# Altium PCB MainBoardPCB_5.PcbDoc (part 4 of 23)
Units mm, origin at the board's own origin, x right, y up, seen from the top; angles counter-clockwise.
Board outline 258.95 x 308.86 mm, 16 copper layers (L1, L2 (GND), L3 (Sign), L4 (GND), L5 (Sign), L6 (PWR/GND), L7(PWR/GND), L8 (Plane_GND), L9 (PWR/GND), L10 (PWR/GND), L11 (PWR/GND), L12 (Sign), L13 (GND), L14 (Sign), L15 (GND), L16), stack 2.502 mm thick; 2361 components, 1769 nets, 8410 pads, 3285 vias.
Unrouted connection lines stored in the file: 4635.

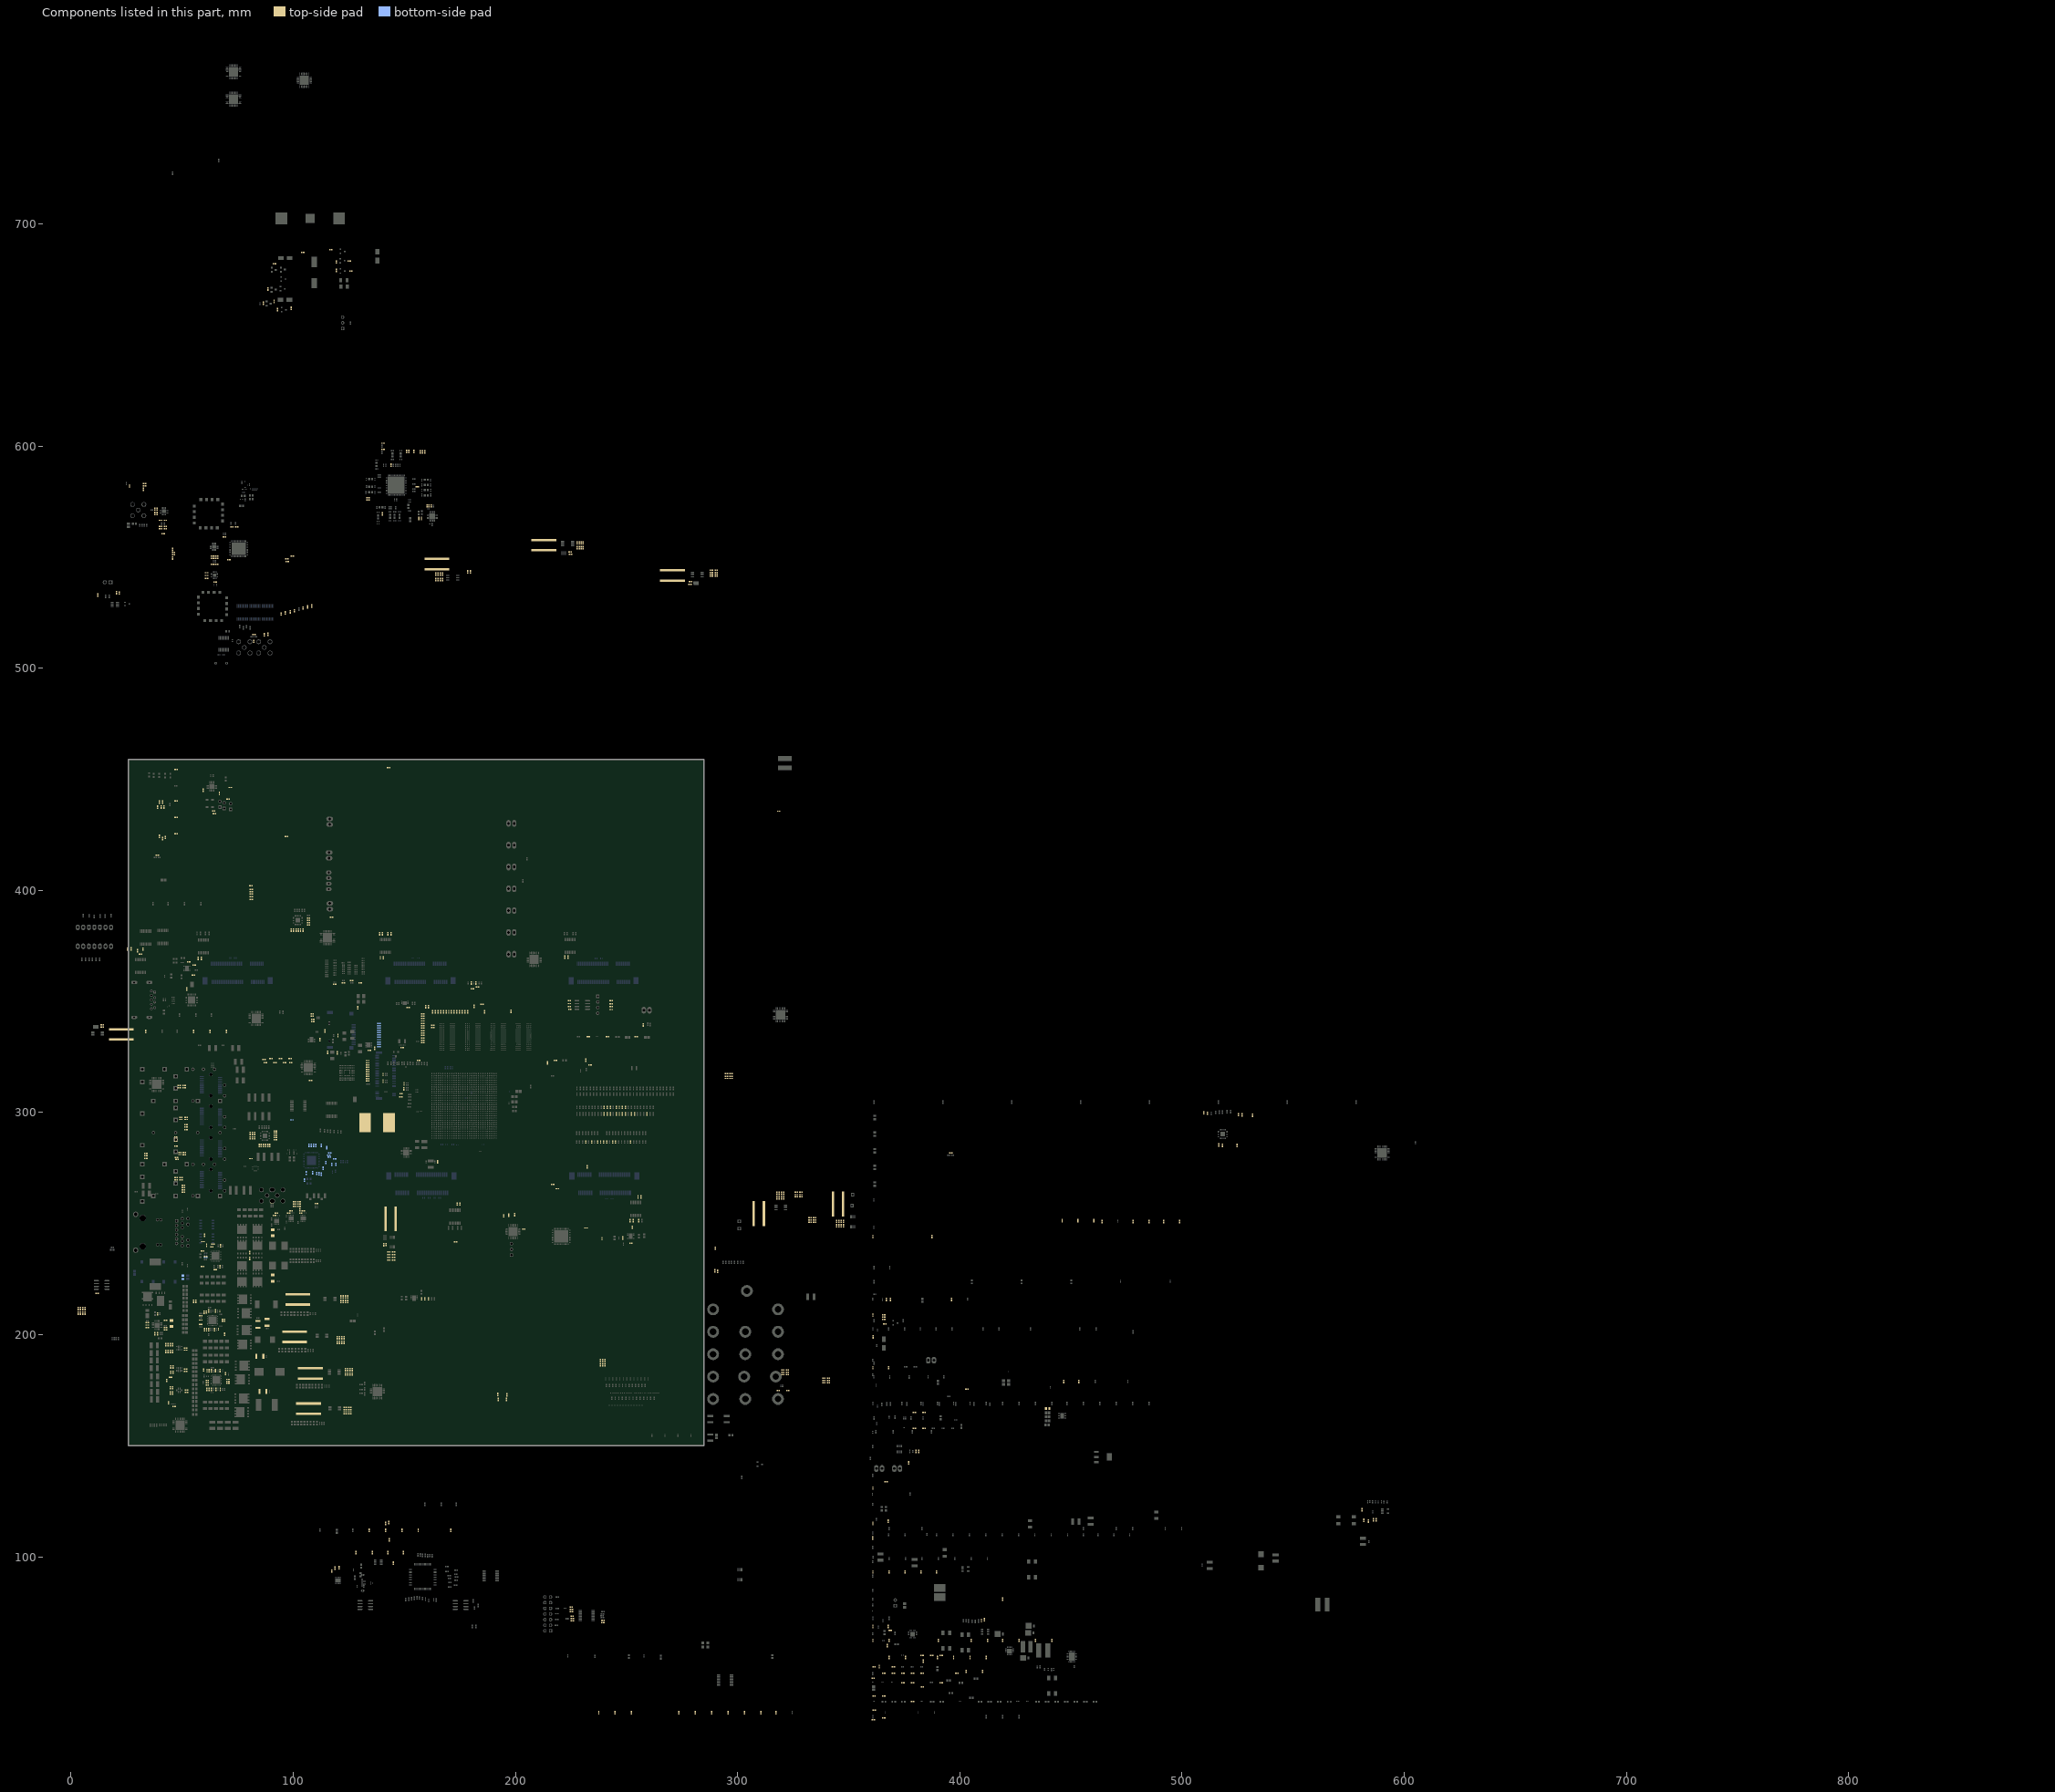
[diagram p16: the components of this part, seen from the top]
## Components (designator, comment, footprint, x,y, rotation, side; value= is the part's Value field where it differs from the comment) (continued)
R8_I2C_Bridge_SFP "1kR" "RES 0402/1005 RF" 92.004,291.728 r0 top (schematic designator R8)
R9_I2C_Bridge_GPIO "1kR" "RES 0402/1005 RF" 531.816,298.788 r90 top (schematic designator R9)
R9_I2C_Bridge_PCIE "1kR" "RES 0402/1005 RF" 106.896,387.59 r0 top (schematic designator R9)
R9_I2C_Bridge_SFP "1kR" "RES 0402/1005 RF" 92.004,290.754 r0 top (schematic designator R9)
R10_I2C_Bridge_GPIO "1kR" "RES 0402/1005 RF" 524.764,285.123 r90 top (schematic designator R10)
R10_I2C_Bridge_PCIE "1kR" "RES 0402/1005 RF" 106.896,386.535 r0 top (schematic designator R10)
R10_I2C_Bridge_SFP "1kR" "RES 0402/1005 RF" 92.004,289.78 r0 top (schematic designator R10)
R11 "10kR" "RES 0402/1005 RF" 51.56,183.563 r0 top
R12 "95.3kR" "RES 0402/1005 RF" 45.844,173.839 r270 top
R13 "10kR" "RES 0402/1005 RF" 51.568,193.051 r180 top
R14 "0mR" "RES 0402/1005 RF" 192.113,173.126 r90 top
R15 "95.3kR" "RES 0402/1005 RF" 45.94,183.113 r270 top
R16 "0mR" "RES 0402/1005 RF" 196.177,172.872 r90 top
R17 "95.3kR" "RES 0402/1005 RF" 45.94,185.524 r90 top
R18 "24.9kR" "RES 0402/1005 RF" 51.56,184.471 r180 top
R19 "4.87kR" "RES 0402/1005 RF" 44.801,173.839 r90 top
R20 "95.3kR" "RES 0402/1005 RF" 45.822,176.136 r90 top
R21 "24.9kR" "RES 0402/1005 RF" 52.05,175.125 r180 top
R22 "0mR" "RES 0402/1005 RF" 192.367,170.84 r90 top
R23 "4.87kR" "RES 0402/1005 RF" 44.92,183.113 r90 top
R24 "0mR" "RES 0402/1005 RF" 196.05,170.84 r90 top
R25 "4.87kR" "RES 0402/1005 RF" 44.92,185.524 r270 top
R26 "4.87kR" "RES 0402/1005 RF" 44.801,176.136 r270 top
R27 "1.02kR" "RES 0402/1005 RF" 46.46,167.684 r0 top
R28 "1.02kR" "RES 0402/1005 RF" 43.129,179.425 r270 top
R29 "10kR" "RES 0402/1005 RF" 43.904,169.348 r90 top
R30 "10kR" "RES 0402/1005 RF" 44.831,180.9 r180 top
R31 "39.2R" "RES 0402/1005 RF" 174.855,345.25 r90 top
R32 "39.2R" "RES 0402/1005 RF" 170.02,345.25 r90 top
R33 "39.2R" "RES 0402/1005 RF" 158.287,340.144 r180 top
R34 "39.2R" "RES 0402/1005 RF" 158.287,339.055 r180 top
R35 "39.2R" "RES 0402/1005 RF" 173.646,345.25 r90 top
R36 "39.2R" "RES 0402/1005 RF" 167.603,345.25 r90 top
R37 "39.2R" "RES 0402/1005 RF" 158.287,337.967 r180 top
R38 "39.2R" "RES 0402/1005 RF" 162.769,345.25 r90 top
R39 "39.2R" "RES 0402/1005 RF" 171.229,345.25 r90 top
R40 "39.2R" "RES 0402/1005 RF" 166.395,345.25 r90 top
R41 "39.2R" "RES 0402/1005 RF" 158.287,341.233 r180 top
R42 "39.2R" "RES 0402/1005 RF" 172.438,345.25 r90 top
R43 "39.2R" "RES 0402/1005 RF" 178.481,345.25 r90 top
R44 "39.2R" "RES 0402/1005 RF" 163.977,345.25 r90 top
R45 "39.2R" "RES 0402/1005 RF" 158.287,343.411 r180 top
R46 "39.2R" "RES 0402/1005 RF" 158.287,333.611 r180 top
R47 "39.2R" "RES 0402/1005 RF" 177.272,345.25 r90 top
R48 "39.2R" "RES 0402/1005 RF" 158.287,342.322 r180 top
R49 "39.2R" "RES 0402/1005 RF" 168.812,345.25 r90 top
R50 "39.2R" "RES 0402/1005 RF" 176.063,345.25 r90 top
R51 "39.2R" "RES 0402/1005 RF" 158.287,335.789 r180 top
R52 "36R" "RES 0402/1005 RF" 158.287,331.433 r180 top
R53 "39.2R" "RES 0402/1005 RF" 158.287,344.5 r180 top
R54 "36R" "RES 0402/1005 RF" 158.287,332.522 r180 top
R55 "39.2R" "RES 0402/1005 RF" 165.186,345.25 r90 top
R56 "499R" "RES 0402/1005 RF" 162.91,338.184 r180 top
R57 "39.2R" "RES 0402/1005 RF" 158.287,336.878 r180 top
R58 "4.7kR" "RES 0402/1005 RF" 162.91,339.242 r180 top
R59 "39.2R" "RES 0402/1005 RF" 158.287,334.7 r180 top
R60 "1kR" "RES 0402/1005 RF" 184.994,348.704 r180 top
R61 "240R" "RES 0402/1005 RF" 198.031,345.611 r90 top
R62 "240R" "RES 0402/1005 RF" 186.195,345.262 r90 top
R63 "240R" "RES 0402/1005 RF" 156.464,323.541 r180 top
R64 "240R" "RES 0402/1005 RF" 181.458,347.789 r90 top
R65 "4.7kR" "RES 0402/1005 RF" 50.624,266.152 r180 top
R66 "4.7kR" "RES 0402/1005 RF" 50.624,267.233 r180 top
R67 "4.7kR" "RES 0402/1005 RF" 50.624,264.12 r180 top
R68 "4.7kR" "RES 0402/1005 RF" 50.624,265.136 r180 top
R69 "100R" "RES 0402/1005 RF" 149.898,312.903 r270 top
R70 "100R" "RES 0402/1005 RF" 149.885,310.7 r90 top
R71 "0R" "RES 0402/1005 RF" 47.333,270.662 r180 top
R72 "0R" "RES 0402/1005 RF" 47.333,269.646 r180 top
R73 "0R" "RES 0402/1005 RF" 49.495,270.662 r180 top
R74 "0R" "RES 0402/1005 RF" 49.495,269.646 r180 top
R75 "0mR" "RES 0402/1005 RF" 90.504,259.536 r180 top
R76 "150R" "RES 0402/1005 RF" 110.431,258.992 r0 top
R77 "7.5kR" "RES 0402/1005 RF" 69.059,558.99 r180 top
R78 "100R" "RES 0402/1005 RF" 82.334,515.138 r0 top
R79 "150R" "RES 0402/1005 RF" 38.837,415.773 r0 top
R80 "160R" "RES 0402/1005 RF" 395.915,281.813 r0 top
R81 "100R" "RES 0402/1005 RF" 218.91,265.7 r180 top
R82 "100R" "RES 0402/1005 RF" 82.347,512.059 r90 top
R83 "4.7kR" "RES 0402/1005 RF" 108.547,344.313 r0 top
R84 "4.7kR" "RES 0402/1005 RF" 108.801,340.893 r0 top
R85 "4.7kR" "RES 0402/1005 RF" 108.547,343.433 r0 top
R86 "4.7kR" "RES 0402/1005 RF" 108.801,342.036 r0 top
R87 "30R" "RES 0402/1005 RF" 138.537,332.814 r180 bottom
R88 "30R" "RES 0402/1005 RF" 138.537,330.731 r180 bottom
R89 "30R" "RES 0402/1005 RF" 138.537,338.021 r180 bottom
R90 "30R" "RES 0402/1005 RF" 138.537,335.938 r180 bottom
R91 "0R" "RES 0402/1005 RF" 138.537,336.979 r180 bottom
R92 "0R" "RES 0402/1005 RF" 138.537,339.062 r180 bottom
R93 "0R" "RES 0402/1005 RF" 138.537,340.103 r180 bottom
R94 "0R" "RES 0402/1005 RF" 138.537,329.689 r180 bottom
R95 "30R" "RES 0402/1005 RF" 138.537,331.772 r180 bottom
R96 "30R" "RES 0402/1005 RF" 138.537,334.896 r180 bottom
R97 "4.7kR" "RES 0402/1005 RF" 138.537,333.855 r180 bottom
R98 "4.7kR" "RES 0402/1005 RF" 99.424,296.697 r180 bottom
R99 "4.7kR" "RES 0402/1005 RF" 367.411,60.089 r90 top
R100 "Resistance" "RES 0402/1005 RF" 318.491,435.623 r0 top
R101 "30R" "RES 0402/1005 RF" 133.566,322.351 r180 top
R102 "30R" "RES 0402/1005 RF" 133.566,320.319 r180 top
R103 "30R" "RES 0402/1005 RF" 133.566,318.287 r180 top
R104 "30R" "RES 0402/1005 RF" 133.566,316.255 r180 top
R105 "30R" "RES 0402/1005 RF" 133.566,321.335 r180 top
R106 "1kR" "RES 0402/1005 RF" 96.99,424.332 r180 top
R107 "30R" "RES 0402/1005 RF" 133.566,319.303 r180 top
R108 "30R" "RES 0402/1005 RF" 133.566,317.271 r180 top
R109 "1kR" "RES 0402/1005 RF" 142.964,455.193 r0 top
R110 "30R" "RES 0402/1005 RF" 133.566,323.367 r180 top
R111 "30R" "RES 0402/1005 RF" 133.566,315.214 r180 top
R112 "30R" "RES 0402/1005 RF" 133.566,314.223 r180 top
R113 "34.8kR" "RES 0402/1005 RF" 367.741,68.682 r90 top
R114 "10kR" "RES 0402/1005 RF" 360.883,68.682 r90 top
R115 "30R" "RES 0402/1005 RF" 98.895,322.478 r0 top
R116 "30R" "RES 0402/1005 RF" 96.101,322.478 r0 top
R117 "30R" "RES 0402/1005 RF" 91.783,322.478 r0 top
R118 "30R" "RES 0402/1005 RF" 87.465,322.478 r0 top
R119 "30R" "RES 0402/1005 RF" 98.641,324.256 r0 top
R120 "30R" "RES 0402/1005 RF" 94.323,324.256 r0 top
R121 "30R" "RES 0402/1005 RF" 90.005,324.256 r0 top
R122 "30R" "RES 0402/1005 RF" 86.83,323.875 r0 top
R123 "4.7kR" "RES 0402/1005 RF" 107.912,314.35 r0 top
R124 "1kR" "RES 0402/1005 RF" 173.063,241.833 r180 top
R125 "10kR" "RES 0402/1005 RF" 155.858,581.652 r180 top
R126 "100R" "RES 0402/1005 RF" 152.029,597.498 r270 top
R127 "0R" "RES 0402/1005 RF" 367.995,185.141 r90 top
R128 "10kR" "RES 0402/1005 RF" 133.738,575.768 r180 top
R129 "10kR" "RES 0402/1005 RF" 133.738,576.707 r180 top
R130 "0R" "RES 0402/1005 RF" 151.032,597.485 r270 top
R131 "0R" "RES 0402/1005 RF" 154.274,597.485 r270 top
R132 "0R" "RES 0402/1005 RF" 158.135,597.371 r90 top
R133 "0R" "RES 0402/1005 RF" 159.151,597.371 r90 top
R134 "0R" "RES 0402/1005 RF" 157.128,597.416 r90 top
R135 "4.7kR" "RES 0402/1005 RF" 47.725,278.917 r0 top
R136 "4.7kR" "RES 0402/1005 RF" 47.46,279.679 r0 top
R137 "4.7kR" "RES 0402/1005 RF" 47.275,284.886 r0 top
R138 "4.7kR" "RES 0402/1005 RF" 33.686,279.307 r0 top
R139 "0R" "RES 0402/1005 RF" 360.883,185.141 r90 top
R140 "2.2R" "RES 0402/1005 RF" 34.297,205.384 r180 top
R141 "0R" "RES 0402/1005 RF" 51.019,281.072 r0 top
R142 "0R" "RES 0402/1005 RF" 51.019,282.106 r0 top
R143 "0R" "RES 0402/1005 RF" 49.045,281.09 r0 top
R144 "0R" "RES 0402/1005 RF" 49.045,282.106 r0 top
R145 "4.7kR" "RES 0402/1005 RF" 47.206,289.077 r0 top
R146 "4.7kR" "RES 0402/1005 RF" 47.206,287.172 r0 top
R147 "4.7kR" "RES 0402/1005 RF" 47.206,288.061 r0 top
R148 "4.7kR" "RES 0402/1005 RF" 33.686,281.593 r0 top
R149 "196kR" "RES 0402/1005 RF" 34.323,204.343 r0 top
R150 "22k" "RES 0402/1005 RF" 42.652,206.468 r0 top
R151 "0R" "RES 0402/1005 RF" 51.863,297.915 r0 top
R152 "0R" "RES 0402/1005 RF" 51.816,296.899 r0 top
R153 "0R" "RES 0402/1005 RF" 49.45,297.915 r0 top
R154 "0R" "RES 0402/1005 RF" 49.45,296.899 r0 top
R155 "4.7kR" "RES 0402/1005 RF" 51.75,294.51 r0 top
R156 "4.7kR" "RES 0402/1005 RF" 51.75,293.494 r0 top
R157 "4.7kR" "RES 0402/1005 RF" 51.741,292.224 r0 top
R158 "4.7kR" "RES 0402/1005 RF" 33.686,280.568 r0 top
R159 "10kR" "RES 0402/1005 RF" 34.323,203.149 r0 top
R160 "910R" "RES 0402/1005 RF" 42.528,203.203 r180 top
R161 "0R" "RES 0402/1005 RF" 50.943,312.266 r0 top
R162 "0R" "RES 0402/1005 RF" 50.943,311.25 r0 top
R163 "0R" "RES 0402/1005 RF" 48.704,312.266 r0 top
R164 "0R" "RES 0402/1005 RF" 48.704,311.25 r0 top
R165 "100R" "RES 0402/1005 RF" 182.99,356.502 r0 top
R166 "100R" "RES 0402/1005 RF" 180.646,355.74 r0 top
R167 "100R" "RES 0402/1005 RF" 182.281,358.296 r90 top
R168 "100R" "RES 0402/1005 RF" 180.122,358.296 r90 top
R169 "100R" "RES 0402/1005 RF" 126.378,359.418 r0 top
R170 "100R" "RES 0402/1005 RF" 122.568,358.402 r0 top
R171 "100R" "RES 0402/1005 RF" 130.174,358.402 r0 top
R172 "100R" "RES 0402/1005 RF" 118.631,357.767 r0 top
R173 "500R" "RES 0402/1005 RF" 360.883,208.826 r90 top
R174 "0mR" "RES 0402/1005 RF" 167.244,539.921 r270 top
R175 "0mR" "RES 0402/1005 RF" 166.228,539.921 r270 top
R176 "0mR" "RES 0402/1005 RF" 165.212,539.921 r270 top
R177 "0mR" "RES 0402/1005 RF" 164.196,539.921 r270 top
R178 "0mR" "RES 0402/1005 RF" 167.244,542.334 r90 top
R179 "0mR" "RES 0402/1005 RF" 166.228,542.334 r90 top
R180 "0mR" "RES 0402/1005 RF" 165.212,542.334 r90 top
R181 "0mR" "RES 0402/1005 RF" 164.196,542.334 r90 top
R182 "1.02kR" "RES 0402/1005 RF" 178.585,543.303 r90 top
R183 "0mR" "RES 0402/1005 RF" 227.844,556.412 r90 top
R184 "0mR" "RES 0402/1005 RF" 228.733,556.412 r90 top
R185 "0mR" "RES 0402/1005 RF" 229.622,556.412 r90 top
R186 "0mR" "RES 0402/1005 RF" 230.511,556.412 r90 top
R187 "0mR" "RES 0402/1005 RF" 227.844,554.253 r270 top
R188 "0mR" "RES 0402/1005 RF" 228.733,554.253 r270 top
R189 "0mR" "RES 0402/1005 RF" 229.622,554.253 r270 top
R190 "0mR" "RES 0402/1005 RF" 230.511,554.253 r270 top
R191 "1.02kR" "RES 0402/1005 RF" 224.687,552.243 r0 top
R192 "0mR" "RES 0402/1005 RF" 6.377,209.702 r270 top
R193 "0mR" "RES 0402/1005 RF" 5.318,209.702 r270 top
R194 "0mR" "RES 0402/1005 RF" 4.26,209.702 r270 top
R195 "0mR" "RES 0402/1005 RF" 3.202,209.702 r270 top
R196 "0mR" "RES 0402/1005 RF" 6.377,211.734 r90 top
R197 "0mR" "RES 0402/1005 RF" 5.318,211.734 r90 top
R198 "0mR" "RES 0402/1005 RF" 4.26,211.734 r90 top
R199 "0mR" "RES 0402/1005 RF" 3.202,211.734 r90 top
R200 "1.02kR" "RES 0402/1005 RF" 14.092,339.522 r0 top
R201 "0mR" "RES 0402/1005 RF" 288.214,541.35 r180 top
R202 "0mR" "RES 0402/1005 RF" 288.214,542.239 r180 top
R203 "0mR" "RES 0402/1005 RF" 288.214,543.128 r180 top
R204 "0mR" "RES 0402/1005 RF" 288.214,544.017 r180 top
R205 "0mR" "RES 0402/1005 RF" 290.373,541.35 r0 top
R206 "0mR" "RES 0402/1005 RF" 290.373,542.239 r0 top
R207 "0mR" "RES 0402/1005 RF" 290.373,543.128 r0 top
R208 "0mR" "RES 0402/1005 RF" 290.373,544.017 r0 top
R209 "1.02kR" "RES 0402/1005 RF" 278.586,537.724 r180 top
R210 "0mR" "RES 0402/1005 RF" 145.265,233.515 r0 top
R211 "0mR" "RES 0402/1005 RF" 145.265,234.785 r0 top
R212 "12.5k" "RES 0402/1005 RF" 179.728,543.303 r90 top
R213 "0mR" "RES 0402/1005 RF" 145.265,236.055 r0 top
R214 "10kR" "RES 0402/1005 RF" 224.745,551.227 r0 top
R215 "0mR" "RES 0402/1005 RF" 145.265,237.325 r0 top
R216 "31.2kR" "RES 0402/1005 RF" 14.092,338.379 r0 top
R217 "0mR" "RES 0402/1005 RF" 143.048,233.515 r180 top
R218 "10kR" "RES 0402/1005 RF" 278.793,538.867 r180 top
R219 "0mR" "RES 0402/1005 RF" 143.048,234.785 r180 top
R220 "4.99kR" "RES 0402/1005 RF" 140.792,240.494 r270 top
R221 "0mR" "RES 0402/1005 RF" 143.048,236.055 r180 top
R222 "0mR" "RES 0402/1005 RF" 143.048,237.325 r180 top
R223_I2C_Bridge_GPIO "1kR" "RES 0402/1005 RF" 509.782,299.86 r90 top (schematic designator R223)
R223_I2C_Bridge_PCIE "1kR" "RES 0402/1005 RF" 106.896,385.48 r0 top (schematic designator R223)
R223_I2C_Bridge_SFP "1kR" "RES 0402/1005 RF" 92.004,288.807 r0 top (schematic designator R223)
R224_I2C_Bridge_GPIO "1kR" "RES 0402/1005 RF" 525.403,299.047 r90 top (schematic designator R224)
R224_I2C_Bridge_PCIE "1kR" "RES 0402/1005 RF" 106.896,384.424 r0 top (schematic designator R224)
R224_I2C_Bridge_SFP "1kR" "RES 0402/1005 RF" 92.004,287.833 r0 top (schematic designator R224)
R225_I2C_Bridge_GPIO "1kR" "RES 0402/1005 RF" 516.572,285.382 r90 top (schematic designator R225)
R225_I2C_Bridge_PCIE "1kR" "RES 0402/1005 RF" 104.356,382.099 r270 top (schematic designator R225)
R225_I2C_Bridge_SFP "1kR" "RES 0402/1005 RF" 89.523,285.166 r270 top (schematic designator R225)
R226_I2C_Bridge_GPIO "1kR" "RES 0402/1005 RF" 511.382,299.682 r90 top (schematic designator R226)
R226_I2C_Bridge_PCIE "1kR" "RES 0402/1005 RF" 103.32,382.099 r270 top (schematic designator R226)
R226_I2C_Bridge_SFP "1kR" "RES 0402/1005 RF" 88.558,285.166 r270 top (schematic designator R226)
R227_I2C_Bridge_GPIO "1kR" "RES 0402/1005 RF" 527.003,298.869 r90 top (schematic designator R227)
R227_I2C_Bridge_PCIE "1kR" "RES 0402/1005 RF" 102.32,382.099 r270 top (schematic designator R227)
R227_I2C_Bridge_SFP "1kR" "RES 0402/1005 RF" 87.592,285.166 r270 top (schematic designator R227)
R228 "1.02kR" "RES 0402/1005 RF" 141.808,240.552 r270 top
R229 "0mR" "RES 0402/1005 RF" 318.681,261.676 r270 top
R230 "0mR" "RES 0402/1005 RF" 317.665,261.676 r270 top
R231_SPI_bridge_Main "1kR" "RES 0402/1005 RF" 88.583,515.314 r90 top (schematic designator R231)
R231_SPI_bridge_PCIe "1kR" "RES 0402/1005 RF" 140.532,369.66 r270 top (schematic designator R231)
R232_SPI_bridge_Main "1kR" "RES 0402/1005 RF" 86.932,514.991 r90 top (schematic designator R232)
R232_SPI_bridge_PCIe "1kR" "RES 0402/1005 RF" 139.232,369.66 r90 top (schematic designator R232)
R233_SPI_bridge_Main "1kR" "RES 0402/1005 RF" 199.632,254.055 r90 top (schematic designator R233)
R233_SPI_bridge_PCIe "1kR" "RES 0402/1005 RF" 255.191,262.064 r90 top (schematic designator R233)
R234_SPI_bridge_Main "1kR" "RES 0402/1005 RF" 194.75,253.478 r90 top (schematic designator R234)
R234_SPI_bridge_PCIe "1kR" "RES 0402/1005 RF" 256.491,262.014 r270 top (schematic designator R234)
R235_SPI_bridge_Main "1kR" "RES 0402/1005 RF" 197.036,253.801 r90 top (schematic designator R235)
R235_SPI_bridge_PCIe "1kR" "RES 0402/1005 RF" 222.34,369.89 r270 top (schematic designator R235)
R236_SPI_bridge_Main "1kR" "RES 0402/1005 RF" 71.031,548.831 r180 top (schematic designator R236)
R236_SPI_bridge_PCIe "1kR" "RES 0402/1005 RF" 223.64,369.89 r270 top (schematic designator R236)
R237_SPI_bridge_Main "1kR" "RES 0402/1005 RF" 32.474,373.532 r90 top (schematic designator R237)
R237_SPI_bridge_PCIe "1kR" "RES 0402/1005 RF" 57.313,369.413 r270 top (schematic designator R237)
R238_SPI_bridge_Main "1kR" "RES 0402/1005 RF" 29.934,372.897 r90 top (schematic designator R238)
R238_SPI_bridge_PCIe "1kR" "RES 0402/1005 RF" 58.613,369.413 r270 top (schematic designator R238)
R239_SPI_bridge_Main "1kR" "RES 0402/1005 RF" 27.013,373.659 r90 top (schematic designator R239)
R239_SPI_bridge_PCIe "1kR" "RES 0402/1005 RF" 175.098,258.849 r270 top (schematic designator R239)
R240_SPI_bridge_Main "1kR" "RES 0402/1005 RF" 25.489,373.532 r90 top (schematic designator R240)
R240_SPI_bridge_PCIe "1kR" "RES 0402/1005 RF" 173.746,258.849 r90 top (schematic designator R240)
R241 "0mR" "RES 0402/1005 RF" 411.95,54.712 r90 top
R242 "0mR" "RES 0402/1005 RF" 404.584,54.712 r90 top
R243 "0mR" "RES 0402/1005 RF" 397.205,54.712 r90 top
R244 "0mR" "RES 0402/1005 RF" 389.839,54.712 r90 top
R245 "100R" "RES 0402/1005 RF" 41.478,560.591 r180 top
R246 "120R" "RES 0402/1005 RF" 42.463,566.56 r180 top
R247 "127R" "RES 0402/1005 RF" 42.463,562.75 r180 top
R248 "127R" "RES 0402/1005 RF" 40.362,562.75 r0 top
R249 "120R" "RES 0402/1005 RF" 40.362,566.56 r180 top
R250 "82.5R" "RES 0402/1005 RF" 42.463,563.766 r180 top
R251 "82.5R" "RES 0402/1005 RF" 40.362,563.766 r0 top
R252 "1kR" "RES 0402/1005 RF" 37.795,571.582 r90 top
R253 "1kR" "RES 0402/1005 RF" 37.795,569.578 r270 top
R254 "1kR" "RES 0402/1005 RF" 38.811,571.582 r270 top
R255 "1kR" "RES 0402/1005 RF" 38.811,569.578 r90 top
R256 "120R" "RES 0402/1005 RF" 65.57,546.671 r180 top
R257 "49.9R" "RES 0402/1005 RF" 64.877,538.798 r180 top
R258 "120R" "RES 0402/1005 RF" 63.633,546.671 r180 top
R259 "82.5R" "RES 0402/1005 RF" 63.633,550.481 r0 top
R260 "82.5R" "RES 0402/1005 RF" 65.57,550.481 r180 top
R261 "127R" "RES 0402/1005 RF" 63.633,549.466 r0 top
R262 "127R" "RES 0402/1005 RF" 65.57,549.466 r180 top
R263 "60.4kR" "RES 0402/1005 RF" 61.056,540.448 r0 top
R264 "0mR" "RES 0402/1005 RF" 61.056,542.959 r0 top
R265 "0mR" "RES 0402/1005 RF" 61.056,541.734 r0 top
R266 "84.5kR" "RES 0402/1005 RF" 60.181,244.78 r90 top
R267 "4.7kR" "RES 0402/1005 RF" 11.786,218.63 r0 top
R268 "2R" "RES 0402/1005 RF" 59.242,237.714 r0 top
R269 "1.02kR" "RES 0402/1005 RF" 361.511,31.064 r0 top
R270 "100R" "RES 0402/1005 RF" 238.976,243.23 r270 top
R271 "5kR" "RES 0402/1005 RF" 61.041,240.32 r90 top
R272 "2R" "RES 0402/1005 RF" 60.606,235.139 r180 top
R273 "12kR" "RES 0402/1005 RF" 63.389,239.52 r180 top
R274 "10kR" "RES 0402/1005 RF" 398.704,47.739 r0 top
R275 "47kR" "RES 0402/1005 RF" 80.488,236.914 r90 top
R276 "4.7kR" "RES 0402/1005 RF" 214.452,322.344 r270 top
R277 "12kR" "RES 0402/1005 RF" 64.94,229.317 r0 top
R278 "12kR" "RES 0402/1005 RF" 63.889,240.855 r0 top
R279 "0mR" "RES 0402/1005 RF" 383.045,47.739 r0 top
R280 "47kR" "RES 0402/1005 RF" 80.488,234.339 r270 top
R281 "0mR" "RES 0402/1005 RF" 383.481,53.104 r90 top
R282 "0mR" "RES 0402/1005 RF" 378.714,47.739 r0 top
R283 "0mR" "RES 0402/1005 RF" 374.383,47.739 r0 top
R284 "18.2k (1MHz)" "RES 0402/1005 RF" 378.663,34.963 r0 top
R285 "2R" "RES 0402/1005 RF" 59.753,184.12 r270 top
R286 "0mR" "RES 0402/1005 RF" 370.053,47.739 r0 top
R287 "49.9kR" "RES 0402/1005 RF" 61.241,183.809 r90 top
R288 "Resistor_1210" RES_1210 85.014,190.309 r180 top value=3.6R
R289 "2R" "RES 0402/1005 RF" 61.331,179.317 r180 top
R290 "10kR" "RES 0402/1005 RF" 62.191,183.809 r270 top
R291 "150R" "RES 0402/1005 RF" 365.722,47.739 r0 top
R292 "Resistance" "RES 0402/1005 RF" 70.661,179.917 r180 top
R293 "0mR" "RES 0402/1005 RF" 61.331,178.317 r0 top
R294 "0mR" "RES 0402/1005 RF" 61.331,177.317 r0 top
R295 "12kR" "RES 0402/1005 RF" 67.169,183.85 r270 top
R296 "12kR" "RES 0402/1005 RF" 67.204,175.367 r90 top
R297 "10kR" "RES 0402/1005 RF" 62.14,175.401 r270 top
R298 "Resistor_1210" RES_1210 86.39,174.414 r180 top value=3.6R
R299 "47kR" "RES 0402/1005 RF" 70.661,179.067 r180 top
R300 "10kR" "RES 0402/1005 RF" 61.068,175.401 r90 top
R301 "150R" "RES 0402/1005 RF" 391.655,43.434 r0 top
R302 "1.4kR" "RES 0201/0603" 66.453,202.488 r90 top
R303 "2R" "RES 0402/1005 RF" 55.203,215.087 r270 top
R304 "0mR" "RES 0402/1005 RF" 117.292,387.972 r0 top
R305 "100R" "RES 0402/1005 RF" 383.154,41.402 r0 top
R306 "Resistor_1210" RES_1210 88.316,205.562 r90 top value=3.6R
R307 "2R" "RES 0402/1005 RF" 58.395,206.596 r0 top
R308 "100R" "RES 0402/1005 RF" 378.689,43.434 r0 top
R309 "100R" "RES 0402/1005 RF" 374.358,43.434 r0 top
R310 "0mR" "RES 0402/1005 RF" 58.395,208.526 r180 top
R311 "100R" "RES 0402/1005 RF" 368.676,67.005 r0 top
R312 "0mR" "RES 0402/1005 RF" 58.376,204.716 r0 top
R313 "12kR" "RES 0402/1005 RF" 64.953,210.754 r270 top
R314 "12kR" "RES 0402/1005 RF" 64.623,202.273 r90 top
R315 "196kR" "RES 0402/1005 RF" 61.041,202.273 r270 top
R316 "Resistor_1210" RES_1210 84.163,204.643 r270 top value=3.6R
R317 "47kR" "RES 0402/1005 RF" 68.656,206.039 r180 top
R318 "27kR" "RES 0402/1005 RF" 60.114,202.273 r90 top
R319 "10kR" "RES 0402/1005 RF" 117.299,276.692 r90 bottom
R320 "10kR" "RES 0402/1005 RF" 115.069,284.177 r90 bottom
R321 "100R" "RES 0402/1005 RF" 119.191,276.704 r90 bottom
R322 "5.76kR" "RES 0402/1005 RF" 113.468,274.906 r90 bottom
R323 "5.76kR" "RES 0402/1005 RF" 114.688,277.499 r90 bottom
R324 "100kR" "RES 0805/2012 RF" 50.292,225.882 r90 bottom
R325 "2.49kR" "RES 0402/1005 RF" 118.694,279.122 r0 bottom
R326 "2.49kR" "RES 0402/1005 RF" 116.313,279.884 r0 bottom
R327 "2.49kR" "RES 0402/1005 RF" 116.072,280.722 r0 bottom
R328 "2.49kR" "RES 0402/1005 RF" 116.402,281.809 r0 bottom
R329 "100R" "RES 0402/1005 RF" 107.08,285.243 r90 bottom
R330 "100R" "RES 0402/1005 RF" 108.16,285.205 r90 bottom
R331 "100R" "RES 0402/1005 RF" 109.176,285.251 r90 bottom
R332 "100R" "RES 0402/1005 RF" 112.694,285.243 r270 bottom
R333 "2.2kR" "RES 0402/1005 RF" 108.79,272.944 r90 bottom
R334 "11kR" "RES 0402/1005" 105.81,272.708 r270 bottom
R335 "1MR" "RES 0402/1005 RF" 105.112,269.597 r90 bottom
R336 "2.2kR" "RES 0402/1005 RF" 112.702,272.331 r90 bottom
R337 "2.2kR" "RES 0402/1005 RF" 110.649,272.581 r90 bottom
R338 "2.2kR" "RES 0402/1005 RF" 111.614,272.449 r90 bottom
R339 "105kR" "RES 0402/1005 RF" 120.155,334.607 r90 top
R340 "10kR" "RES 0402/1005 RF" 112.037,332.737 r90 top
R341 "15kR" "RES 0402/1005 RF" 114.38,336.692 r90 top
R342 "105kR" "RES 0402/1005 RF" 115.595,327.144 r90 top
R343 "10kR" "RES 0402/1005 RF" 134.277,328.019 r180 top
R344 "15kR" "RES 0402/1005 RF" 119.837,326.801 r90 top
R345 "0R" "RES 0402/1005 RF" 136.729,328.835 r90 top
R346 "4.7kR" "RES 0402/1005 RF" 70.724,441.147 r0 top
R347 "4.7kR" "RES 0402/1005 RF" 148.521,307.124 r0 top
R348 "4.7kR" "RES 0402/1005 RF" 148.559,308.47 r0 top
R349 "4.7kR" "RES 0402/1005 RF" 243.109,346.354 r0 top
R350 "4.7kR" "RES 0402/1005 RF" 243.109,347.667 r0 top
R351 "4.7kR" "RES 0402/1005 RF" 243.109,348.979 r0 top
R352 "4.7kR" "RES 0402/1005 RF" 243.109,350.291 r0 top
R353 "4.7kR" "RES 0402/1005 RF" 39.771,424.265 r90 top
R354 "4.7kR" "RES 0402/1005 RF" 64.224,435.813 r0 top
R355 "4.7kR" "RES 0402/1005 RF" 64.605,434.543 r0 top
R356 "4.7kR" "RES 0402/1005 RF" 42.498,423.815 r270 top
R357 "4.7kR" "RES 0402/1005 RF" 41.198,423.365 r90 top
R358 "499R" "RES 0402/1005 RF" 224.515,346.472 r180 top
R359 "499R" "RES 0402/1005 RF" 224.315,347.751 r180 top
R360 "499R" "RES 0402/1005 RF" 224.315,349.021 r180 top
R361 "499R" "RES 0402/1005 RF" 224.315,350.291 r180 top
R362 "30R" "RES 0402/1005 RF" 39.009,437.413 r90 top
R363 "4.7kR" "RES 0402/1005 RF" 39.771,439.768 r90 top
R364 "4.7kR" "RES 0402/1005 RF" 40.548,437.482 r90 top
R365 "4.7kR" "RES 0402/1005 RF" 41.93,437.54 r90 top
R366 "10kR" "RES 0402/1005 RF" 41.295,439.699 r90 top
R367 "4.7kR" "RES 0402/1005 RF" 71.74,446.303 r0 top
R368 "261R" "RES 0402/1005 RF" 47.333,454.431 r180 top
R369 "10kR" "RES 0402/1005 RF" 66.787,443.56 r90 top
R370 "10kR" "RES 0402/1005 RF" 47.333,425.475 r180 top
R371 "10kR" "RES 0402/1005 RF" 47.333,432.841 r180 top
R372 "8.06kR" "RES 0402/1005 RF" 47.333,440.207 r180 top
R373 "10kR" "RES 0402/1005 RF" 59.548,445.084 r90 top
R374 "4.7MR" "RES 0402/1005 RF" 149.073,329.222 r0 top
R375 "40.2R" "RES 0402/1005 RF" 129.107,347.154 r270 top
R376 "0R" "RES 0402/1005 RF" 69.977,336.448 r90 top
R377 "0R" "RES 0402/1005 RF" 62.611,336.448 r90 top
R378 "0R" "RES 0402/1005 RF" 55.245,336.448 r90 top
R379 "8.06kR" "RES 0402/1005 RF" 33.655,336.448 r90 top
R380 "4.22kR" "RES 0402/1005 RF" 453.555,178.905 r90 top
R381 "4.7kR" "RES 0402/1005 RF" 381.571,147.474 r90 top
R382 "4.7kR" "RES 0402/1005 RF" 380.289,147.48 r90 top
R383 "10kR" "RES 0402/1005 RF" 396.189,215.862 r90 top
R384 "71.5R" "RES 0402/1005 RF" 365.76,208.915 r0 top
R385 "71.5R" "RES 0402/1005 RF" 365.76,207.899 r0 top
R386 "8.87kR" "RES 0402/1005 RF" 365.76,206.883 r0 top
R387 "5.1kR" "RES 0402/1005 RF" 366.23,204.826 r0 top
R388 "0mR" "RES 0402/1005 RF" 289.784,228.694 r90 top
R389 "0mR" "RES 0402/1005 RF" 291.054,228.509 r90 top
R390 "0mR" "RES 0402/1005 RF" 289.911,238.904 r90 top
R391 "75kR" "RES 0402/1005 RF" 103.42,254.796 r180 top
R392 "100kR" "RES 0402/1005 RF" 102.991,256.279 r270 top
R393 "15kR" "RES 0402/1005 RF" 104.62,255.77 r180 top
R394 "51.1kR" "RES 0402/1005 RF" 98.051,254.796 r180 top
R395 "0mR" "RES 0402/1005 RF" 97.16,549.161 r0 top
R396 "15kR" "RES 0402/1005 RF" 99.012,255.77 r180 top
R397 "21.5kR" "RES 0402/1005 RF" 91.606,253.618 r180 top
R398 "0mR" "RES 0402/1005 RF" 97.356,547.954 r0 top
R399 "15kR" "RES 0402/1005 RF" 92.461,254.68 r180 top
R400 "0mR" "RES 0402/1005 RF" 375.615,54.712 r90 top
R401 "10k" "RES 0402/1005 RF" 239.331,70.383 r0 top
R402 "0R" "RES 0402/1005 RF" 225.184,76.378 r0 top
R403 "0R" "RES 0402/1005 RF" 225.127,77.318 r0 top
R404 "0R" "RES 0402/1005 RF" 225.285,75.438 r0 top
R405 "0R" "RES 0402/1005 RF" 239.395,71.552 r0 top
R406 "0R" "RES 0402/1005 RF" 225.577,72.212 r0 top
R407 "0R" "RES 0402/1005 RF" 225.532,73.279 r0 top
R408 "0R" "RES 0402/1005 RF" 225.608,71.234 r0 top
R409 "0R" "RES 0402/1005 RF" 498.805,250.965 r90 top
R410 "10k" "RES 0402/1005 RF" 491.693,250.965 r90 top
R411 "0R" "RES 0402/1005 RF" 485.089,250.965 r90 top
R412 "0R" "RES 0402/1005 RF" 477.977,250.965 r90 top
R413 "0R" "RES 0402/1005 RF" 464.007,250.965 r90 top
R414 "0R" "RES 0402/1005 RF" 460.273,251.338 r90 top
R415 "0R" "RES 0402/1005 RF" 453.161,251.338 r90 top
R416 "0R" "RES 0402/1005 RF" 446.037,251.338 r90 top
R417 "10k" "RES 0402/1005 RF" 149.639,101.956 r90 top
R418 "0R" "RES 0402/1005 RF" 145.11,97.168 r90 top
R419 "2kR" "RES 0402/1005 RF" 142.527,101.956 r90 top
R420 "10k" "RES 0402/1005 RF" 128.291,101.956 r90 top
R421 "0R" "RES 0402/1005 RF" 135.657,101.956 r90 top
R422 "10k" "RES 0402/1005 RF" 303.035,29.858 r90 top
R423 "12kR" "RES 0402/1005 RF" 410.159,48.476 r90 top
R424 "1kR" "RES 0402/1005 RF" 402.793,48.476 r90 top
R425_SPI_bridge_Main "0mR" "RES 0402/1005 RF" 100.465,525.843 r90 top (schematic designator R425)
R425_SPI_bridge_PCIe "0mR" "RES 0402/1005 RF" 144.057,380.477 r90 top (schematic designator R425)
R426_SPI_bridge_Main "0mR" "RES 0402/1005 RF" 108.364,528.041 r90 top (schematic designator R426)
R426_SPI_bridge_PCIe "0mR" "RES 0402/1005 RF" 140.183,380.427 r270 top (schematic designator R426)
R427 "1kR" "RES 0402/1005 RF" 365.722,37.401 r0 top
R428 "1kR" "RES 0402/1005 RF" 368.249,54.712 r90 top
R429 "0mR" "RES 0402/1005 RF" 80.988,279.244 r0 top
R430_5V_to_3V3_for_FTDI "105kR" "RES 0402/1005 RF" 117.373,93.624 r90 top (schematic designator R430)
R430_U_5V_to_3V31 "105kR" "RES 0402/1005 RF" 160.801,216.124 r270 top (schematic designator R430)
R430_U_5V_to_3V32 "105kR" "RES 0402/1005 RF" 248.361,243.489 r270 top (schematic designator R430)
R430_U_5V_to_3V33 "105kR" "RES 0402/1005 RF" 55.435,366.446 r0 top (schematic designator R430)
R431_5V_to_3V3_for_FTDI "100kR" "RES 0402/1005 RF" 120.625,95.096 r90 top (schematic designator R431)
R431_U_5V_to_3V31 "100kR" "RES 0402/1005 RF" 157.728,216.123 r90 top (schematic designator R431)
R431_U_5V_to_3V32 "100kR" "RES 0402/1005 RF" 252.578,248.374 r90 top (schematic designator R431)
R431_U_5V_to_3V33 "100kR" "RES 0402/1005 RF" 52.959,367.754 r0 top (schematic designator R431)
R432_5V_to_3V3_for_FTDI "15kR" "RES 0402/1005 RF" 118.859,94.943 r90 top (schematic designator R432)
R432_U_5V_to_3V31 "15kR" "RES 0402/1005 RF" 159.201,216.148 r90 top (schematic designator R432)
R432_U_5V_to_3V32 "15kR" "RES 0402/1005 RF" 252.019,241.198 r180 top (schematic designator R432)
R432_U_5V_to_3V33 "15kR" "RES 0402/1005 RF" 55.135,361.888 r0 top (schematic designator R432)
R433 "56kR" "RES 0402/1005 RF" 383.921,157.861 r0 top
R434 "10kR" "RES 0402/1005 RF" 379.603,157.861 r0 top
R435 "10kR" "RES 0402/1005 RF" 368.719,215.913 r90 top
R436 "3.57kR" "RES 0402/1005 RF" 156.62,567.382 r90 top
R437 "1.15kR" "RES 0402/1005 RF" 403.213,175.514 r0 top
R438 "3.57kR" "RES 0402/1005 RF" 161.142,573.034 r90 top
R439 "1.15kR" "RES 0402/1005 RF" 160.176,573.034 r270 top
R440 "20kR" "RES 0402/1005 RF" 157.697,567.382 r90 top
R441 "20kR" "RES 0402/1005 RF" 162.089,573.034 r90 top
R442 "100kR" "RES 0402/1005 RF" 360.934,199.009 r90 top
R443 "698kR" "RES 0805/2012 RF" 439.547,166.751 r0 top
R444 "49.9kR" "RES 0402/1005 RF" 383.921,164.973 r0 top
R445 "49.9kR" "RES 0402/1005 RF" 379.603,164.973 r0 top
R446 "120R" "RES 0402/1005 RF" 20.436,533.946 r90 top
R447 "120R" "RES 0402/1005 RF" 21.667,533.844 r90 top
R448_U_Pomiar_pradu_napiecia_1 "FCSL110R005FER" FCSL110R005FERCT-ND 309.537,254.495 r0 top (schematic designator R448)
R448_U_Pomiar_pradu_napiecia_2 "FCSL110R005FER" FCSL110R005FERCT-ND 345.148,258.851 r180 top (schematic designator R448)
R448_U_Pomiar_pradu_napiecia_3 "FCSL110R005FER" FCSL110R005FERCT-ND 107.759,182.601 r90 top (schematic designator R448)
R448_U_Pomiar_pradu_napiecia_4 "FCSL110R005FER" FCSL110R005FERCT-ND 106.904,166.738 r90 top (schematic designator R448)
R448_U_Pomiar_pradu_napiecia_5 "FCSL110R005FER" FCSL110R005FERCT-ND 102.092,215.887 r90 top (schematic designator R448)
R448_U_Pomiar_pradu_napiecia_6 "FCSL110R005FER" FCSL110R005FERCT-ND 100.635,199.06 r90 top (schematic designator R448)
R448_U_Pomiar_pradu_napiecia_7 "FCSL110R005FER" FCSL110R005FERCT-ND 164.668,546.875 r90 top (schematic designator R448)
R448_U_Pomiar_pradu_napiecia_8 "FCSL110R005FER" FCSL110R005FERCT-ND 212.776,555.38 r90 top (schematic designator R448)
R448_U_Pomiar_pradu_napiecia_9 "FCSL110R005FER" FCSL110R005FERCT-ND 22.669,335.204 r270 top (schematic designator R448)
R448_U_Pomiar_pradu_napiecia_10 "FCSL110R005FER" FCSL110R005FERCT-ND 270.688,541.731 r270 top (schematic designator R448)
R448_U_Pomiar_pradu_napiecia_11 "FCSL110R005FER" FCSL110R005FERCT-ND 143.891,252.125 r0 top (schematic designator R448)
R449 "0mR" "RES 0402/1005 RF" 81.09,400.473 r0 top
R450 "0mR" "RES 0402/1005 RF" 81.09,399.457 r0 top
R451 "0mR" "RES 0402/1005 RF" 81.09,395.901 r0 top
R452 "0mR" "RES 0402/1005 RF" 80.963,401.997 r0 top
R453 "0mR" "RES 0402/1005 RF" 81.09,397.229 r0 top
R454 "0mR" "RES 0402/1005 RF" 81.09,398.314 r0 top
R455 "0mR" "RES 0402/1005 RF" 240.373,186.426 r270 top
R456 "0mR" "RES 0402/1005 RF" 240.373,188.458 r90 top
R457 "0mR" "RES 0402/1005 RF" 319.697,261.676 r270 top
R458 "0mR" "RES 0402/1005 RF" 239.357,186.426 r270 top
R459 "0mR" "RES 0402/1005 RF" 320.713,261.676 r270 top
R460 "0mR" "RES 0402/1005 RF" 239.357,188.458 r90 top
R461 "0mR" "RES 0402/1005 RF" 318.681,263.708 r90 top
R462 "0mR" "RES 0402/1005 RF" 238.214,186.426 r270 top
R463 "0mR" "RES 0402/1005 RF" 317.665,263.708 r90 top
R464 "0mR" "RES 0402/1005 RF" 238.214,188.458 r90 top
R465 "0mR" "RES 0402/1005 RF" 319.697,263.708 r90 top
R466 "0mR" "RES 0402/1005 RF" 320.713,263.708 r90 top
R467 "0mR" "RES 0402/1005 RF" 345.529,249.003 r270 top
R468 "0mR" "RES 0402/1005 RF" 344.513,249.003 r270 top
R469 "0mR" "RES 0402/1005 RF" 80.623,290.569 r90 top
R470 "0mR" "RES 0402/1005 RF" 80.623,288.595 r270 top
R471 "0mR" "RES 0402/1005 RF" 81.639,290.569 r90 top
R472 "0mR" "RES 0402/1005 RF" 81.639,288.595 r270 top
R473 "0mR" "RES 0402/1005 RF" 82.655,290.569 r90 top
R474 "0mR" "RES 0402/1005 RF" 82.655,288.595 r270 top
R475 "0mR" "RES 0402/1005 RF" 102.629,259.923 r0 top
R476 "0mR" "RES 0402/1005 RF" 100.655,259.923 r180 top
R477 "0mR" "RES 0402/1005 RF" 102.629,258.907 r0 top
R478 "0mR" "RES 0402/1005 RF" 100.655,258.907 r180 top
R479 "0mR" "RES 0402/1005 RF" 102.629,257.845 r0 top
R480 "0mR" "RES 0402/1005 RF" 100.655,257.845 r180 top
R481 "0R" "RES 0402/1005 RF" 31.318,371.361 r0 top
R482 "150R" "RES 0402/1005 RF" 46.165,552.036 r180 top
R483 "150R" "RES 0402/1005 RF" 46.165,551.036 r180 top
R484 "71.5R" "RES 0402/1005 RF" 45.715,553.486 r270 top
R485 "71.5R" "RES 0402/1005 RF" 45.715,549.586 r90 top
R486 "8.87kR" "RES 0402/1005 RF" 26.365,581.955 r90 top
R487 "5.1kR" "RES 0402/1005 RF" 33.123,582.03 r180 top
R488 "1kR" "RES 0402/1005 RF" 33.123,583.046 r180 top
R489 "100R" "RES 0402/1005 RF" 32.673,580.558 r90 top
R490 "10kR" "RES 0402/1005 RF" 52.083,355.6 r90 top
R491 "1MR" "RES 0402/1005 RF" 446.697,178.905 r90 top
R492 "0mR" "RES 0402/1005 RF" 320.345,184.208 r180 top
R493 "0mR" "RES 0402/1005 RF" 322.377,184.208 r0 top
R494 "0mR" "RES 0402/1005 RF" 320.345,183.134 r180 top
R495 "0mR" "RES 0402/1005 RF" 322.377,183.134 r0 top
R496 "0mR" "RES 0402/1005 RF" 320.345,182.118 r180 top
R497 "0mR" "RES 0402/1005 RF" 322.377,182.118 r0 top
R498 "0R" "RES 0402/1005 RF" 322.589,174.921 r0 top
R499 "1kR" "RES 0402/1005 RF" 318.271,174.921 r0 top
R500 "0mR" "RES 0402/1005 RF" 338.829,180.398 r180 top
R501 "0mR" "RES 0402/1005 RF" 340.861,180.398 r0 top
R502 "0mR" "RES 0402/1005 RF" 338.829,178.308 r180 top
R503 "0mR" "RES 0402/1005 RF" 340.861,178.308 r0 top
R504 "0mR" "RES 0402/1005 RF" 338.829,179.324 r180 top
R505 "0mR" "RES 0402/1005 RF" 340.861,179.324 r0 top
R506 "0mR" "RES 0402/1005 RF" 99.645,550.388 r180 top
R507 "0mR" "RES 0402/1005 RF" 257.585,339.404 r90 top
R508 "0mR" "RES 0402/1005 RF" 295.013,317.456 r180 top
R509 "0mR" "RES 0402/1005 RF" 297.045,317.456 r0 top
R510 "0mR" "RES 0402/1005 RF" 295.013,316.382 r180 top
R511 "0mR" "RES 0402/1005 RF" 297.045,316.382 r0 top
R512 "0mR" "RES 0402/1005 RF" 295.013,315.366 r180 top
R513 "0mR" "RES 0402/1005 RF" 297.045,315.366 r0 top
R514 "0mR" "RES 0402/1005 RF" 232.321,275.596 r270 top
R515 "10kR" "RES 0402/1005 RF" 242.686,299.297 r90 top
R516 "0mR" "RES 0402/1005 RF" 332.633,252.686 r180 top
R517 "0mR" "RES 0402/1005 RF" 334.665,252.686 r0 top
R518 "0mR" "RES 0402/1005 RF" 332.633,251.612 r180 top
R519 "0mR" "RES 0402/1005 RF" 334.665,251.612 r0 top
R520 "0mR" "RES 0402/1005 RF" 332.633,250.596 r180 top
R521 "0mR" "RES 0402/1005 RF" 334.665,250.596 r0 top
R522 "10kR" "RES 0402/1005 RF" 245.413,299.297 r90 top
R523 "10kR" "RES 0402/1005 RF" 231.607,286.757 r270 top
R524 "0mR" "RES 0402/1005 RF" 326.436,264.116 r180 top
R525 "0mR" "RES 0402/1005 RF" 328.468,264.116 r0 top
R526 "0mR" "RES 0402/1005 RF" 326.436,263.042 r180 top
R527 "0mR" "RES 0402/1005 RF" 328.468,263.042 r0 top
R528 "0mR" "RES 0402/1005 RF" 326.436,262.026 r180 top
R529 "0mR" "RES 0402/1005 RF" 328.468,262.026 r0 top
R530 "0mR" "RES 0402/1005 RF" 242.686,302.335 r90 top
R531 "10kR" "RES 0402/1005 RF" 239.96,299.297 r90 top
R532 "75R" "RES 0402/1005 RF" 72.416,563.562 r180 top
R533 "30R" "RES 0402/1005 RF" 74.506,563.562 r180 top
R534 "160R" "RES 0402/1005 RF" 231.864,248.056 r0 top
R535 "100R" "RES 0402/1005 RF" 203.797,247.548 r0 top
R536 "100R" "RES 0402/1005 RF" 216.76,267.632 r180 top
R538 "1kR" "RES 0402/1005 RF" 361.391,37.401 r0 top
R540 "0R" "RES 0402/1005 RF" 143.973,591.371 r270 top
R541 "100R" "RES 0402/1005 RF" 140.462,314.124 r90 top
R542 "100R" "RES 0402/1005 RF" 140.462,317.125 r90 top
R543 "100R" "RES 0402/1005 RF" 140.433,601.251 r180 top
R544 "1kR" "RES 0402/1005 RF" 140.11,569.418 r90 top
R545 "49.9R" "RES 0402/1005 RF" 140.433,598.457 r180 top
R546 "10kR" "RES 0402/1005 RF" 237.005,286.757 r270 top
R547 "0mR" "RES 0402/1005 RF" 245.413,302.335 r90 top
R548 "10kR" "RES 0402/1005 RF" 241.323,299.297 r90 top
R549 "10kR" "RES 0402/1005 RF" 234.306,286.757 r270 top
R550 "0mR" "RES 0402/1005 RF" 239.96,302.335 r90 top
R551 "10kR" "RES 0402/1005 RF" 246.776,299.297 r90 top
R552 "10kR" "RES 0402/1005 RF" 251.85,286.757 r270 top
R553 "0mR" "RES 0402/1005 RF" 241.323,302.335 r90 top
R554 "10kR" "RES 0402/1005 RF" 248.14,299.297 r90 top
R555 "10kR" "RES 0402/1005 RF" 243.753,286.757 r270 top
R556 "0mR" "RES 0402/1005 RF" 246.776,302.335 r90 top
R557 "10kR" "RES 0402/1005 RF" 249.503,299.297 r90 top
R558_I2C_Bridge_GPIO "1kR" "RES 0402/1005 RF" 518.173,285.204 r90 top (schematic designator R558)
R558_I2C_Bridge_PCIE "1kR" "RES 0402/1005 RF" 101.32,382.099 r270 top (schematic designator R558)
R558_I2C_Bridge_SFP "1kR" "RES 0402/1005 RF" 86.627,285.166 r270 top (schematic designator R558)
R559_I2C_Bridge_GPIO "1kR" "RES 0402/1005 RF" 387.541,244.17 r90 top (schematic designator R559)
R559_I2C_Bridge_PCIE "1kR" "RES 0402/1005 RF" 100.135,382.099 r270 top (schematic designator R559)
R559_I2C_Bridge_SFP "1kR" "RES 0402/1005 RF" 85.662,285.166 r270 top (schematic designator R559)
R560_I2C_Bridge_GPIO "1kR" "RES 0402/1005 RF" 360.883,244.17 r90 top (schematic designator R560)
R560_I2C_Bridge_PCIE "1kR" "RES 0402/1005 RF" 99.022,382.099 r270 top (schematic designator R560)
R560_I2C_Bridge_SFP "1kR" "RES 0402/1005 RF" 84.696,285.166 r270 top (schematic designator R560)
R561 "0mR" "RES 0402/1005 RF" 124.498,184.31 r90 top
R562 "0mR" "RES 0402/1005 RF" 123.482,184.31 r90 top
R563 "0mR" "RES 0402/1005 RF" 125.514,184.31 r90 top
R564 "0mR" "RES 0402/1005 RF" 126.53,184.31 r90 top
R565 "0mR" "RES 0402/1005 RF" 124.498,182.278 r270 top
R566 "0mR" "RES 0402/1005 RF" 123.482,182.278 r270 top
R567 "0mR" "RES 0402/1005 RF" 125.514,182.278 r270 top
R568 "0mR" "RES 0402/1005 RF" 126.53,182.278 r270 top
R569 "0mR" "RES 0402/1005 RF" 125.539,165.349 r0 top
R570 "0mR" "RES 0402/1005 RF" 125.539,164.333 r0 top
R571 "0mR" "RES 0402/1005 RF" 125.539,166.365 r0 top
R572 "0mR" "RES 0402/1005 RF" 125.54,167.381 r0 top
R573 "0mR" "RES 0402/1005 RF" 123.507,165.349 r180 top
R574 "0mR" "RES 0402/1005 RF" 123.508,164.333 r180 top
R575 "0mR" "RES 0402/1005 RF" 123.508,166.365 r180 top
R576 "0mR" "RES 0402/1005 RF" 123.508,167.381 r180 top
R577 "0mR" "RES 0402/1005 RF" 122.504,216.987 r90 top
R578 "0mR" "RES 0402/1005 RF" 121.488,216.987 r90 top
R579 "0mR" "RES 0402/1005 RF" 123.52,216.987 r90 top
R580 "0mR" "RES 0402/1005 RF" 124.536,216.987 r90 top
R581 "0mR" "RES 0402/1005 RF" 122.504,214.955 r270 top
R582 "0mR" "RES 0402/1005 RF" 121.488,214.955 r270 top
R583 "0mR" "RES 0402/1005 RF" 123.52,214.955 r270 top
R584 "0mR" "RES 0402/1005 RF" 124.536,214.955 r270 top
R585 "0mR" "RES 0402/1005 RF" 120.872,196.601 r270 top
R586 "0mR" "RES 0402/1005 RF" 119.856,196.601 r270 top
R587 "0mR" "RES 0402/1005 RF" 121.888,196.601 r270 top
R588 "0mR" "RES 0402/1005 RF" 122.904,196.601 r270 top
R589 "0mR" "RES 0402/1005 RF" 120.872,198.633 r90 top
R590 "0mR" "RES 0402/1005 RF" 119.856,198.633 r90 top
R591 "0mR" "RES 0402/1005 RF" 121.888,198.633 r90 top
R592 "0mR" "RES 0402/1005 RF" 122.904,198.633 r90 top
R593 "0mR" "RES 0402/1005 RF" 346.545,249.003 r270 top
R594 "0mR" "RES 0402/1005 RF" 347.561,249.003 r270 top
R595 "0mR" "RES 0402/1005 RF" 345.529,251.035 r90 top
R596 "0mR" "RES 0402/1005 RF" 344.513,251.035 r90 top
R597 "0mR" "RES 0402/1005 RF" 346.545,251.035 r90 top
R598 "0mR" "RES 0402/1005 RF" 347.561,251.035 r90 top
R599 "1kR" "RES 0402/1005 RF" 363.753,50.691 r90 top
R600 "0mR" "RES 0402/1005 RF" 367.741,116.091 r90 top
R601 "0mR" "RES 0402/1005 RF" 360.87,115.067 r90 top
R602_SPI_bridge_Main "0mR" "RES 0402/1005 RF" 96.464,524.866 r90 top (schematic designator R602)
R602_SPI_bridge_PCIe "0mR" "RES 0402/1005 RF" 142.687,380.477 r90 top (schematic designator R602)
R603_SPI_bridge_Main "0mR" "RES 0402/1005 RF" 104.364,527.063 r90 top (schematic designator R603)
R603_SPI_bridge_PCIe "0mR" "RES 0402/1005 RF" 138.857,380.427 r270 top (schematic designator R603)
R604_SPI_bridge_Main "0mR" "RES 0402/1005 RF" 98.611,525.374 r90 top (schematic designator R604)
R604_SPI_bridge_PCIe "0mR" "RES 0402/1005 RF" 251.666,251.289 r270 top (schematic designator R604)
R605_SPI_bridge_Main "0mR" "RES 0402/1005 RF" 106.51,527.571 r90 top (schematic designator R605)
R605_SPI_bridge_PCIe "0mR" "RES 0402/1005 RF" 255.537,251.289 r90 top (schematic designator R605)
R606_SPI_bridge_Main "0mR" "RES 0402/1005 RF" 94.61,524.396 r90 top (schematic designator R606)
R606_SPI_bridge_PCIe "0mR" "RES 0402/1005 RF" 252.94,251.289 r270 top (schematic designator R606)
R607 "10kR" "RES 0402/1005 RF" 238.355,286.758 r270 top
R608 "10kR" "RES 0402/1005 RF" 365.722,27.521 r0 top
R609 "10kR" "RES 0402/1005 RF" 361.074,26.67 r0 top
R610 "1.33kR" "RES 0402/1005 RF" 67.378,240.02 r90 top
R611 "1.33kR" "RES 0402/1005 RF" 67.113,230.597 r270 top
R612 "270R" "RES 0402/1005 RF" 59.342,241.891 r180 top
R613 "2.4R" "RES 1206/3216" 90.765,245.884 r270 top
R614 "270R" "RES 0402/1005 RF" 59.242,230.712 r180 top
R615 "10kR" "RES 0402/1005 RF" 60.606,234.739 r0 bottom
R616 "2.4R" "RES 1206/3216" 90.717,225.431 r90 top
R617 "PU5931FKMP70R004L" PU5931 137.735,295.465 r0 top
R618 "0mR" "RES 0402/1005 RF" 248.14,302.335 r90 top
R619 "1.91kR" "RES 0402/1005 RF" 69.532,182.474 r90 top
R620 "2kR" "RES 0402/1005 RF" 70.68,178.1 r180 top
R621 "147kR" "RES 0402/1005 RF" 65.137,183.819 r90 top
R622 "340kR" "RES 0402/1005 RF" 65.175,175.443 r270 top
R623 "1.43kR" "RES 0402/1005 RF" 63.12,175.457 r90 top
R624 "15kR" "RES 0402/1005 RF" 63.175,183.76 r270 top
R625 "1.4kR" "RES 0201/0603" 67.001,210.554 r270 top
R626 "200kR" "RES 0402/1005 RF" 59.997,210.161 r90 top
R627 "10.5kR" "RES 0402/1005 RF" 60.944,210.183 r270 top
R628 "750kR" "RES 0402/1005 RF" 69.132,200.233 r270 top
R629 "Resistance" "RES 0402/1005 RF" 68.656,206.964 r180 top
R630 "10kR" "RES 0402/1005 RF" 52.05,174.091 r180 top
R631 "5.9kR" "RES 0402/1005 RF" 61.938,202.273 r90 top
R632 "100kR" "RES 0402/1005 RF" 382.981,55.689 r0 top
R633 "100kR" "RES 0402/1005 RF" 387.312,55.689 r0 top
R634 "100kR" "RES 0402/1005 RF" 391.643,55.689 r0 top
R635 "10k" "RES 0402/1005 RF" 317.259,29.858 r90 top
R636 "0R" "RES 0402/1005 RF" 295.669,29.858 r90 top
R637 "0R" "RES 0402/1005 RF" 288.29,29.858 r90 top
R638 "0R" "RES 0402/1005 RF" 273.558,29.858 r90 top
R639 "0R" "RES 0402/1005 RF" 244.894,29.858 r90 top
R640 "0R" "RES 0402/1005 RF" 141.626,115.06 r90 top
R641 "0R" "RES 0402/1005 RF" 171.013,111.956 r90 top
R642 "0R" "RES 0402/1005 RF" 156.269,111.956 r90 top
R643 "0R" "RES 0402/1005 RF" 141.537,111.956 r90 top
R644 "9.1kR" "RES 0402/1005 RF" 370.04,50.47 r0 top
R645 "13kR" "RES 0402/1005 RF" 360.973,45.402 r0 top
R646 "100kR" "RES 0402/1005 RF" 361.391,50.47 r0 top
R647 "100kR" "RES 0402/1005 RF" 104.318,687.146 r0 top
R648 "2R" "RES 0402/1005 RF" 116.954,688.353 r0 top
R649 "10kR" "RES 0402/1005 RF" 125.209,683.146 r180 top
R650 "100MR" "RES 0402/1005 RF" 91.542,681.965 r0 top
R651 "10kR" "RES 0402/1005 RF" 88.655,670.623 r270 top
R652 "1MR" "RES 0402/1005 RF" 119.494,682.803 r90 top
R653 "20R" "RES 0402/1005 RF" 91.415,664.99 r270 top
R654 "100R" "RES 0402/1005 RF" 125.984,678.777 r180 top
R655 "10kR" "RES 0402/1005 RF" 119.418,678.967 r270 top
R656 "10kR" "RES 0402/1005 RF" 86.538,664.172 r270 top
R657 "100R" "RES 0402/1005 RF" 99.098,661.975 r270 top
R658 "10kR" "RES 0402/1005 RF" 92.9,661.314 r270 top
R659 "10kR" "RES 0402/1005 RF" 253.593,299.297 r90 top
R660 "10kR" "RES 0402/1005 RF" 239.704,286.758 r270 top
R661 "10kR" "RES 0402/1005 RF" 252.23,299.297 r90 top
R662 "10kR" "RES 0402/1005 RF" 245.102,286.758 r270 top
R663 "10kR" "RES 0402/1005 RF" 259.161,299.297 r90 top
R664 "10kR" "RES 0402/1005 RF" 241.054,286.758 r270 top
R665 "0mR" "RES 0402/1005 RF" 39.014,209.378 r270 top
R666 "12mR" "RES 1206/3216" 45.266,205.057 r90 top
R667 "24.9kR" "RES 0402/1005 RF" 42.528,202.265 r180 top
R668 "20kR" "RES 0402/1005 RF" 366.928,215.862 r90 top
R669 "0mR" "RES 0402/1005 RF" 38.887,200.381 r270 top
R670 "0mR" "RES 0402/1005 RF" 37.668,200.388 r270 top
R671 "1.87kR" "RES 0402/1005 RF" 218.007,323.545 r0 top
R672 "1.5kR" "RES 0402/1005 RF" 254.433,334.124 r0 top
R673 "1.87kR" "RES 0402/1005 RF" 241.467,334.124 r0 top
R674 "15kR" "RES 0402/1005 RF" 232.818,334.124 r0 top
R675 "0mR" "RES 0402/1005 RF" 366.883,133.883 r0 top
R676 "20kR" "RES 0402/1005 RF" 233.582,321.424 r0 top
R677 "95.3kR" "RES 0402/1005 RF" 44.716,192.483 r270 top
R678 "95.3kR" "RES 0402/1005 RF" 43.658,192.483 r270 top
R679 "95.3kR" "RES 0402/1005 RF" 45.775,195.483 r90 top
R680 "95.3kR" "RES 0402/1005 RF" 43.658,195.483 r90 top
R681 "24.9kR" "RES 0402/1005 RF" 51.568,194.019 r180 top
R682 "7.5kR" "RES 0402/1005 RF" 45.775,192.483 r90 top
R683 "4.87kR" "RES 0402/1005 RF" 42.6,192.483 r90 top
R684 "7.15kR" "RES 0402/1005 RF" 44.716,195.483 r270 top
R685 "5.9kR" "RES 0402/1005 RF" 42.6,195.483 r270 top
R686 "412kR" "RES 0402/1005 RF" 56.27,215.062 r90 top
R687 "57.6kR" "RES 0402/1005 RF" 61.953,210.719 r270 top
R688 "0mR" "RES 0402/1005 RF" 249.503,302.335 r90 top
R689 "20kR" "RES 0402/1005 RF" 160.795,347.612 r90 top
R690 "100kR" "RES 0402/1005 RF" 159.652,347.612 r90 top
R691 "20kR" "RES 0402/1005 RF" 151.692,347.358 r0 top
R692 "0R" "RES 0402/1005 RF" 360.883,130.988 r90 top
R693 "0mR" "RES 0402/1005 RF" 12.006,532.943 r90 top
R694 "1kR" "RES 0402/1005 RF" 231.723,323.635 r90 top
R695 "100R" "RES 0402/1005 RF" 165.024,277.812 r90 top
R696 "0mR" "RES 0402/1005 RF" 377.025,142.354 r90 top
R697 "0mR" "RES 0402/1005 RF" 441.414,62.446 r90 top
R698 "0mR" "RES 0402/1005 RF" 434.048,62.446 r90 top
R699 "0mR" "RES 0402/1005 RF" 426.682,62.446 r90 top
R700 "0mR" "RES 0402/1005 RF" 419.316,62.446 r90 top
R701 "0mR" "RES 0402/1005 RF" 412.458,62.446 r90 top
R702 "0mR" "RES 0402/1005 RF" 405.092,62.446 r90 top
R703 "0mR" "RES 0402/1005 RF" 419.329,81.082 r90 top
R704 "0mR" "RES 0402/1005 RF" 390.347,62.446 r90 top
R705 "0mR" "RES 0402/1005 RF" 409.715,71.298 r90 top
R706 "0mR" "RES 0402/1005 RF" 411.112,71.698 r90 top
R707 "0mR" "RES 0402/1005 RF" 368.249,62.446 r90 top
R708 "0mR" "RES 0402/1005 RF" 360.883,62.446 r90 top
R709 "2.2kR" "RES 0402/1005 RF" 110.217,285.162 r270 bottom
R710 "10kR" "RES 0402/1005 RF" 586.168,116.672 r90 top
R711 "0mR" "RES 0402/1005 RF" 587.4,116.634 r90 top
R712 "0mR" "RES 0402/1005 RF" 583.946,116.154 r90 top
R713 "0mR" "RES 0402/1005 RF" 581.851,116.484 r90 top
R714 "2.2kR" "RES 0402/1005 RF" 581.063,121.219 r90 top
R715 "10kR" "RES 0402/1005 RF" 360.807,108.489 r90 top
R716 "261R" "RES 0402/1005 RF" 389.585,93.218 r90 top
R717 "261R" "RES 0402/1005 RF" 382.473,93.218 r90 top
R718 "261R" "RES 0402/1005 RF" 375.361,93.218 r90 top
R719 "261R" "RES 0402/1005 RF" 368.249,93.218 r90 top
R720 "261R" "RES 0402/1005 RF" 360.883,93.218 r90 top
R721 "10k" "RES 0402/1005 RF" 310.401,29.858 r90 top
R722 "0R" "RES 0402/1005 RF" 280.924,29.858 r90 top
R723 "0R" "RES 0402/1005 RF" 252.26,29.858 r90 top
R724 "0R" "RES 0402/1005 RF" 237.528,29.858 r90 top
R725 "0R" "RES 0402/1005 RF" 143.251,107.759 r90 top
R726 "0R" "RES 0402/1005 RF" 143.124,115.525 r90 top
R727 "0R" "RES 0402/1005 RF" 148.903,111.956 r90 top
R728 "0R" "RES 0402/1005 RF" 134.171,111.956 r90 top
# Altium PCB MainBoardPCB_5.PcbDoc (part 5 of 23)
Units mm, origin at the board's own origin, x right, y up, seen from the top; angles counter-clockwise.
Board outline 258.95 x 308.86 mm, 16 copper layers (L1, L2 (GND), L3 (Sign), L4 (GND), L5 (Sign), L6 (PWR/GND), L7(PWR/GND), L8 (Plane_GND), L9 (PWR/GND), L10 (PWR/GND), L11 (PWR/GND), L12 (Sign), L13 (GND), L14 (Sign), L15 (GND), L16), stack 2.502 mm thick; 2361 components, 1769 nets, 8410 pads, 3285 vias.
Unrouted connection lines stored in the file: 4635.

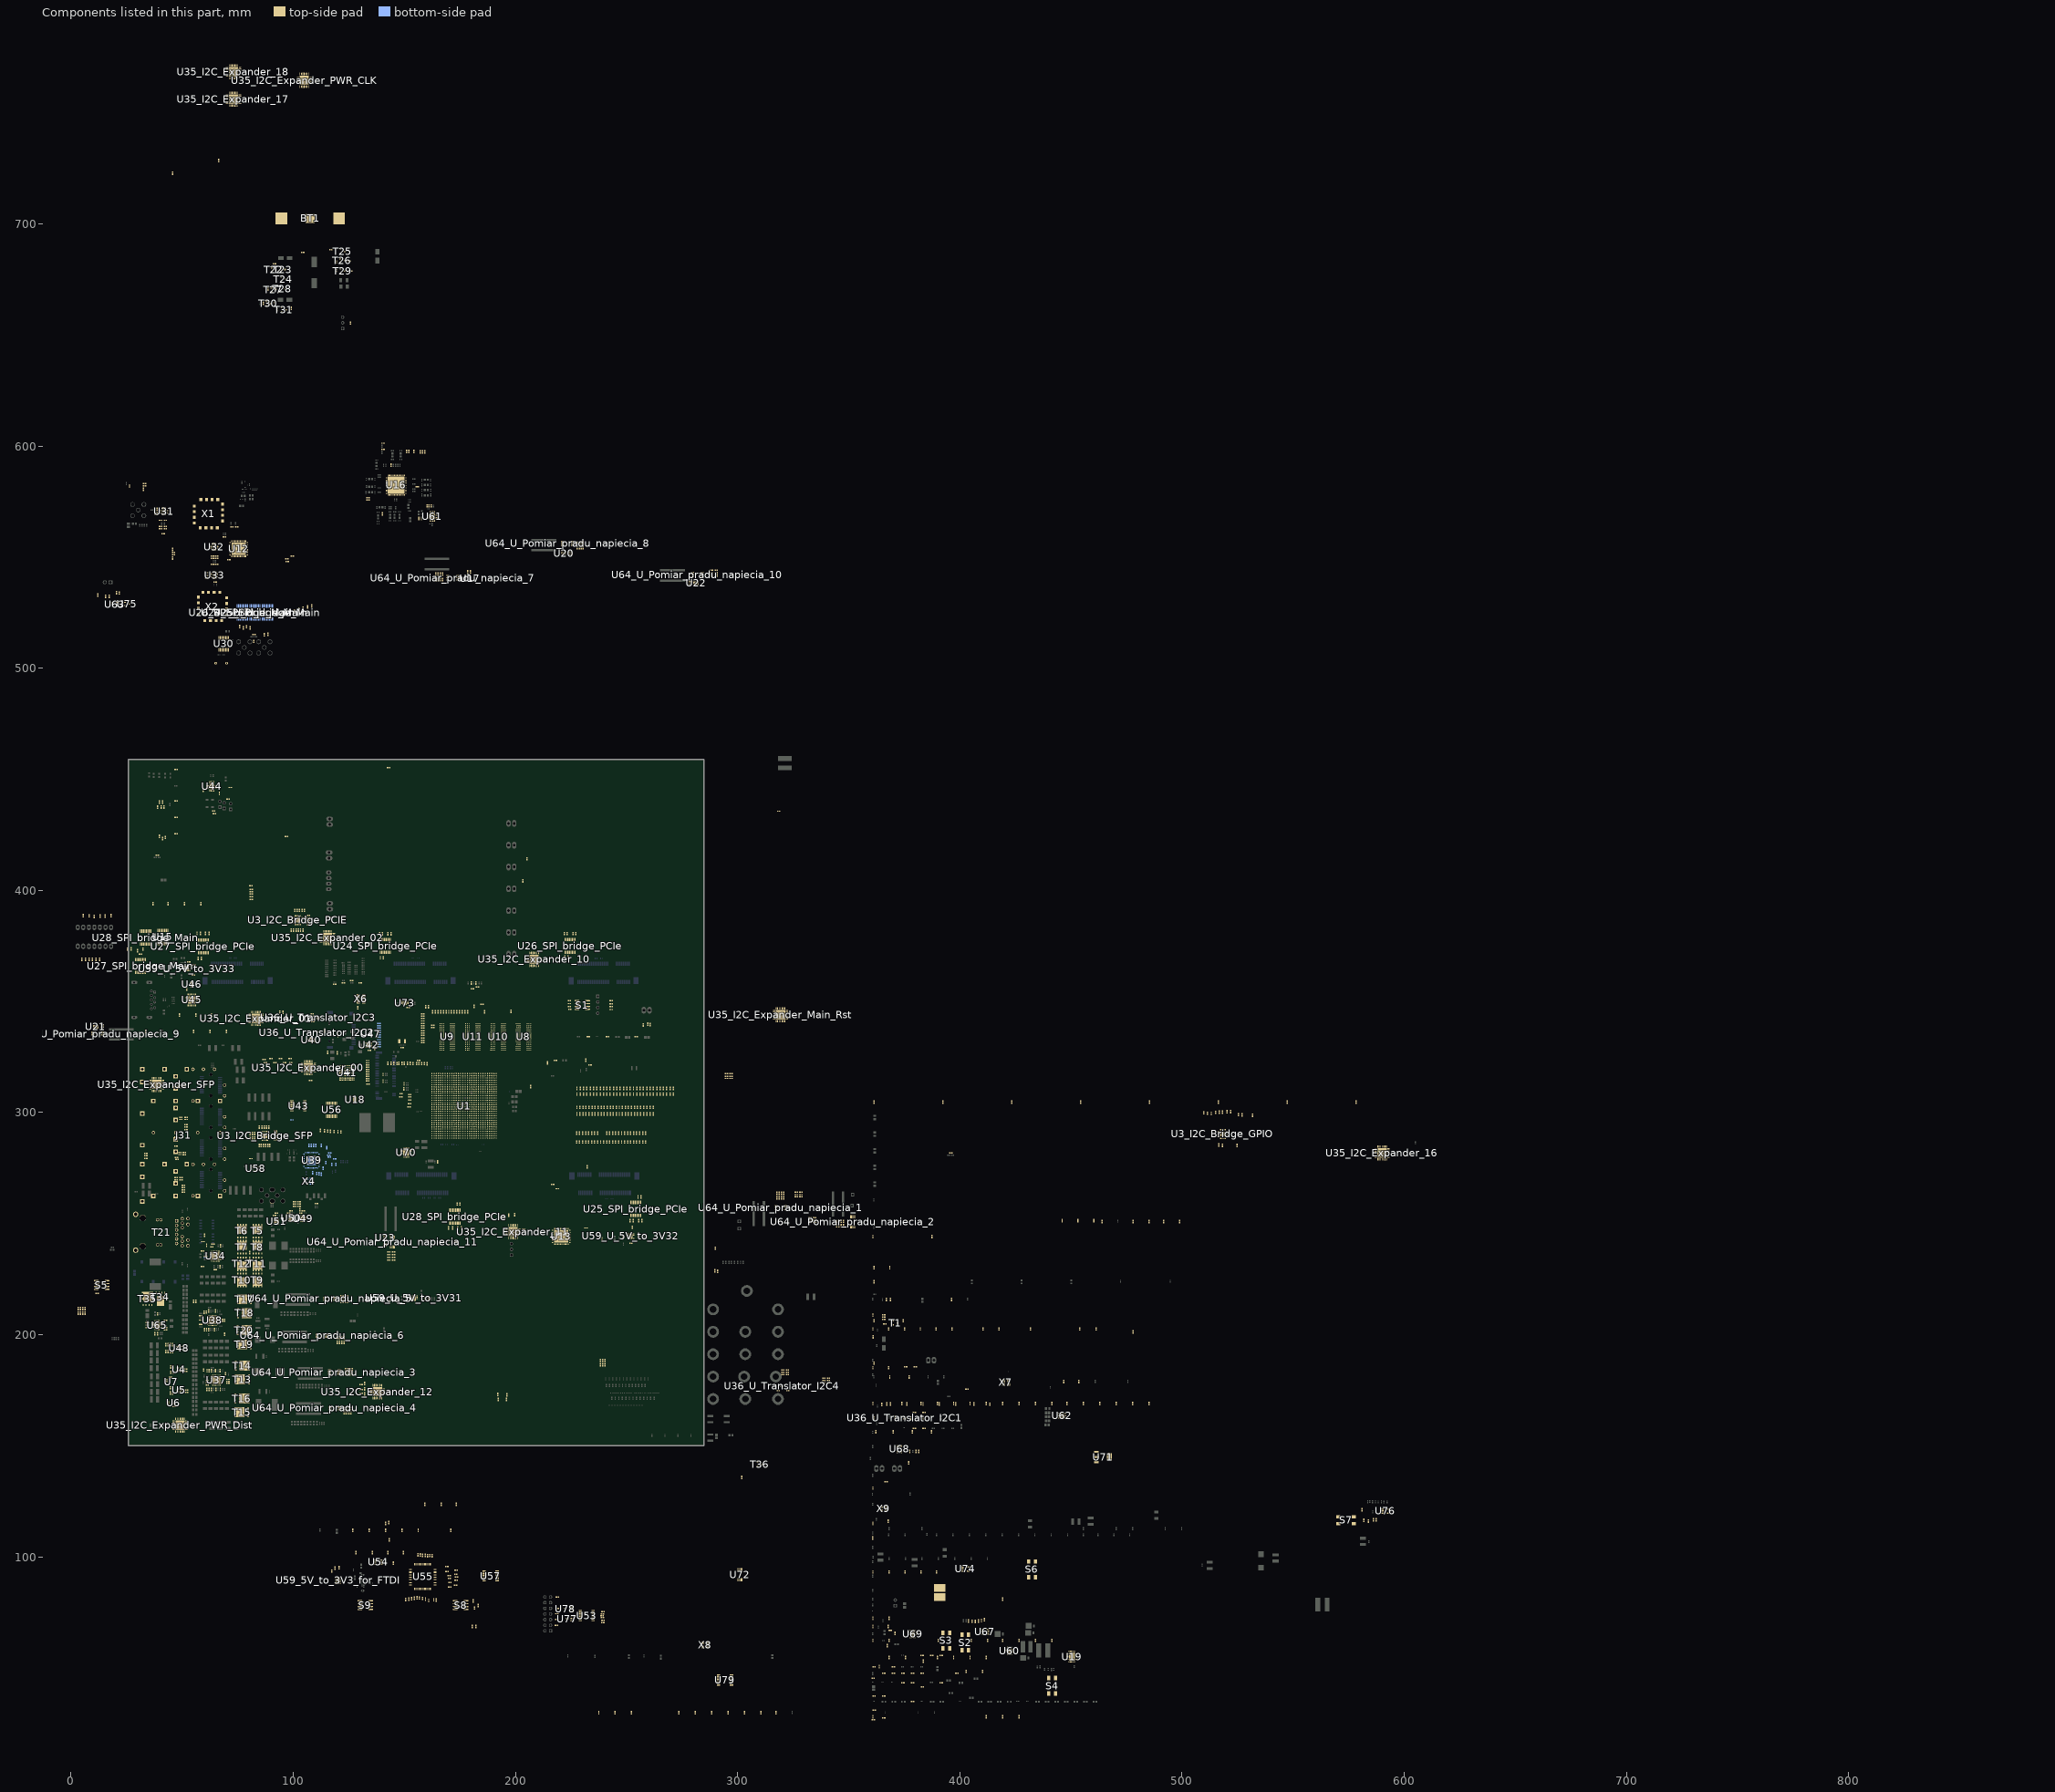
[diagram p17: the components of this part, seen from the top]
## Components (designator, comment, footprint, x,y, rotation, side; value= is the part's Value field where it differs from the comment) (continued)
R729 "0R" "RES 0402/1005 RF" 126.805,111.956 r90 top
R730 "4.7kR" "RES 0402/1005 RF" 218.904,81.991 r0 top
R731 "4.7kR" "RES 0402/1005 RF" 218.491,69.253 r0 top
R732 "4.7kR" "RES 0402/1005 RF" 218.611,71.844 r0 top
R733 "4.7kR" "RES 0402/1005 RF" 218.712,74.435 r0 top
R734 "4.7kR" "RES 0402/1005 RF" 218.814,76.797 r0 top
R735 "10kR" "RES 0402/1005 RF" 254.956,299.297 r90 top
R736 "10kR" "RES 0402/1005 RF" 246.452,286.758 r270 top
R737 "10kR" "RES 0402/1005 RF" 370.802,65.601 r90 top
R738 "0mR" "RES 0402/1005 RF" 405.447,71.056 r90 top
R739 "0mR" "RES 0402/1005 RF" 403.816,71.087 r90 top
R740 "0mR" "RES 0402/1005 RF" 406.883,70.948 r90 top
R741 "0mR" "RES 0402/1005 RF" 408.432,71.113 r90 top
R742 "0mR" "RES 0402/1005 RF" 368.249,72.314 r90 top
R743 "0mR" "RES 0402/1005 RF" 360.883,72.314 r90 top
R744 "0mR" "RES 0402/1005 RF" 253.593,302.335 r90 top
R745 "20kR" "RES 0402/1005 RF" 206.874,311.64 r270 top
R746 "10kR" "RES 0402/1005 RF" 404.584,168.974 r90 top
R747 "10kR" "RES 0402/1005 RF" 411.95,168.974 r90 top
R748 "10kR" "RES 0402/1005 RF" 419.316,168.974 r90 top
R749 "10kR" "RES 0402/1005 RF" 426.682,168.974 r90 top
R750 "10kR" "RES 0402/1005 RF" 434.048,168.974 r90 top
R751 "10kR" "RES 0402/1005 RF" 441.414,168.974 r90 top
R752 "10kR" "RES 0402/1005 RF" 448.272,168.974 r90 top
R753 "10kR" "RES 0402/1005 RF" 455.651,168.974 r90 top
R754 "10kR" "RES 0402/1005 RF" 463.017,168.974 r90 top
R755 "10kR" "RES 0402/1005 RF" 470.383,168.974 r90 top
R756 "10kR" "RES 0402/1005 RF" 477.749,168.974 r90 top
R757 "10kR" "RES 0402/1005 RF" 485.115,168.974 r90 top
R758 "0mR" "RES 0402/1005 RF" 397.205,168.974 r90 top
R759 "0mR" "RES 0402/1005 RF" 389.839,168.974 r90 top
R760 "0mR" "RES 0402/1005 RF" 382.473,168.974 r90 top
R761 "0mR" "RES 0402/1005 RF" 373.926,169.004 r90 top
R762 "0mR" "RES 0402/1005 RF" 367.081,168.846 r90 top
R763 "0mR" "RES 0402/1005 RF" 360.883,168.974 r90 top
R764 "WSHP28184L000FEA" WSHP2818 391.008,83.947 r90 top
R765 "10kR" "RES 0402/1005 RF" 250.866,299.297 r90 top
R766 "10kR" "RES 0402/1005 RF" 242.403,286.758 r270 top
R767 "0mR" "RES 0402/1005 RF" 252.23,302.335 r90 top
R768 "0mR" "RES 0402/1005 RF" 58.529,394.046 r90 top
R769 "0mR" "RES 0402/1005 RF" 51.151,394.046 r90 top
R770 "0mR" "RES 0402/1005 RF" 43.785,394.046 r90 top
R771 "0mR" "RES 0402/1005 RF" 36.927,394.046 r90 top
R772 "0mR" "RES 0402/1005 RF" 95.331,345.084 r90 top
R773 "0mR" "RES 0402/1005 RF" 94.055,345.231 r90 top
R774 "0mR" "RES 0402/1005 RF" 260.697,339.555 r90 top
R775 "0mR" "RES 0402/1005 RF" 259.613,339.758 r90 top
R776 "0mR" "RES 0402/1005 RF" 152.468,308.038 r180 top
R777 "0mR" "RES 0402/1005 RF" 152.468,306.984 r180 top
R778 "0mR" "RES 0402/1005 RF" 152.475,305.638 r180 top
R779 "0mR" "RES 0402/1005 RF" 152.425,304.013 r180 top
R780 "0mR" "RES 0402/1005 RF" 173.406,123.698 r90 top
R781 "0mR" "RES 0402/1005 RF" 166.548,123.698 r90 top
R782 "0mR" "RES 0402/1005 RF" 159.182,123.698 r90 top
R783 "0mR" "RES 0402/1005 RF" 125.854,655.307 r90 top
R784 "0mR" "RES 0402/1005 RF" 4.957,368.96 r270 top
R785 "0mR" "RES 0402/1005 RF" 6.537,368.96 r270 top
R786 "0mR" "RES 0402/1005 RF" 8.117,368.96 r270 top
R787 "0mR" "RES 0402/1005 RF" 9.697,368.96 r270 top
R788 "0mR" "RES 0402/1005 RF" 11.277,368.96 r270 top
R789 "0mR" "RES 0402/1005 RF" 12.856,368.96 r270 top
R790 "0mR" "RES 0402/1005 RF" 17.993,388.62 r90 top
R791 "0mR" "RES 0402/1005 RF" 15.44,388.41 r90 top
R792 "0mR" "RES 0402/1005 RF" 13.129,388.486 r90 top
R793 "0mR" "RES 0402/1005 RF" 10.525,388.257 r90 top
R794 "0mR" "RES 0402/1005 RF" 8.201,388.511 r90 top
R795 "0mR" "RES 0402/1005 RF" 5.559,388.575 r90 top
R796 "0mR" "RES 0402/1005 RF" 203.302,404.261 r270 top
R797 "0mR" "RES 0402/1005 RF" 133.629,312.864 r0 top
R798 "0mR" "RES 0402/1005 RF" 15.537,532.313 r90 top
R799 "0mR" "RES 0402/1005 RF" 17.137,532.359 r90 top
R800 "0mR" "RES 0402/1005 RF" 63.119,343.835 r90 top
R801 "0mR" "RES 0402/1005 RF" 56.261,343.835 r90 top
R802 "0mR" "RES 0402/1005 RF" 48.895,343.835 r90 top
R803 "0mR" "RES 0402/1005 RF" 478.041,201.308 r90 top
R804 "0mR" "RES 0402/1005 RF" 152.166,302.603 r0 top
R805 "0mR" "RES 0402/1005 RF" 205.296,414.185 r270 top
R806 "0mR" "RES 0402/1005 RF" 461.289,202.59 r90 top
R807 "0mR" "RES 0402/1005 RF" 453.923,202.59 r90 top
R808 "0mR" "RES 0402/1005 RF" 431.825,202.59 r90 top
R809 "0mR" "RES 0402/1005 RF" 417.538,202.59 r90 top
R810 "0mR" "RES 0402/1005 RF" 410.413,202.59 r90 top
R811 "0mR" "RES 0402/1005 RF" 396.443,202.59 r90 top
R812 "0mR" "RES 0402/1005 RF" 389.331,202.59 r90 top
R813 "0mR" "RES 0402/1005 RF" 382.219,202.59 r90 top
R814 "0mR" "RES 0402/1005 RF" 375.107,202.59 r90 top
R815 "0mR" "RES 0402/1005 RF" 367.995,202.59 r90 top
R816 "0mR" "RES 0402/1005 RF" 360.883,202.59 r90 top
R817 "10kR" "RES 0402/1005 RF" 256.32,299.297 r90 top
R818 "10kR" "RES 0402/1005 RF" 247.801,286.758 r270 top
R819 "0mR" "RES 0402/1005 RF" 259.161,302.335 r90 top
R820 "10kR" "RES 0402/1005 RF" 257.683,299.297 r90 top
R821 "10kR" "RES 0402/1005 RF" 249.151,286.758 r270 top
R822 "0mR" "RES 0402/1005 RF" 254.956,302.335 r90 top
R823 "10kR" "RES 0402/1005 RF" 228.908,286.758 r90 top
R824 "10kR" "RES 0402/1005 RF" 255.898,286.758 r270 top
R825 "100kR" "RES 0402/1005 RF" 383.451,162.522 r90 top
R826 "10kR" "RES 0402/1005 RF" 378.104,162.547 r90 top
R827 "10kR" "RES 0402/1005 RF" 370.764,162.916 r90 top
R828 "100kR" "RES 0402/1005 RF" 361.353,162.522 r90 top
R829 "0mR" "RES 0402/1005 RF" 413.525,168.738 r90 top
R830 "0mR" "RES 0402/1005 RF" 406.4,168.888 r90 top
R831 "0mR" "RES 0402/1005 RF" 398.183,168.758 r90 top
R832 "0mR" "RES 0402/1005 RF" 426.682,28.029 r90 top
R833 "0mR" "RES 0402/1005 RF" 419.316,28.029 r90 top
R834 "0mR" "RES 0402/1005 RF" 411.95,28.029 r90 top
R835 "10kR" "RES 0402/1005 RF" 130.607,173.721 r0 top
R836 "10kR" "RES 0402/1005 RF" 130.607,175.221 r0 top
R837 "20kR" "RES 0402/1005 RF" 132.195,173.321 r270 top
R838 "10kR" "RES 0402/1005 RF" 130.607,177.571 r0 top
R839 "20kR" "RES 0402/1005 RF" 132.195,175.671 r90 top
R840 "20kR" "RES 0402/1005 RF" 132.195,178.021 r90 top
R841 "0mR" "RES 0402/1005 RF" 360.883,28.029 r90 top
R842 "0mR" "RES 0402/1005 RF" 390.817,168.758 r90 top
R843 "0mR" "RES 0402/1005 RF" 383.451,168.758 r90 top
R844 "0mR" "RES 0402/1005 RF" 376.085,168.758 r90 top
R845 "0mR" "RES 0402/1005 RF" 368.719,168.758 r90 top
R846 "0mR" "RES 0402/1005 RF" 364.82,168.618 r90 top
R847 "10kR" "RES 0402/1005 RF" 262.116,299.297 r90 top
R848 "10kR" "RES 0402/1005 RF" 253.199,286.758 r270 top
R849 "10kR" "RES 0402/1005 RF" 227.559,286.758 r90 top
R850 "10kR" "RES 0402/1005 RF" 254.549,286.758 r270 top
R851 "0mR" "RES 0402/1005 RF" 250.866,302.335 r90 top
R852 "10kR" "RES 0402/1005 RF" 260.639,299.297 r90 top
R853 "10kR" "RES 0402/1005 RF" 250.5,286.758 r270 top
R854 "0mR" "RES 0402/1005 RF" 256.32,302.335 r90 top
R855 "10kR" "RES 0402/1005 RF" 230.258,286.758 r90 top
R856 "10kR" "RES 0402/1005 RF" 257.248,286.758 r270 top
R857 "0mR" "RES 0402/1005 RF" 257.683,302.335 r90 top
R858 "10kR" "RES 0402/1005 RF" 232.957,286.758 r90 top
R859 "10kR" "RES 0402/1005 RF" 258.597,286.758 r270 top
R860 "0mR" "RES 0402/1005 RF" 228.908,290.66 r90 top
R861 "10kR" "RES 0402/1005 RF" 235.656,286.758 r270 top
R862 "0mR" "RES 0402/1005 RF" 262.116,302.335 r90 top
R863 "0mR" "RES 0402/1005 RF" 227.559,290.66 r90 top
R864 "0mR" "RES 0402/1005 RF" 260.639,302.335 r90 top
R865 "0mR" "RES 0402/1005 RF" 230.258,290.66 r90 top
R866 "0mR" "RES 0402/1005 RF" 232.957,290.66 r90 top
R867 "0mR" "RES 0402/1005 RF" 235.656,290.66 r90 top
R868 "0mR" "RES 0402/1005 RF" 231.607,290.66 r90 top
R869 "0mR" "RES 0402/1005 RF" 237.005,290.66 r90 top
R870 "0mR" "RES 0402/1005 RF" 234.306,290.66 r90 top
R871 "0mR" "RES 0402/1005 RF" 251.85,290.66 r90 top
R872 "0mR" "RES 0402/1005 RF" 243.753,290.66 r90 top
R873 "0mR" "RES 0402/1005 RF" 45.745,722.775 r90 top
R874 "0mR" "RES 0402/1005 RF" 66.421,728.479 r90 top
R875 "0mR" "RES 0402/1005 RF" 245.102,290.66 r90 top
R876 "0mR" "RES 0402/1005 RF" 241.054,290.66 r90 top
R877 "0mR" "RES 0402/1005 RF" 246.452,290.66 r90 top
R878 "0mR" "RES 0402/1005 RF" 242.403,290.66 r90 top
R879 "0mR" "RES 0402/1005 RF" 247.801,290.66 r90 top
R880 "0mR" "RES 0402/1005 RF" 249.151,290.66 r90 top
R881 "0mR" "RES 0402/1005 RF" 255.898,290.66 r90 top
R882 "0mR" "RES 0402/1005 RF" 253.199,290.66 r90 top
R883 "0mR" "RES 0402/1005 RF" 254.549,290.66 r90 top
R884 "0mR" "RES 0402/1005 RF" 250.5,290.66 r90 top
R885 "0mR" "RES 0402/1005 RF" 257.248,290.66 r90 top
R886 "0mR" "RES 0402/1005 RF" 258.597,290.66 r90 top
R887_SPI_bridge_Main "0mR" "RES 0402/1005 RF" 102.51,526.593 r90 top (schematic designator R887)
R887_SPI_bridge_PCIe "0mR" "RES 0402/1005 RF" 256.891,251.289 r90 top (schematic designator R887)
R888_SPI_bridge_Main "0mR" "RES 0402/1005 RF" 77.563,518.193 r90 top (schematic designator R888)
R888_SPI_bridge_PCIe "0mR" "RES 0402/1005 RF" 227.265,380.53 r90 top (schematic designator R888)
R889_SPI_bridge_Main "0mR" "RES 0402/1005 RF" 80.704,518.163 r90 top (schematic designator R889)
R889_SPI_bridge_PCIe "0mR" "RES 0402/1005 RF" 223.24,380.53 r270 top (schematic designator R889)
R890_SPI_bridge_Main "0mR" "RES 0402/1005 RF" 75.857,518.668 r90 top (schematic designator R890)
R890_SPI_bridge_PCIe "0mR" "RES 0402/1005 RF" 225.92,380.53 r90 top (schematic designator R890)
R891_SPI_bridge_Main "0mR" "RES 0402/1005 RF" 78.998,518.638 r90 top (schematic designator R891)
R891_SPI_bridge_PCIe "0mR" "RES 0402/1005 RF" 221.965,380.53 r270 top (schematic designator R891)
R892_SPI_bridge_Main "0mR" "RES 0402/1005 RF" 547.243,304.749 r90 top (schematic designator R892)
R892_SPI_bridge_PCIe "0mR" "RES 0402/1005 RF" 62.238,380.682 r90 top (schematic designator R892)
R893_SPI_bridge_Main "0mR" "RES 0402/1005 RF" 578.218,304.749 r90 top (schematic designator R893)
R893_SPI_bridge_PCIe "0mR" "RES 0402/1005 RF" 58.229,380.683 r270 top (schematic designator R893)
R894_SPI_bridge_Main "0mR" "RES 0402/1005 RF" 485.28,304.749 r90 top (schematic designator R894)
R894_SPI_bridge_PCIe "0mR" "RES 0402/1005 RF" 60.563,380.683 r90 top (schematic designator R894)
R895_SPI_bridge_Main "0mR" "RES 0402/1005 RF" 516.255,304.749 r90 top (schematic designator R895)
R895_SPI_bridge_PCIe "0mR" "RES 0402/1005 RF" 56.733,380.682 r270 top (schematic designator R895)
R896_SPI_bridge_Main "0mR" "RES 0402/1005 RF" 423.316,304.749 r90 top (schematic designator R896)
R896_SPI_bridge_PCIe "0mR" "RES 0402/1005 RF" 169.964,248.006 r270 top (schematic designator R896)
R897_SPI_bridge_Main "0mR" "RES 0402/1005 RF" 454.292,304.749 r90 top (schematic designator R897)
R897_SPI_bridge_PCIe "0mR" "RES 0402/1005 RF" 173.938,248.006 r90 top (schematic designator R897)
R898_SPI_bridge_Main "0mR" "RES 0402/1005 RF" 361.353,304.749 r90 top (schematic designator R898)
R898_SPI_bridge_PCIe "0mR" "RES 0402/1005 RF" 171.673,248.006 r270 top (schematic designator R898)
R899_SPI_bridge_Main "0mR" "RES 0402/1005 RF" 392.328,304.749 r90 top (schematic designator R899)
R899_SPI_bridge_PCIe "0mR" "RES 0402/1005 RF" 175.706,248.006 r90 top (schematic designator R899)
R900 "0mR" "RES 0402/1005 RF" 301.89,135.776 r90 top
R901 "0mR" "RES 0402/1005 RF" 147.558,322.143 r270 top
R902 "0mR" "RES 0402/1005 RF" 142.681,322.181 r270 top
R903 "0mR" "RES 0402/1005 RF" 150.047,322.181 r270 top
R904 "0mR" "RES 0402/1005 RF" 145.274,322.087 r270 top
R905 "0mR" "RES 0402/1005 RF" 152.652,322.087 r270 top
R906 "0mR" "RES 0402/1005 RF" 148.995,322.11 r270 top
R907 "0mR" "RES 0402/1005 RF" 144.118,322.148 r270 top
R908 "0mR" "RES 0402/1005 RF" 151.484,322.148 r270 top
R909 "0mR" "RES 0402/1005 RF" 146.71,322.054 r270 top
R910 "0mR" "RES 0402/1005 RF" 153.822,322.054 r270 top
R911 "0mR" "RES 0402/1005 RF" 377.495,147.536 r270 top
R912 "0R" "RES 0402/1005 RF" 361.353,223.888 r90 top
R913 "0mR" "RES 0402/1005 RF" 155.51,322.041 r270 top
R914 "0mR" "RES 0402/1005 RF" 159.053,322.054 r270 top
R915 "0mR" "RES 0402/1005 RF" 156.666,322.028 r270 top
R916 "0mR" "RES 0402/1005 RF" 157.834,322.028 r270 top
R917 "0mR" "RES 0402/1005 RF" 160.249,322.016 r270 top
R918 "0mR" "RES 0402/1005 RF" 368.465,230.124 r90 top
R919 "0mR" "RES 0402/1005 RF" 361.353,230.124 r90 top
R920 "240R" "RES 0402/1005 RF" 361.353,187.198 r90 top
R921 "10kR" "RES 0402/1005 RF" 229.053,299.297 r90 top
R922 "10kR" "RES 0402/1005 RF" 256.128,308.301 r270 top
R923 "10kR" "RES 0402/1005 RF" 238.596,299.297 r90 top
R924 "10kR" "RES 0402/1005 RF" 257.625,308.301 r270 top
R925 "10kR" "RES 0402/1005 RF" 263.613,308.301 r90 top
R926 "10kR" "RES 0402/1005 RF" 253.134,308.301 r270 top
R927 "10kR" "RES 0402/1005 RF" 237.233,299.297 r90 top
R928 "10kR" "RES 0402/1005 RF" 254.631,308.301 r270 top
R929 "10kR" "RES 0402/1005 RF" 266.607,308.301 r90 top
R930 "10kR" "RES 0402/1005 RF" 251.637,308.301 r270 top
R931 "10kR" "RES 0402/1005 RF" 265.11,308.301 r90 top
R932 "10kR" "RES 0402/1005 RF" 250.14,308.301 r270 top
R933 "10kR" "RES 0402/1005 RF" 271.098,308.301 r90 top
R934 "10kR" "RES 0402/1005 RF" 227.686,308.301 r270 top
R935 "10kR" "RES 0402/1005 RF" 268.104,308.301 r90 top
R936 "10kR" "RES 0402/1005 RF" 229.183,308.301 r270 top
R937 "10kR" "RES 0402/1005 RF" 269.601,308.301 r90 top
R938 "10kR" "RES 0402/1005 RF" 227.69,299.297 r270 top
R939 "10kR" "RES 0402/1005 RF" 262.116,308.301 r90 top
R940 "10kR" "RES 0402/1005 RF" 241.159,308.301 r270 top
R941 "10kR" "RES 0402/1005 RF" 260.619,308.301 r90 top
R942 "10kR" "RES 0402/1005 RF" 245.649,308.301 r270 top
R943 "10kR" "RES 0402/1005 RF" 259.122,308.301 r90 top
R944 "10kR" "RES 0402/1005 RF" 238.165,308.301 r270 top
R945 "10kR" "RES 0402/1005 RF" 234.506,299.297 r90 top
R946 "10kR" "RES 0402/1005 RF" 235.171,308.301 r270 top
R947 "10kR" "RES 0402/1005 RF" 235.87,299.297 r90 top
R948 "10kR" "RES 0402/1005 RF" 236.668,308.301 r270 top
R949 "10kR" "RES 0402/1005 RF" 233.143,299.297 r90 top
R950 "10kR" "RES 0402/1005 RF" 239.662,308.301 r270 top
R951 "10kR" "RES 0402/1005 RF" 244.05,299.297 r90 top
R952 "10kR" "RES 0402/1005 RF" 233.674,308.301 r270 top
R953 "10kR" "RES 0402/1005 RF" 230.416,299.297 r90 top
R954 "10kR" "RES 0402/1005 RF" 230.68,308.301 r270 top
R955 "10kR" "RES 0402/1005 RF" 231.78,299.297 r90 top
R956 "10kR" "RES 0402/1005 RF" 232.177,308.301 r270 top
R957 "10kR" "RES 0402/1005 RF" 244.153,308.301 r90 top
R958 "10kR" "RES 0402/1005 RF" 247.146,308.301 r270 top
R959 "10kR" "RES 0402/1005 RF" 242.656,308.301 r90 top
R960 "10kR" "RES 0402/1005 RF" 248.643,308.301 r270 top
R961 "0mR" "RES 0402/1005 RF" 229.053,302.335 r90 top
R962 "0mR" "RES 0402/1005 RF" 238.596,302.335 r90 top
R963 "0mR" "RES 0402/1005 RF" 263.613,310.913 r90 top
R964 "0mR" "RES 0402/1005 RF" 237.233,302.335 r90 top
R965 "0mR" "RES 0402/1005 RF" 266.607,310.913 r90 top
R966 "0mR" "RES 0402/1005 RF" 265.11,310.913 r90 top
R967 "0mR" "RES 0402/1005 RF" 271.098,310.913 r90 top
R968 "0mR" "RES 0402/1005 RF" 268.104,310.913 r90 top
R969 "0mR" "RES 0402/1005 RF" 269.601,310.913 r90 top
R970 "0mR" "RES 0402/1005 RF" 262.116,310.913 r90 top
R971 "0mR" "RES 0402/1005 RF" 260.619,310.913 r90 top
R972 "0mR" "RES 0402/1005 RF" 259.122,310.913 r90 top
R973 "0mR" "RES 0402/1005 RF" 234.506,302.335 r90 top
R974 "0mR" "RES 0402/1005 RF" 235.87,302.335 r90 top
R975 "0mR" "RES 0402/1005 RF" 233.143,302.335 r90 top
R976 "0mR" "RES 0402/1005 RF" 244.05,302.335 r90 top
R977 "0mR" "RES 0402/1005 RF" 230.416,302.335 r90 top
R978 "0mR" "RES 0402/1005 RF" 231.78,302.335 r90 top
R979 "0mR" "RES 0402/1005 RF" 244.152,310.913 r90 top
R980 "0mR" "RES 0402/1005 RF" 242.655,310.913 r90 top
R981 "0mR" "RES 0402/1005 RF" 256.128,310.913 r90 top
R982 "0mR" "RES 0402/1005 RF" 257.625,310.913 r90 top
R983 "0mR" "RES 0402/1005 RF" 253.134,310.913 r90 top
R984 "0mR" "RES 0402/1005 RF" 254.631,310.913 r90 top
R985 "0mR" "RES 0402/1005 RF" 251.637,310.913 r90 top
R986 "0mR" "RES 0402/1005 RF" 250.14,310.913 r90 top
R987 "0mR" "RES 0402/1005 RF" 227.686,310.913 r90 top
R988 "0mR" "RES 0402/1005 RF" 229.183,310.913 r90 top
R989 "0mR" "RES 0402/1005 RF" 227.69,302.335 r90 top
R990 "0mR" "RES 0402/1005 RF" 241.158,310.913 r90 top
R991 "0mR" "RES 0402/1005 RF" 245.649,310.913 r90 top
R992 "0mR" "RES 0402/1005 RF" 238.164,310.913 r90 top
R993 "0mR" "RES 0402/1005 RF" 235.17,310.913 r90 top
R994 "0mR" "RES 0402/1005 RF" 236.667,310.913 r90 top
R995 "0mR" "RES 0402/1005 RF" 239.661,310.913 r90 top
R996 "0mR" "RES 0402/1005 RF" 233.674,310.913 r90 top
R997 "0mR" "RES 0402/1005 RF" 230.68,310.913 r90 top
R998 "0mR" "RES 0402/1005 RF" 232.177,310.913 r90 top
R999 "0mR" "RES 0402/1005 RF" 247.146,310.913 r90 top
R1000 "0mR" "RES 0402/1005 RF" 248.643,310.913 r90 top
R1001 "0R" "RES 0402/1005 RF" 181.013,80.251 r90 top
R1002 "10kR" "RES 0402/1005 RF" 374.459,206.299 r90 top
R1003 "10kR" "RES 0402/1005 RF" 361.353,206.299 r90 top
R1004 "0R" "RES 0402/1005 RF" 114.109,291.808 r90 top
R1005 "0R" "RES 0402/1005 RF" 118.351,291.465 r90 top
R1006 "0R" "RES 0402/1005 RF" 163.246,80.707 r270 top
R1007 "0R" "RES 0402/1005 RF" 164.287,80.545 r270 top
R1008 "0R" "RES 0402/1005 RF" 170.439,86.462 r0 top
R1009 "0R" "RES 0402/1005 RF" 173.056,87.3 r0 top
R1010 "0R" "RES 0402/1005 RF" 170.332,90.424 r0 top
R1011 "0R" "RES 0402/1005 RF" 173.469,90.957 r0 top
R1012 "0R" "RES 0402/1005 RF" 170.289,91.63 r0 top
R1013 "0R" "RES 0402/1005 RF" 173.177,92.227 r0 top
R1014 "0R" "RES 0402/1005 RF" 169.215,93.447 r0 top
R1015 "0R" "RES 0402/1005 RF" 173.38,93.967 r0 top
R1016 "0R" "RES 0402/1005 RF" 161.523,100.597 r90 top
R1017 "0R" "RES 0402/1005 RF" 160.49,100.533 r90 top
R1018 "0R" "RES 0402/1005 RF" 159.436,100.698 r90 top
R1019 "0R" "RES 0402/1005 RF" 158.153,100.774 r90 top
R1020 "0R" "RES 0402/1005 RF" 157.226,100.876 r90 top
R1021 "0R" "RES 0402/1005 RF" 156.07,100.97 r90 top
R1022 "0R" "RES 0402/1005 RF" 378.625,156.286 r90 top
R1023 "0R" "RES 0402/1005 RF" 387.261,156.286 r90 top
R1024 "0R" "RES 0402/1005 RF" 362.166,156.388 r90 top
R1025 "0R" "RES 0402/1005 RF" 369.989,156.286 r90 top
R1026 "0R" "RES 0402/1005 RF" 239.451,75.374 r0 top
R1027 "0R" "RES 0402/1005 RF" 239.159,74.397 r0 top
R1028 "0R" "RES 0402/1005 RF" 239.001,73.558 r0 top
R1029 "0R" "RES 0402/1005 RF" 239.128,72.657 r0 top
R1030 "0R" "RES 0402/1005 RF" 150.685,80.861 r270 top
R1031 "0R" "RES 0402/1005 RF" 151.968,80.936 r270 top
R1032 "0R" "RES 0402/1005 RF" 153.327,81.204 r270 top
R1033 "0R" "RES 0402/1005 RF" 154.534,81.407 r270 top
R1034 "0R" "RES 0402/1005 RF" 155.702,81.559 r270 top
R1035 "0R" "RES 0402/1005 RF" 156.794,81.521 r270 top
R1036 "0R" "RES 0402/1005 RF" 158.267,81.318 r270 top
R1037 "0R" "RES 0402/1005 RF" 159.55,81.013 r270 top
R1038 "0R" "RES 0402/1005 RF" 160.985,80.429 r270 top
R1039 "0R" "RES 0402/1005 RF" 116.815,291.574 r90 top
R1040 "0R" "RES 0402/1005 RF" 121.539,291.266 r90 top
R1041 "0R" "RES 0402/1005 RF" 120.155,291.376 r90 top
R1042 "0R" "RES 0402/1005 RF" 115.519,291.663 r90 top
R1043 "0R" "RES 0402/1005 RF" 112.306,291.897 r90 top
R1044 "0R" "RES 0402/1005 RF" 170.523,88.417 r0 top
R1045 "0R" "RES 0402/1005 RF" 173.342,89.484 r0 top
R1046 "0R" "RES 0402/1005 RF" 169.151,95.618 r0 top
R1047 "0R" "RES 0402/1005 RF" 162.5,100.557 r90 top
R1048 "1kR" "RES 0402/1005 RF" 182.296,68.745 r90 top
R1049 "1kR" "RES 0402/1005 RF" 183.286,78.143 r90 top
R1050 "1kR" "RES 0402/1005 RF" 181.623,77.018 r90 top
R1051 "1kR" "RES 0402/1005 RF" 180.657,68.694 r90 top
R1052 "1kR" "RES 0402/1005 RF" 368.465,180.962 r90 top
R1053 "1kR" "RES 0402/1005 RF" 377.101,180.962 r90 top
S1 "Mode Switch" SO8_N 230.073,348.386 r180 top
S2 "430181038816" 430181038816 402.45,61.481 r90 top
S3 "430181038816" 430181038816 393.903,62.357 r90 top
S4 "430181038816" 430181038816 441.554,41.999 r90 top
S5 "Mode Switch" SO8_N 13.818,222.39 r0 top
S6 "430181038816" 430181038816 432.473,94.424 r90 top
S7 "430181038816" 430181038816 573.799,116.51 r180 top
S8 "Mode Switch" SO8_N 175.362,78.321 r0 top
S9 "Mode Switch" SO8_N 132.448,78.321 r0 top
T1 "SI2342DS-T1-GE3" SI2342DS-T1-GE3 371.018,205.334 r0 top
T5 "BSC080N03LSG" BSC080N03LS 83.977,246.623 r90 top
T6 "BSC080N03LSG" BSC080N03LS 76.977,246.623 r90 top locked
T7 "BSC030N03LS-G" BSC030N03LS 76.977,239.389 r90 top
T8 "BSC030N03LS-G" BSC030N03LS 83.977,239.389 r90 top
T9 "BSC080N03LSG" BSC080N03LS 83.977,224.601 r270 top
T10 "BSC080N03LSG" BSC080N03LS 76.983,224.601 r270 top
T11 "BSC030N03LS-G" BSC030N03LS 83.977,231.864 r270 top
T12 "BSC030N03LS-G" BSC030N03LS 76.977,231.864 r270 top
T13 "BSC080N03LSG" BSC080N03LS 77.142,179.908 r180 top
T14 "BSC030N03LS-G" BSC030N03LS 77.114,186.055 r0 top
T15 "BSC080N03LSG" BSC080N03LS 76.889,165.106 r180 top
T16 "BSC030N03LS-G" BSC030N03LS 76.91,171.285 r0 top
T17 "BSC080N03LSG" BSC080N03LS 78.098,215.984 r180 top
T18 "BSC030N03LS-G" BSC030N03LS 78.073,209.702 r0 top
T19 "BSC080N03LSG" BSC080N03LS 78.029,195.651 r180 top
T20 "BSC030N03LS-G" BSC030N03LS 77.974,202.057 r0 top
T21 "7499511440" 7499511440 37.922,246.126 r90 bottom
T22 "IRLML6401TRPBF" IRLML6401PbF 91.3,679.272 r0 top
T23 "IRLML6401TRPBF" IRLML6401PbF 95.377,679.348 r0 top
T24 "SI2342DS-T1-GE3" SI2342DS-T1-GE3 95.567,675.119 r0 top
T25 "SI2342DS-T1-GE3" SI2342DS-T1-GE3 122.212,687.603 r0 top
T26 "SI2342DS-T1-GE3" SI2342DS-T1-GE3 122.123,683.374 r0 top
T27 "IRLML6401TRPBF" IRLML6401PbF 91.186,670.357 r0 top
T28 "SI2342DS-T1-GE3" SI2342DS-T1-GE3 95.263,670.75 r0 top
T29 "SI2342DS-T1-GE3" SI2342DS-T1-GE3 122.212,678.739 r0 top
T30 "IRLML6401TRPBF" IRLML6401PbF 88.925,664.07 r0 top
T31 "SI2342DS-T1-GE3" SI2342DS-T1-GE3 95.758,661.34 r0 top
T34 "RJK0651DPB-00#J5" RJK0651DPB 40.282,216.141 r270 top
T35 "SIJ482DP-T1-GE3" SiJ482DP 34.455,216.179 r90 top
T36 "SI2342DS-T1-GE3" SI2342DS-T1-GE3 309.982,141.681 r0 top
TP1_I2C_Bridge_GPIO "TestPoint" TestPoint 875.03,180.556 r90 top (schematic designator TP1)
TP1_I2C_Bridge_PCIE "TestPoint" TestPoint 875.03,190.792 r90 top (schematic designator TP1)
TP1_I2C_Bridge_SFP "TestPoint" TestPoint 853.44,201.028 r90 top (schematic designator TP1)
TP2_I2C_Bridge_GPIO "TestPoint" TestPoint 845.566,180.556 r90 top (schematic designator TP2)
TP2_I2C_Bridge_PCIE "TestPoint" TestPoint 845.566,190.792 r90 top (schematic designator TP2)
TP2_I2C_Bridge_SFP "TestPoint" TestPoint 825.259,201.028 r90 top (schematic designator TP2)
TP3_I2C_Bridge_GPIO "TestPoint" TestPoint 816.115,180.556 r90 top (schematic designator TP3)
TP3_I2C_Bridge_PCIE "TestPoint" TestPoint 816.115,190.792 r90 top (schematic designator TP3)
TP3_I2C_Bridge_SFP "TestPoint" TestPoint 797.065,201.028 r90 top (schematic designator TP3)
TP4_I2C_Bridge_GPIO "TestPoint" TestPoint 786.651,180.556 r90 top (schematic designator TP4)
TP4_I2C_Bridge_PCIE "TestPoint" TestPoint 786.651,190.792 r90 top (schematic designator TP4)
TP4_I2C_Bridge_SFP "TestPoint" TestPoint 768.883,201.028 r90 top (schematic designator TP4)
TP5_I2C_Bridge_GPIO "TestPoint" TestPoint 757.199,180.556 r90 top (schematic designator TP5)
TP5_I2C_Bridge_PCIE "TestPoint" TestPoint 757.199,190.792 r90 top (schematic designator TP5)
TP5_I2C_Bridge_SFP "TestPoint" TestPoint 740.689,201.028 r90 top (schematic designator TP5)
TP6_I2C_Bridge_GPIO "TestPoint" TestPoint 727.748,180.556 r90 top (schematic designator TP6)
TP6_I2C_Bridge_PCIE "TestPoint" TestPoint 727.748,190.792 r90 top (schematic designator TP6)
TP6_I2C_Bridge_SFP "TestPoint" TestPoint 712.508,201.028 r90 top (schematic designator TP6)
TP7_I2C_Bridge_GPIO "TestPoint" TestPoint 516.725,180.556 r90 top (schematic designator TP7)
TP7_I2C_Bridge_PCIE "TestPoint" TestPoint 516.725,190.792 r90 top (schematic designator TP7)
TP7_I2C_Bridge_SFP "TestPoint" TestPoint 510.375,201.028 r90 top (schematic designator TP7)
TP8_I2C_Bridge_GPIO "TestPoint" TestPoint 698.284,180.556 r90 top (schematic designator TP8)
TP8_I2C_Bridge_PCIE "TestPoint" TestPoint 698.284,190.792 r90 top (schematic designator TP8)
TP8_I2C_Bridge_SFP "TestPoint" TestPoint 684.327,201.028 r90 top (schematic designator TP8)
TP9_I2C_Bridge_GPIO "TestPoint" TestPoint 668.833,180.556 r90 top (schematic designator TP9)
TP9_I2C_Bridge_PCIE "TestPoint" TestPoint 668.833,190.792 r90 top (schematic designator TP9)
TP9_I2C_Bridge_SFP "TestPoint" TestPoint 656.133,201.028 r90 top (schematic designator TP9)
TP10_I2C_Bridge_GPIO "TestPoint" TestPoint 638.111,180.556 r90 top (schematic designator TP10)
TP10_I2C_Bridge_PCIE "TestPoint" TestPoint 638.111,190.792 r90 top (schematic designator TP10)
TP10_I2C_Bridge_SFP "TestPoint" TestPoint 626.682,201.028 r90 top (schematic designator TP10)
TP11_I2C_Bridge_GPIO "TestPoint" TestPoint 607.631,180.556 r90 top (schematic designator TP11)
TP11_I2C_Bridge_PCIE "TestPoint" TestPoint 607.631,190.792 r90 top (schematic designator TP11)
TP11_I2C_Bridge_SFP "TestPoint" TestPoint 597.484,201.028 r90 top (schematic designator TP11)
TP12_I2C_Bridge_GPIO "TestPoint" TestPoint 576.91,180.556 r90 top (schematic designator TP12)
TP12_I2C_Bridge_PCIE "TestPoint" TestPoint 576.91,190.792 r90 top (schematic designator TP12)
TP12_I2C_Bridge_SFP "TestPoint" TestPoint 568.02,201.028 r90 top (schematic designator TP12)
TP13_I2C_Bridge_GPIO "TestPoint" TestPoint 546.189,180.556 r90 top (schematic designator TP13)
TP13_I2C_Bridge_PCIE "TestPoint" TestPoint 546.189,190.792 r90 top (schematic designator TP13)
TP13_I2C_Bridge_SFP "TestPoint" TestPoint 538.569,201.028 r90 top (schematic designator TP13)
TP14_I2C_Bridge_GPIO "TestPoint" TestPoint 486.004,180.556 r90 top (schematic designator TP14)
TP14_I2C_Bridge_PCIE "TestPoint" TestPoint 486.004,190.792 r90 top (schematic designator TP14)
TP14_I2C_Bridge_SFP "TestPoint" TestPoint 480.924,201.028 r90 top (schematic designator TP14)
TP15_I2C_Bridge_GPIO "TestPoint" TestPoint 455.282,180.556 r90 top (schematic designator TP15)
TP15_I2C_Bridge_PCIE "TestPoint" TestPoint 455.282,190.792 r90 top (schematic designator TP15)
TP15_I2C_Bridge_SFP "TestPoint" TestPoint 451.472,201.028 r90 top (schematic designator TP15)
TP16_I2C_Bridge_GPIO "TestPoint" TestPoint 424.548,180.556 r90 top (schematic designator TP16)
TP16_I2C_Bridge_PCIE "TestPoint" TestPoint 424.548,190.792 r90 top (schematic designator TP16)
TP16_I2C_Bridge_SFP "TestPoint" TestPoint 422.008,201.028 r90 top (schematic designator TP16)
TP17_I2C_Bridge_GPIO "TestPoint" TestPoint 393.827,180.556 r90 top (schematic designator TP17)
TP17_I2C_Bridge_PCIE "TestPoint" TestPoint 393.827,190.792 r90 top (schematic designator TP17)
TP17_I2C_Bridge_SFP "TestPoint" TestPoint 392.557,201.028 r90 top (schematic designator TP17)
TP18_I2C_Bridge_GPIO "TestPoint" TestPoint 363.106,180.556 r90 top (schematic designator TP18)
TP18_I2C_Bridge_PCIE "TestPoint" TestPoint 363.106,190.792 r90 top (schematic designator TP18)
TP18_I2C_Bridge_SFP "TestPoint" TestPoint 363.106,201.028 r90 top (schematic designator TP18)
TP19 "TestPoint" TestPoint 420.484,157.213 r0 top
TP20 "TestPoint" TestPoint 426.974,156.896 r0 top
TP21 "TestPoint" TestPoint 517.385,171.336 r0 top
TP22 "TestPoint" TestPoint 510.019,171.336 r0 top
TP23 "TestPoint" TestPoint 502.653,171.336 r0 top
TP24 "TestPoint" TestPoint 495.287,171.336 r0 top
TP25 "TestPoint" TestPoint 487.921,171.336 r0 top
TP26 "TestPoint" TestPoint 480.555,171.336 r0 top
TP27 "TestPoint" TestPoint 458.47,171.336 r0 top
TP28 "TestPoint" TestPoint 473.202,171.336 r0 top
TP29 "TestPoint" TestPoint 451.104,171.336 r0 top
TP30 "TestPoint" TestPoint 465.836,171.336 r0 top
TP31 "TestPoint" TestPoint 436.816,171.336 r0 top
TP32 "TestPoint" TestPoint 443.738,171.336 r0 top
TP33 "TestPoint" TestPoint 429.45,171.336 r0 top
TP34 "TestPoint" TestPoint 422.084,171.336 r0 top
TP35 "TestPoint" TestPoint 414.719,171.336 r0 top
TP36 "TestPoint" TestPoint 407.352,171.336 r0 top
TP37 "TestPoint" TestPoint 399.986,171.336 r0 top
TP38 "TestPoint" TestPoint 392.633,171.336 r0 top
TP39 "TestPoint" TestPoint 385.267,171.336 r0 top
TP40 "TestPoint" TestPoint 377.901,171.336 r0 top
TP41 "TestPoint" TestPoint 370.967,171.336 r0 top
TP42 "TestPoint" TestPoint 363.601,171.336 r0 top
TP43 "TestPoint" TestPoint 407.797,162.611 r0 top
TP44 "TestPoint" TestPoint 431.406,162.113 r0 top
TP45 "TestPoint" TestPoint 413.804,162.052 r0 top
TP46 "TestPoint" TestPoint 425.386,162.141 r0 top
TP47 "TestPoint" TestPoint 407.099,157.328 r0 top
TP48 "TestPoint" TestPoint 419.329,162.115 r0 top
TP49 "TestPoint" TestPoint 413.931,156.87 r0 top
TP50_SPI_bridge_Main "TestPoint" TestPoint 291.122,487.426 r0 top (schematic designator TP50)
TP50_SPI_bridge_PCIe "TestPoint" TestPoint 641.668,211.264 r90 top (schematic designator TP50)
TP51_SPI_bridge_Main "TestPoint" TestPoint 286.55,477.545 r0 top (schematic designator TP51)
TP51_SPI_bridge_PCIe "TestPoint" TestPoint 610.933,211.264 r90 top (schematic designator TP51)
TP52_SPI_bridge_Main "TestPoint" TestPoint 292.138,481.889 r0 top (schematic designator TP52)
TP52_SPI_bridge_PCIe "TestPoint" TestPoint 579.958,211.264 r90 top (schematic designator TP52)
TP53_SPI_bridge_Main "TestPoint" TestPoint 282.651,489.623 r0 top (schematic designator TP53)
TP53_SPI_bridge_PCIe "TestPoint" TestPoint 548.983,211.264 r90 top (schematic designator TP53)
TP54_SPI_bridge_Main "TestPoint" TestPoint 290.271,494.982 r0 top (schematic designator TP54)
TP54_SPI_bridge_PCIe "TestPoint" TestPoint 517.995,211.264 r90 top (schematic designator TP54)
TP55_SPI_bridge_Main "TestPoint" TestPoint 301.447,496.564 r0 top (schematic designator TP55)
TP55_SPI_bridge_PCIe "TestPoint" TestPoint 487.02,211.264 r90 top (schematic designator TP55)
TP56_SPI_bridge_Main "TestPoint" TestPoint 299.022,490.918 r0 top (schematic designator TP56)
TP56_SPI_bridge_PCIe "TestPoint" TestPoint 456.044,211.264 r90 top (schematic designator TP56)
TP57_SPI_bridge_Main "TestPoint" TestPoint 307.416,496.786 r0 top (schematic designator TP57)
TP57_SPI_bridge_PCIe "TestPoint" TestPoint 425.056,211.264 r90 top (schematic designator TP57)
TP58_SPI_bridge_Main "TestPoint" TestPoint 298.615,484.772 r0 top (schematic designator TP58)
TP58_SPI_bridge_PCIe "TestPoint" TestPoint 394.081,211.264 r90 top (schematic designator TP58)
TP59_SPI_bridge_Main "TestPoint" TestPoint 306.067,490.69 r0 top (schematic designator TP59)
TP59_SPI_bridge_PCIe "TestPoint" TestPoint 363.106,211.264 r90 top (schematic designator TP59)
TP60_U_Translator_I2C1 "TestPoint" TestPoint 304.775,485.33 r0 top (schematic designator TP60)
TP60_U_Translator_I2C2 "TestPoint" TestPoint 396.875,221.501 r90 top (schematic designator TP60)
TP60_U_Translator_I2C3 "TestPoint" TestPoint 313.512,496.341 r0 top (schematic designator TP60)
TP60_U_Translator_I2C4 "TestPoint" TestPoint 310.299,484.721 r0 top (schematic designator TP60)
TP61_U_Translator_I2C1 "TestPoint" TestPoint 282.88,494.703 r0 top (schematic designator TP61)
TP61_U_Translator_I2C2 "TestPoint" TestPoint 363.106,221.501 r90 top (schematic designator TP61)
TP61_U_Translator_I2C3 "TestPoint" TestPoint 291.516,475.577 r0 top (schematic designator TP61)
TP61_U_Translator_I2C4 "TestPoint" TestPoint 282.943,484.886 r0 top (schematic designator TP61)
U1 "FBVB900" "FBVB900 XX" 176.897,303.039 r90 top locked
U3_I2C_Bridge_GPIO "TCA9548" TCA9548 518.223,290.373 r90 top (schematic designator U3)
U3_I2C_Bridge_PCIE "TCA9548" TCA9548 102.07,386.613 r90 top (schematic designator U3)
U3_I2C_Bridge_SFP "TCA9548" TCA9548 87.351,289.514 r90 top (schematic designator U3)
U4 "TPS2121RUXT" TPS212x 48.71,184.321 r270 top
U5 "TPS2121RUXT" TPS212x 48.71,175 r270 top
U6 "FPF2895CUCX" FPF2895C-D 46.21,169.389 r90 top
U7 "FPF2895CUCX" FPF2895C-D 45.075,178.775 r0 top
U8 "MT40A512M16JY" MT40A512M16JY 203.657,334.06 r180 top locked
U9 "MT40A512M16JY" MT40A512M16JY 169.276,334.06 r180 top locked
U10 "MT40A512M16JY" MT40A512M16JY 192.197,334.06 r180 top locked
U11 "MT40A512M16JY" MT40A512M16JY 180.736,334.06 r180 top locked
U12 "LTC6952" LTC6952 75.502,553.714 r90 top
U13 "LTC6952" LTC6952 220.56,244.228 r90 top
U15 "SN74AXC4T774PWR" SN74AXC4T774PWR 41.295,378.993 r90 top
U16 "LMK05028" LMK05028 146.333,582.402 r90 top
U17 "FPF2895CUCX" FPF2895C-D 179.528,540.397 r0 top
U18 "FPF2895CUCX" FPF2895C-D 127.753,305.908 r180 top
U19 "LT3504EUFD#PBF" LT3504 450.431,55.143 r0 top
U20 "FPF2895CUCX" FPF2895C-D 221.847,551.77 r270 top
U21 "FPF2895CUCX" FPF2895C-D 11.167,338.579 r270 top
U22 "FPF2895CUCX" FPF2895C-D 281.268,538.267 r90 top
U23 "FPF2895CUCX" FPF2895C-D 141.373,243.742 r180 top
U24_SPI_bridge_Main "SN74AXC4T774PWR" SN74AXC4T774PWR 82.779,525.082 r90 bottom (schematic designator U24)
U24_SPI_bridge_PCIe "SN74AXC4T774PWR" SN74AXC4T774PWR 141.507,375.007 r270 top (schematic designator U24)
U25_SPI_bridge_Main "SN74AXC4T774PWR" SN74AXC4T774PWR 88.43,525.082 r90 bottom (schematic designator U25)
U25_SPI_bridge_PCIe "SN74AXC4T774PWR" SN74AXC4T774PWR 254.216,256.667 r90 top (schematic designator U25)
U26_SPI_bridge_Main "SN74AXC4T774PWR" SN74AXC4T774PWR 77.127,525.082 r90 bottom (schematic designator U26)
U26_SPI_bridge_PCIe "SN74AXC4T774PWR" SN74AXC4T774PWR 224.615,375.007 r270 top (schematic designator U26)
U27_SPI_bridge_Main "SN74AXC4T774PWR" SN74AXC4T774PWR 31.342,365.912 r90 top (schematic designator U27)
U27_SPI_bridge_PCIe "SN74AXC4T774PWR" SN74AXC4T774PWR 59.588,374.79 r270 top (schematic designator U27)
U28_SPI_bridge_Main "SN74AXC4T774PWR" SN74AXC4T774PWR 33.617,378.739 r90 top (schematic designator U28)
U28_SPI_bridge_PCIe "SN74AXC4T774PWR" SN74AXC4T774PWR 172.823,253.178 r90 top (schematic designator U28)
U30 "DAC1220" DAC1220 68.745,510.984 r90 top
U31 "SI53323-B-GM" SI53323-B-GM 41.835,570.628 r270 top
U32 "SI53323-B-GM" SI53323-B-GM 64.427,554.633 r0 top
U33 "CDCM1802RGTT" CDCM1802RGTT 64.558,541.848 r90 top
U34 "ADP1850ACPZ-R7" ADP1850 65.072,235.389 r0 top
U35_I2C_Expander_00 "MCP23017-E/ML" QFN-ML28_N 106.802,320.263 r90 top (schematic designator U35)
U35_I2C_Expander_01 "MCP23017-E/ML" QFN-ML28_N 83.369,342.397 r90 top (schematic designator U35)
U35_I2C_Expander_02 "MCP23017-E/ML" QFN-ML28_N 115.43,378.657 r90 top (schematic designator U35)
U35_I2C_Expander_10 "MCP23017-E/ML" QFN-ML28_N 208.43,368.94 r90 top (schematic designator U35)
U35_I2C_Expander_11 "MCP23017-E/ML" QFN-ML28_N 198.939,246.41 r90 top (schematic designator U35)
U35_I2C_Expander_12 "MCP23017-E/ML" QFN-ML28_N 137.858,174.371 r90 top (schematic designator U35)
U35_I2C_Expander_16 "MCP23017-E/ML" QFN-ML28_N 590.027,281.856 r90 top (schematic designator U35)
U35_I2C_Expander_17 "MCP23017-E/ML" QFN-ML28_N 73.148,756.103 r90 top (schematic designator U35)
U35_I2C_Expander_18 "MCP23017-E/ML" QFN-ML28_N 73.148,768.448 r90 top (schematic designator U35)
U35_I2C_Expander_Main_Rst "MCP23017-E/ML" QFN-ML28_N 319.335,343.972 r90 top (schematic designator U35)
U35_I2C_Expander_PWR_CLK "MCP23017-E/ML" QFN-ML28_N 104.965,764.603 r90 top (schematic designator U35)
U35_I2C_Expander_PWR_Dist "MCP23017-E/ML" QFN-ML28_N 49.093,159.303 r0 top (schematic designator U35)
U35_I2C_Expander_SFP "MCP23017-E/ML" QFN-ML28_N 38.544,312.649 r90 top (schematic designator U35)
U36_U_Translator_I2C1 "PCA9306" PCA9306 375.158,162.56 r90 top (schematic designator U36)
U36_U_Translator_I2C2 "PCA9306" PCA9306 110.627,335.941 r0 top (schematic designator U36)
U36_U_Translator_I2C3 "PCA9306" PCA9306 111.214,342.671 r90 top (schematic designator U36)
U36_U_Translator_I2C4 "PCA9306" PCA9306 319.885,176.957 r90 top (schematic designator U36)
U37 "ADP1850ACPZ-R7" ADP1850 65.425,179.567 r0 top
U38 "ADP1850ACPZ-R7" ADP1850 63.703,206.464 r0 top
U39 "DP83867ERGZT" DP83867E 108.299,278.525 r0 bottom
U40 "MCP1727T-ADJE/MF" MCP1727T-ADJE/MF 108.212,332.746 r0 top
U41 "MTFC8GAKAJCN-4MITTR" "MTFC8GAKAJCN-4M IT TR" 124.188,317.841 r270 top locked
U42 "MCP1727T-ADJE/MF" MCP1727T-ADJE/MF 133.976,330.435 r0 top
U43 "SN74AXC4T774PWR" SN74AXC4T774PWR 102.324,303.047 r180 top
U44 "MAX16025TE+T" MAX16025TE+T 63.42,446.853 r0 top
U45 "USB3320C-EZK-TR" USB3320 54.331,350.685 r0 top
U46 "FPF2895CUCX" FPF2895C-D 54.445,357.645 r0 top
U47 "IP4856CX25/CZ" IP4856CX25/C 134.729,335.404 r180 bottom locked
U48 "TPS2121RUXT" TPS212x 48.677,193.983 r270 top
U49 "MCP1727T-ADJE/MF" MCP1727T-ADJE/MF 104.495,252.348 r90 top
U50 "MCP1727T-ADJE/MF" MCP1727T-ADJE/MF 99.101,252.371 r90 top
U51 "MCP1727T-ADJE/MF" MCP1727T-ADJE/MF 92.569,251.063 r90 top
U53 "SN74AXC4T774PWR" SN74AXC4T774PWR 232.072,73.558 r0 top
U54 "93LC56BT-I/OT" 93LC56BT 138.273,97.638 r0 top
U55 "FT4232HL-REEL" FT4232HL 158.344,91.11 r0 top
U56 "SN74AXC4T774PWR" SN74AXC4T774PWR 117.335,301.231 r270 top
U57 "SN74AXC4T774PWR" SN74AXC4T774PWR 188.874,91.427 r0 top
U58 "ISM330DHCXTR" ISM330DHCXL 83.007,274.777 r0 top
U59_5V_to_3V3_for_FTDI "MCP1727T-ADJE/MF" MCP1727T-ADJE/MF 120.18,89.421 r90 top (schematic designator U59)
U59_U_5V_to_3V31 "MCP1727T-ADJE/MF" MCP1727T-ADJE/MF 154.362,216.491 r0 top (schematic designator U59)
U59_U_5V_to_3V32 "MCP1727T-ADJE/MF" MCP1727T-ADJE/MF 251.841,244.386 r180 top (schematic designator U59)
U59_U_5V_to_3V33 "MCP1727T-ADJE/MF" MCP1727T-ADJE/MF 52.146,364.82 r0 top (schematic designator U59)
U60 "ADP1741ACPZ-R7" ADP1752_1753/ADP1740_1741 422.354,57.672 r0 top
U61 "TPS7A8801RTJT" TPS7A88 162.589,568.332 r180 top
U62 "LT3042EDD#PBF" LT3042 446.027,163.522 r0 top
U63 "MAX3051EKA+T" "MAX3051EKA+T SOT23" 19.766,528.676 r0 top
U64_U_Pomiar_pradu_napiecia_1 "INA226AIDGSR" INA226 319.402,257.273 r0 top (schematic designator U64)
U64_U_Pomiar_pradu_napiecia_2 "INA226AIDGSR" INA226 351.752,250.85 r90 top (schematic designator U64)
U64_U_Pomiar_pradu_napiecia_3 "INA226AIDGSR" INA226 118.478,183.159 r180 top (schematic designator U64)
U64_U_Pomiar_pradu_napiecia_4 "INA226AIDGSR" INA226 118.681,167.127 r180 top (schematic designator U64)
U64_U_Pomiar_pradu_napiecia_5 "INA226AIDGSR" INA226 116.548,216.393 r180 top (schematic designator U64)
U64_U_Pomiar_pradu_napiecia_6 "INA226AIDGSR" INA226 113.005,199.771 r180 top (schematic designator U64)
U64_U_Pomiar_pradu_napiecia_7 "INA226AIDGSR" INA226 171.775,540.697 r0 top (schematic designator U64)
U64_U_Pomiar_pradu_napiecia_8 "INA226AIDGSR" INA226 223.444,556.142 r180 top (schematic designator U64)
U64_U_Pomiar_pradu_napiecia_9 "INA226AIDGSR" INA226 12.002,335.331 r0 top (schematic designator U64)
U64_U_Pomiar_pradu_napiecia_10 "INA226AIDGSR" INA226 281.823,542.12 r180 top (schematic designator U64)
U64_U_Pomiar_pradu_napiecia_11 "INA226AIDGSR" INA226 144.653,241.711 r90 top (schematic designator U64)
U65 "MAX17557ATP+" MAX17557 38.76,204.318 r90 top
U67 "LM3880MFE-1AF/NOPB" LM3880-Q1 411.353,66.332 r0 top
U68 "LM3880MFE-1AF/NOPB" LM3880-Q1 372.783,148.59 r90 top
U69 "ADP1741ACPZ-R7" ADP1752_1753/ADP1740_1741 378.732,65.251 r0 top
U70 "TPS7A8801RTJT" TPS7A88 150.914,282.003 r0 top
U71 "UA78M08CDCYR" UA78M 464.337,144.958 r0 top
U72 "INA226AIDGSR" INA226 301.028,91.973 r90 top
U73 "ST1L08SPUR" ST1L08 150.244,349.234 r0 top
U74 "SN74LVC1G08DBVR" SN74LVC1G08DBVR 402.488,94.602 r0 top
U75 "ESDCAN02-2BWY" ESDCAN02-2BWY 25.287,528.904 r0 top
U76 "SN74LVC1G08DBVR" SN74LVC1G08DBVR 591.375,120.65 r0 top
U77 "NC7WZ07FHX" NC7WZ07FHX 223.279,72.022 r180 top
U78 "NC7WZ07FHX" NC7WZ07FHX 222.415,76.556 r0 top
U79 "SN74AXC4T774PWR" SN74AXC4T774PWR 294.373,44.602 r0 top
X1 "OSC CRO 2000-2000 MHZ SMD .5X.5" CVCO55CW 55.537,563.182 r0 top
X2 "OSC VCO 490-540MHZ SMD .5X.5\"" CVCO55CW 70.015,521.399 r90 top
X3 "2.4576MHz" Crystal 70.069,502.221 r180 top
X4 "FA-23825.0000MB-C3" FA-23825.0000MB-C3 107.086,269.076 r180 bottom
X5 "32.768kHz" FC-135R/FC-135 149.073,332.105 r0 top
X6 "510CCA50M0000BAG" Si510 130.504,351.091 r270 top
X7 "TSX-322524.0000MF15X-AC6" "TSX-3225 24.0000MF15X-AC6" 420.789,178.498 r0 top
X8 "ECS-120-8-33-RWY-TR" ECS-120-8-33-RWY-TR 285.42,60.389 r0 top
X9 "SIT1602BI-12-33E-48.000000G" SiT1602B 365.762,121.718 r0 top

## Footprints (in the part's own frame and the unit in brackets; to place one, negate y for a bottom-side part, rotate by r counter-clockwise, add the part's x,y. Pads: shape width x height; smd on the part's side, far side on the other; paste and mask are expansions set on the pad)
93LC56BT [mm] "SOT-23-6, 6-Leads, Body 2,90x1,55mm, Pitch 0,95mm, IPC High Density"
  rect 1.1x0.6 smd: 1(-1.4,0.95) 2(-1.4,0) 3(-1.4,-0.95) 4(1.4,-0.95) 5(1.4,0) 6(1.4,0.95)
  silkscreen extent -1.52,-1.55 0.5,1.92, body extent -1.35,-1.55 1.35,1.55, height 1.45
2007132 [mm] "SFP Connector"
  rect 2x2 hole 1.05: SH1(-2.5,-5) SH1(0,0) SH2(8.575,-5) SH3(14.25,-5) SH4(0,10) SH5(5.675,10) SH6(11.075,10) SH7(14.25,15) SH8(0,20) SH9(0,30) SH10(14.25,5) SH13(19.925,10) SH14(25.325,10) SH17(22.825,-5) SH20(34.175,10) SH21(39.575,10) SH22(42.75,10) SH23(42.75,0) SH24(37.075,-5) SH25(42.75,20) SH26(42.75,30) SH29(57,15) SH30(57,5) SH31(57,-5) SH32(48.425,10) SH33(53.825,10) SH34(51.325,-5)
  round 1.458 hole 0.95: SH11(14.25,22.5) SH12(14.25,27.5) SH15(28.5,10) SH16(28.5,0) SH18(28.5,20) SH19(28.5,30) SH27(57,27.5) SH28(57,22.5) SH35(0,17.8) SH36(2.325,32.1) SH37(7.125,32.1) SH38(14.25,17.8) SH39(16.575,32.1) SH40(21.375,32.1) SH41(30.825,32.1) SH42(35.625,32.1) SH43(45.075,32.1) SH44(49.875,32.1) SH45(42.75,17.8) SH46(57,17.8)
  Keep-Out Layer region: -1.001,17.3 58,17.3 58,-9.514 -1.001,-9.514
  Keep-Out Layer region: 13.255,31.8 15.25,31.8 15.25,17.306 13.255,17.306
  Keep-Out Layer region: 27.544,31.8 29.5,31.8 29.5,17.328 27.544,17.328
  Keep-Out Layer region: 41.817,31.8 43.75,31.8 43.75,17.328 41.817,17.328
  Keep-Out Layer region: -1.002,31.8 1,31.8 1,17.334 -1.002,17.334
  Keep-Out Layer region: 56.018,31.8 58,31.8 58,17.305 56.018,17.305
  Keep-Out Layer region: -1.001,32.8 3.305,32.8 3.305,31.833 -1.001,31.833
  Keep-Out Layer region: 53.775,32.8 58,32.8 58,31.848 53.775,31.848
  Keep-Out Layer region: 11.207,32.8 17.31,32.8 17.31,31.849 11.207,31.849
  Keep-Out Layer region: 25.472,32.8 31.56,32.8 31.56,31.84 25.472,31.84
  Keep-Out Layer region: 39.72,32.8 45.81,32.8 45.81,31.824 39.72,31.824
  Keep-Out Layer region: -1.002,17.3 58,17.3 58,-9.517 -1.002,-9.517
  Keep-Out Layer region: 13.269,31.8 15.25,31.8 15.25,17.324 13.269,17.324
  Keep-Out Layer region: 27.554,31.8 29.5,31.8 29.5,17.334 27.554,17.334
  Keep-Out Layer region: 41.815,31.8 43.75,31.8 43.75,17.327 41.815,17.327
  Keep-Out Layer region: -1.002,31.8 1,31.8 1,17.328 -1.002,17.328
  Keep-Out Layer region: 56.056,31.8 58,31.8 58,17.317 56.056,17.317
  Keep-Out Layer region: -1,32.8 3.305,32.8 3.305,31.812 -1,31.812
  Keep-Out Layer region: 53.789,32.8 58,32.8 58,31.855 53.789,31.855
  Keep-Out Layer region: 11.205,32.8 17.31,32.8 17.31,31.843 11.205,31.843
  Keep-Out Layer region: 25.485,32.8 31.56,32.8 31.56,31.857 25.485,31.857
  Keep-Out Layer region: 39.745,32.8 45.81,32.8 45.81,31.844 39.745,31.844
  Keep-Out Layer region: -1.001,17.3 58,17.3 58,-9.514 -1.001,-9.514
  Keep-Out Layer region: 13.255,31.8 15.25,31.8 15.25,17.306 13.255,17.306
  Keep-Out Layer region: 27.544,31.8 29.5,31.8 29.5,17.328 27.544,17.328
  Keep-Out Layer region: 41.817,31.8 43.75,31.8 43.75,17.328 41.817,17.328
  Keep-Out Layer region: -1.002,31.8 1,31.8 1,17.334 -1.002,17.334
  Keep-Out Layer region: 56.018,31.8 58,31.8 58,17.305 56.018,17.305
  Keep-Out Layer region: -1.001,32.8 3.305,32.8 3.305,31.833 -1.001,31.833
  Keep-Out Layer region: 53.775,32.8 58,32.8 58,31.848 53.775,31.848
  Keep-Out Layer region: 11.207,32.8 17.31,32.8 17.31,31.849 11.207,31.849
  Keep-Out Layer region: 25.472,32.8 31.56,32.8 31.56,31.84 25.472,31.84
  Keep-Out Layer region: 39.72,32.8 45.81,32.8 45.81,31.824 39.72,31.824
  Keep-Out Layer region: -1.002,17.3 58,17.3 58,-9.517 -1.002,-9.517
  Keep-Out Layer region: 13.269,31.8 15.25,31.8 15.25,17.324 13.269,17.324
  Keep-Out Layer region: 27.554,31.8 29.5,31.8 29.5,17.334 27.554,17.334
  Keep-Out Layer region: 41.815,31.8 43.75,31.8 43.75,17.327 41.815,17.327
  Keep-Out Layer region: -1.002,31.8 1,31.8 1,17.328 -1.002,17.328
  Keep-Out Layer region: 56.056,31.8 58,31.8 58,17.317 56.056,17.317
  Keep-Out Layer region: -1,32.8 3.305,32.8 3.305,31.812 -1,31.812
  Keep-Out Layer region: 53.789,32.8 58,32.8 58,31.855 53.789,31.855
  Keep-Out Layer region: 11.205,32.8 17.31,32.8 17.31,31.843 11.205,31.843
  Keep-Out Layer region: 25.485,32.8 31.56,32.8 31.56,31.857 25.485,31.857
  Keep-Out Layer region: 39.745,32.8 45.81,32.8 45.81,31.844 39.745,31.844
  Keep-Out Layer region: -1.001,17.3 58,17.3 58,-9.514 -1.001,-9.514
  Keep-Out Layer region: 13.255,31.8 15.25,31.8 15.25,17.306 13.255,17.306
  Keep-Out Layer region: 27.544,31.8 29.5,31.8 29.5,17.328 27.544,17.328
  Keep-Out Layer region: 41.817,31.8 43.75,31.8 43.75,17.328 41.817,17.328
  Keep-Out Layer region: -1.002,31.8 1,31.8 1,17.334 -1.002,17.334
  Keep-Out Layer region: 56.018,31.8 58,31.8 58,17.305 56.018,17.305
  Keep-Out Layer region: -1.001,32.8 3.305,32.8 3.305,31.833 -1.001,31.833
  Keep-Out Layer region: 53.775,32.8 58,32.8 58,31.848 53.775,31.848
  Keep-Out Layer region: 11.207,32.8 17.31,32.8 17.31,31.849 11.207,31.849
  Keep-Out Layer region: 25.472,32.8 31.56,32.8 31.56,31.84 25.472,31.84
  Keep-Out Layer region: 39.72,32.8 45.81,32.8 45.81,31.824 39.72,31.824
  Keep-Out Layer region: -1.002,17.3 58,17.3 58,-9.517 -1.002,-9.517
  Keep-Out Layer region: 13.269,31.8 15.25,31.8 15.25,17.324 13.269,17.324
  Keep-Out Layer region: 27.554,31.8 29.5,31.8 29.5,17.334 27.554,17.334
  Keep-Out Layer region: 41.815,31.8 43.75,31.8 43.75,17.327 41.815,17.327
  Keep-Out Layer region: -1.002,31.8 1,31.8 1,17.328 -1.002,17.328
  Keep-Out Layer region: 56.056,31.8 58,31.8 58,17.317 56.056,17.317
  Keep-Out Layer region: -1,32.8 3.305,32.8 3.305,31.812 -1,31.812
  Keep-Out Layer region: 53.789,32.8 58,32.8 58,31.855 53.789,31.855
  Keep-Out Layer region: 11.205,32.8 17.31,32.8 17.31,31.843 11.205,31.843
  Keep-Out Layer region: 25.485,32.8 31.56,32.8 31.56,31.857 25.485,31.857
  Keep-Out Layer region: 39.745,32.8 45.81,32.8 45.81,31.844 39.745,31.844
  silkscreen extent 0,-9.5 57.25,32.57, body extent -0.97,-16.49 58.08,32.49, height 10.62
79523141 [mm] "Battery Holder, Battery Type: 2016,2020,2025,2032"
  rect 5.2x5.2 smd: 1(-12.95,0) 1(12.95,0)
  rect 4x4 smd: 2(0,0)
  silkscreen extent -10.55,-10.5 10.55,9.3, body extent -15.25,-10.5 15.25,9.3, height 4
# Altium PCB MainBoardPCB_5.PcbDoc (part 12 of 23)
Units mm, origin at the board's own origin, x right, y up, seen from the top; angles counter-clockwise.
Board outline 258.95 x 308.86 mm, 16 copper layers (L1, L2 (GND), L3 (Sign), L4 (GND), L5 (Sign), L6 (PWR/GND), L7(PWR/GND), L8 (Plane_GND), L9 (PWR/GND), L10 (PWR/GND), L11 (PWR/GND), L12 (Sign), L13 (GND), L14 (Sign), L15 (GND), L16), stack 2.502 mm thick; 2361 components, 1769 nets, 8410 pads, 3285 vias.
Unrouted connection lines stored in the file: 4635.

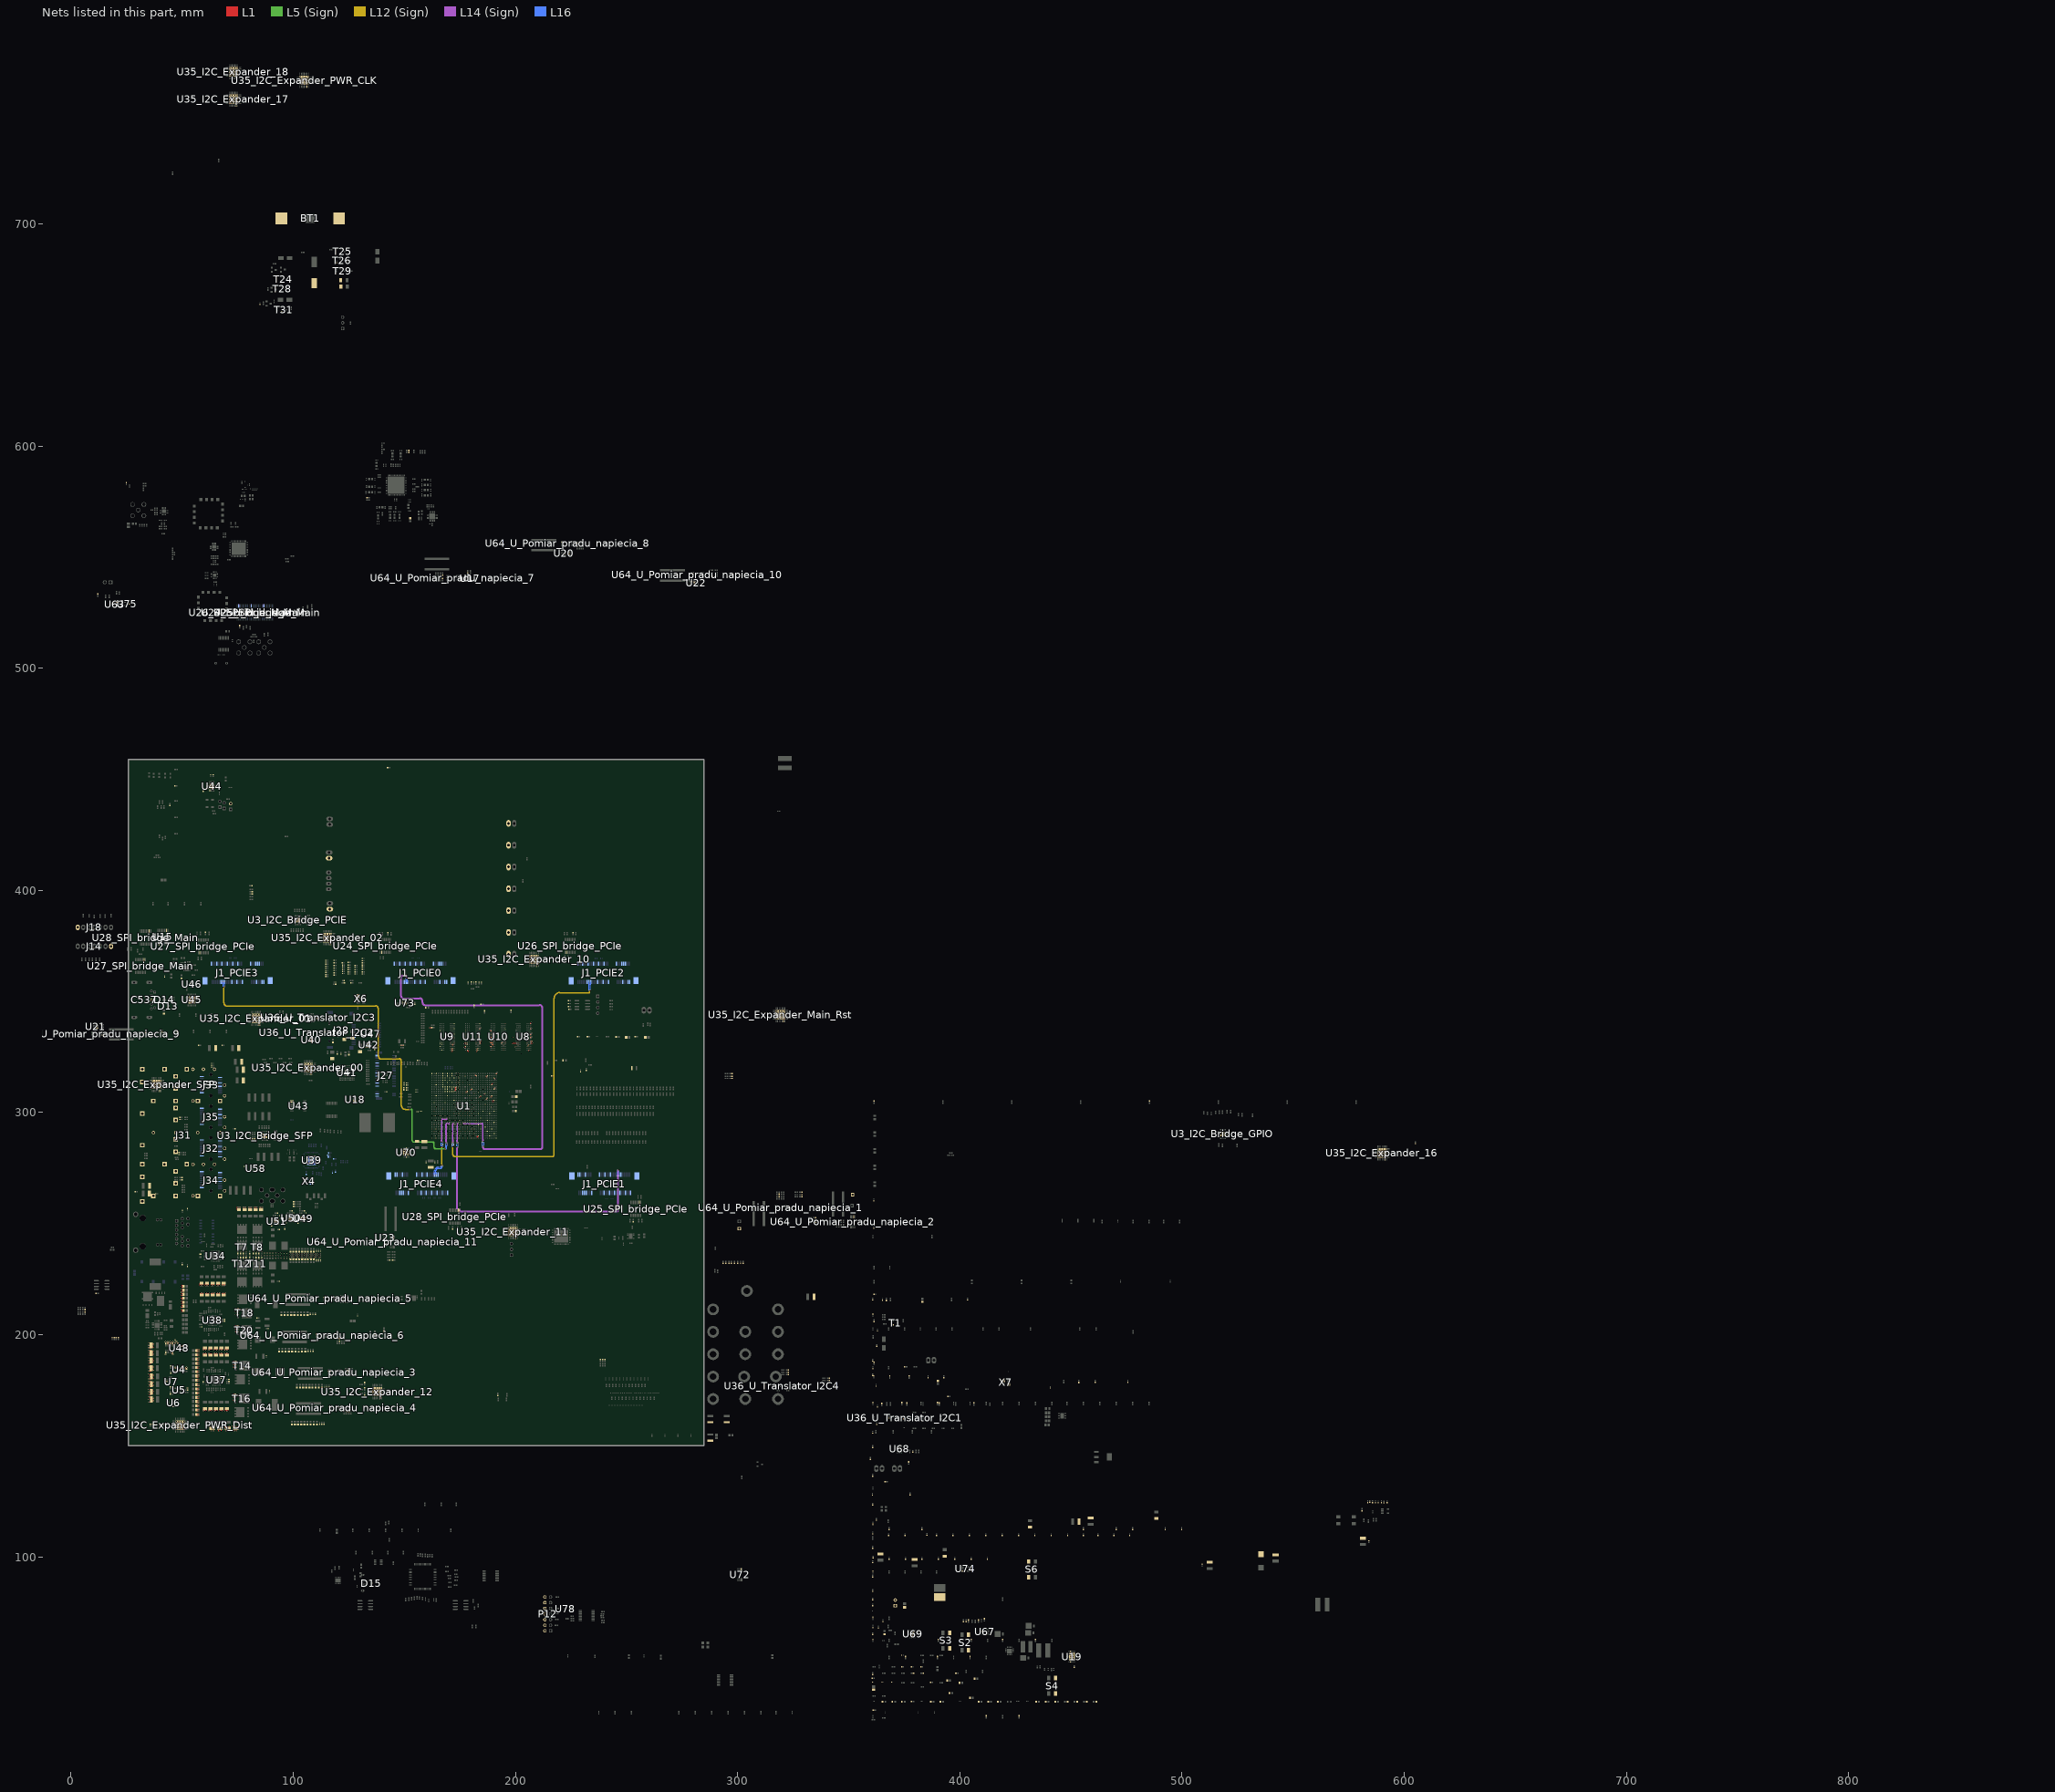
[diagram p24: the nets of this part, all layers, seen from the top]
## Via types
v1: diameter 0.5, hole 0.2, L1 to L16, tented both sides, 1212 vias
v2: diameter 0.5, hole 0.2, L1 to L16, 494 vias
v3: diameter 0.5/0.35/0.35/0.35/0.35/0.35/0.35/0.35/0.35/0.35/0.35/0.35/0.35/0.35/0.35/0.5 (per signal layer), hole 0.15, L1 to L16, tented both sides, 463 vias
v4: diameter 0.35/0/0.35 (per signal layer), hole 0.127, L1 to L3 (Sign), tented both sides, 283 vias
v5: diameter 0.5/0.35/0.35/0.35/0.35/0.35/0.35/0.35/0.35/0.35/0.35/0.35/0.35/0.35/0.35/0.5 (per signal layer), hole 0.2, L1 to L16, tented both sides, 222 vias
v6: diameter 0.8, hole 0.4, L1 to L16, tented both sides, 168 vias
v7: diameter 2.54, hole 1.02, L1 to L16, 113 vias
v8: diameter 1.4, hole 0.5, L1 to L16, tented both sides, 80 vias
v9: diameter 0.5/0/0.5 (per signal layer), hole 0.2, L14 (Sign) to L16, tented both sides, 52 vias
v10: diameter 0.35, hole 0.127, L1 to L2 (GND), tented both sides, 36 vias
v11: diameter 0.35/0/0.35 (per signal layer), hole 0.127, L1 to L3 (Sign), 19 vias
v12: diameter 0.35, hole 0.127, L1 to L16, tented both sides, 16 vias
v13: diameter 0.4, hole 0.2, L1 to L16, 16 vias
v14: diameter 0.25, hole 0.2, L1 to L16, 16 vias
v15: diameter 0.3, hole 0.2, L1 to L16, 15 vias
v16: diameter 0.45, hole 0.15, L1 to L16, 12 vias
v17: diameter 0.5/0.35/0.35/0.35/0.35/0.35/0.35/0.35/0.35/0.35/0.35/0.35/0.35/0.35/0.35/0.45 (per signal layer), hole 0.15, L1 to L16, tented both sides, 10 vias
v18: diameter 0.2/0/0.2 (per signal layer), hole 0.1, L1 to L3 (Sign), tented both sides, 9 vias
v19: diameter 0.4, hole 0.1, L1 to L16, 7 vias
v20: diameter 1.15, hole 1.15, L1 to L16, 6 vias
v21: diameter 1.65, hole 1.65, L1 to L16, 6 vias
v22: diameter 0.5, hole 0.2, L3 (Sign) to L6 (PWR/GND), tented both sides, 6 vias
v23: diameter 0.35/0/0.35 (per signal layer), hole 0.127, L14 (Sign) to L16, tented both sides, 5 vias
v24: diameter 0.2, hole 0.1, L1 to L16, 4 vias
v25: diameter 0.4, hole 0.2, L1 to L16, tented both sides, 2 vias
v26: diameter 0.4, hole 0.15, L1 to L16, 2 vias
v27: diameter 0.5/0.35/0.35/0.35/0.35/0.35/0.35/0.35/0.35/0.35/0.35/0.35/0.35/0.35/0.35/0.5 (per signal layer), hole 0.15, L1 to L16, 2 vias
v28: diameter 0.35, hole 0.127, L3 (Sign) to L6 (PWR/GND), tented both sides, 2 vias
v29: diameter 5.5, hole 3.5, L1 to L16, 1 vias
v30: diameter 0.5/0.35/0.35/0.35/0.35/0.35/0.35/0.35/0.35/0.35/0.35/0.35/0.35/0.35/0.35/0.5 (per signal layer), hole 0.2, L1 to L16, 1 vias
v31: diameter 0.35/0.35/0.35 (per signal layer), hole 0.127, L1 to L3 (Sign), tented both sides, 1 vias
v32: diameter 0.45/0/0.45 (per signal layer), hole 0.15, L1 to L3 (Sign), tented both sides, 1 vias
v33: diameter 0.45/0/0.45 (per signal layer), hole 0.2, L14 (Sign) to L16, tented both sides, 1 vias
v34: diameter 0.35, hole 0.127, L2 (GND) to L3 (Sign), 1 vias
v35: diameter 0.35, hole 0.127, L1 to L2 (GND), 1 vias

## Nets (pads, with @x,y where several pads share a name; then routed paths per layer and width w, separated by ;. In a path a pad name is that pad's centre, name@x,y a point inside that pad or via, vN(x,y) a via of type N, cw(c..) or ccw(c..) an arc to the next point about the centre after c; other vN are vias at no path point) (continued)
B503_Ground: B1.2 BT1.1 C1.1 C2.1 C3.1 C4.2 C5.2 C6.2 C7.2 C8.1 C9.1 C10.1 C11.1 C12.2 C13.2 C14.2 C15.2 C16.1 C17.1 C18.1 C19.1 C20.1 C21.1 C22.1 C23.1 C24.1 C25.1 C26.1 C27.1 C28.1 C29.1 C30.1 C31.1 C32.1 C33.1 C34.1 C35.1 C37.1 C38.2 C39.1 C40.2 C207.1 C208.2 C209.1 C210.2 C211.1 C212.2 C213.1 C214.2 C215.1 C216.2 C217.1 C218.2 C219.2 C220.2 C221.2 C222.2 C223.1 C224.1 C225.1 C226.1 C227.1 C228.1 C229.1 C230.1 C231.1 C232.1 C233.1 C234.1 C235.1 C236.1 C237.1 C238.1 C239.1 C240.1 C241.1 C242.1 C243.2 C244.2 C245.2 C246.2 C247.1 C248.1 C249.1 C250.1 C251.1 C252.1 C253.1 C254.1 C255.1 C256.1 C257.1 C258.1 C259.1 C260.1 C261.1 C262.1 C263.1 C264.1 C265.1 C266.1 C303_I2C_Bridge_GPIO.1 C303_I2C_Bridge_PCIE.1 C303_I2C_Bridge_SFP.1 C304.2 C305.2 C306.2 C307.2 C308.1 C309_U_Pomiar_pradu_napiecia_1.1 C309_U_Pomiar_pradu_napiecia_2.1 C309_U_Pomiar_pradu_napiecia_3.1 C309_U_Pomiar_pradu_napiecia_4.1 C309_U_Pomiar_pradu_napiecia_5.1 C309_U_Pomiar_pradu_napiecia_6.1 C309_U_Pomiar_pradu_napiecia_7.1 C309_U_Pomiar_pradu_napiecia_8.1 C309_U_Pomiar_pradu_napiecia_9.1 C309_U_Pomiar_pradu_napiecia_10.1 C309_U_Pomiar_pradu_napiecia_11.1 C310.1 C311_I2C_Expander_00.1 C311_I2C_Expander_01.1 C311_I2C_Expander_02.1 C311_I2C_Expander_10.1 C311_I2C_Expander_11.1 C311_I2C_Expander_12.1 C311_I2C_Expander_16.1 C311_I2C_Expander_17.1 C311_I2C_Expander_18.1 C311_I2C_Expander_Main_Rst.1 C311_I2C_Expander_PWR_CLK.1 C311_I2C_Expander_PWR_Dist.1 C311_I2C_Expander_SFP.1 C312.1 C313.1 C314.2 C331.1 C332.1 C347.1 C348.1 C352.1 C353.1 C354.1 C355.1 C358.1 C359.1 C360.1 C361.1 C362.1 C363.1 C364.1 C365.1 C366.1 C367.1 C368.1 C369.1 C370.1 C371.1 C372.1 C373.1 C374.1 C375.1 C376.1 C377.1 C378.1 C379.1 C380.1 C381.1 C382.1 C383.1 C384.1 C385.1 C386.1 C387.1 C388.1 C391.2 C392.1 C396.1 C397.2 C399.2 C400.1 C401.1 C402.1 C403.1 C404.1 C405.1 C406.1 C407.1 C408.1 C409.1 C410.1 C411.1 C412.1 C413.1 C414.1 C415.1 C416.1 C417.1 C418.1 C419.1 C420.1 C421.1 C422.1 C423.1 C424.1 C425.1 C426.1 C427.1 C428.1 C429.1 C432.2 C433.1 C437.1 C438.2 C440.2 C441.1 C442.1 C443.1 C444.1 C445.1 C446.1 C447.1 C448.1 C449.1 C450.1 C451.1 C452.1 C453.1 C454.1 C455.1 C456.1 C457.1 C458.1 C459.1 C460.1 C461.1 C462.1 C463.1 C464.1 C465.1 C466.1 C467.1 C468.1 C469.1 C470.1 C471.1 C472.1 C473.1 C474.1 C475.1 C476.1 C480.1 C481.1 C485.1 C486.1 C487.1 C488.1 C489.1 C490.1 C491.1 C492.1 C493.1 C494.1 C495.1 C496.1 C497.1 C498.1 C499.1 C500.1 C501.1 C502.1 C503.1 C504.1 C505.1 C506.1 C507.1 C508.1 C509.1 C510.1 C511.1 C512.1 C513.1 C514.1 C515.1 C516.1 C517.1 C518.1 C519.1 C520.1 C521.1 C522.1 C523.1 C524.1 C531.2 C532.2 C533.2 C534.2 C535.1 C536.1 C537.7 C538.1 C539.1 C544.1 C545.1 C546.1 C547.1 C550.1 C551.1 C552.1 C553.1 C554.1 C555.1 C561.1 C562.1 C585.1 C586.1 C587.1 C606.1 C607.1 C609.1 C610.1 C611.1 C613.1 C614.1 C615.1 C617.1 C618.1 C619.1 C620.1 C621.1 C622.1 C623.1 C624.1 C625.1 C626.1 C631.1 C632.1 C633.1 C636.1 C637.1 C638.1 C645.1 C646.1 C654.1 C655.2 C656.2 C657.2 C672.1 C674.1 C675.1 C676.1 C678.1 C679.1 C680.1 C705.1 C707.1 C708.1 C709.1 C711.1 C712.1 C719.1 C720.1 C721.1 C722.1 C723.1 C731.1 C732.1 C733.1 C734.1 C735.1 C736.1 C737.1 C738.2 C739.2 C740.1 C741.1 C742.2 C743.1 C744.1 C745.1 C746.1 C747.2 C748.1 C749.1 C750.1 C751.2 C752.1 C753.2 C754.1 C755.1 C756.1 C757.2 C758.1 C759.1 C760.2 C761.1 C762.2 C763.1 C764.2 C765.1 C766.2 C767.2 C768.2 C769.2 C770.1 C771.1 C772.1 C773.1 C774.1 C775.1 C776.1 C777.1 C778.1 C779.1 C780.1 C781.1 C782.1 C783.1 C784.1 C785.1 C786.1 C787.1 C788.1 C789.1 C792.1 D13.3 D14.3 D14.8 D15.3 FB27.1 FB28.2 FB29.1 FB35.1 FB36.1 FB39.1 FB41.1 J1_PCIE0.1 J1_PCIE0.3 J1_PCIE0.6 J1_PCIE0.8 J1_PCIE0.9 J1_PCIE0.10 J1_PCIE0.16 J1_PCIE0.17 J1_PCIE0.22 J1_PCIE0.23 J1_PCIE0.28 J1_PCIE0.29 J1_PCIE0.34 J1_PCIE0.40 J1_PCIE0.41 J1_PCIE0.46 J1_PCIE0.52 J1_PCIE0.M J1_PCIE1.1 J1_PCIE1.3 J1_PCIE1.6 J1_PCIE1.8 J1_PCIE1.9 J1_PCIE1.10 J1_PCIE1.16 J1_PCIE1.17 J1_PCIE1.22 J1_PCIE1.23 J1_PCIE1.28 J1_PCIE1.29 J1_PCIE1.34 J1_PCIE1.40 J1_PCIE1.41 J1_PCIE1.46 J1_PCIE1.52 J1_PCIE1.M J1_PCIE2.1 J1_PCIE2.3 J1_PCIE2.6 J1_PCIE2.8 J1_PCIE2.9 J1_PCIE2.10 J1_PCIE2.16 J1_PCIE2.17 J1_PCIE2.22 J1_PCIE2.23 J1_PCIE2.28 J1_PCIE2.29 J1_PCIE2.34 J1_PCIE2.40 J1_PCIE2.41 J1_PCIE2.46 J1_PCIE2.52 J1_PCIE2.M J1_PCIE3.1 J1_PCIE3.3 J1_PCIE3.6 J1_PCIE3.8 J1_PCIE3.9 J1_PCIE3.10 J1_PCIE3.16 J1_PCIE3.17 J1_PCIE3.22 J1_PCIE3.23 J1_PCIE3.28 J1_PCIE3.29 J1_PCIE3.34 J1_PCIE3.40 J1_PCIE3.41 J1_PCIE3.46 J1_PCIE3.52 J1_PCIE3.M J1_PCIE4.1 J1_PCIE4.3 J1_PCIE4.6 J1_PCIE4.8 J1_PCIE4.9 J1_PCIE4.10 J1_PCIE4.16 J1_PCIE4.17 J1_PCIE4.22 J1_PCIE4.23 J1_PCIE4.28 J1_PCIE4.29 J1_PCIE4.34 J1_PCIE4.40 J1_PCIE4.41 J1_PCIE4.46 J1_PCIE4.52 J1_PCIE4.M J14.1 J15.1 J16.1 J17.1 J18.1 J19.1 J20.1 J21.1 J22.1 J23.1 J24.1 J27.1 J27.3 J27.9 J27.15 J27.21 J27.27 J27.33 J27.39 J27.45 J27.51 J27.57 J27.63 J27.65 J27.67 J28.6 J31.SH1 J31.SH2 J31.SH3 J31.SH4 J31.SH5 J31.SH6 J31.SH7 J31.SH8 J31.SH9 J31.SH10 J31.SH11 J31.SH12 J31.SH13 J31.SH14 J31.SH15 J31.SH16 J31.SH17 J31.SH18 J31.SH19 J31.SH20 J31.SH21 J31.SH22 J31.SH23 J31.SH24 J31.SH25 J31.SH26 J31.SH27 J31.SH28 J31.SH29 J31.SH30 J31.SH31 J31.SH32 J31.SH33 J31.SH34 J31.SH35 J31.SH36 J31.SH37 J31.SH38 J31.SH39 J31.SH40 J31.SH41 J31.SH42 J31.SH43 J31.SH44 J31.SH45 J31.SH46 J32.1 J32.10 J32.11 J32.14 J32.17 J32.20 J33.1 J33.10 J33.11 J33.14 J33.16 J34.1 J34.10 J34.11 J34.14 J34.16 J35.1 J35.10 J35.11 J35.14 J35.16 P5.2 P7.1 P9.1 P11.2 P12.2 P12.4 P12.6 P12.8 P12.10 P12.12 P12.14 R2.1 R14.1 R18.1 R19.1 R21.1 R23.1 R25.1 R26.1 R27.1 R28.2 R56.2 R60.2 R61.2 R62.2 R63.2 R64.2 R73.1 R74.1 R109.1 R114.1 R129.2 R139.1 R143.1 R144.1 R153.1 R154.1 R163.1 R164.1 R167.2 R168.2 R170.2 R172.2 R173.2 R174.1 R178.1 R182.1 R183.1 R187.1 R191.1 R192.1 R196.1 R200.1 R201.1 R205.1 R209.1 R210.1 R214.1 R217.1 R218.1 R228.1 R229.1 R242.2 R244.2 R267.1 R269.1 R274.1 R275.1 R279.2 R280.1 R282.2 R284.1 R292.1 R299.1 R304.1 R317.1 R325.1 R326.1 R327.1 R328.1 R334.2 R341.1 R344.1 R345.1 R358.2 R359.2 R360.2 R361.2 R373.1 R379.1 R380.1 R393.1 R396.1 R399.1 R400.2 R450.2 R452.2 R454.2 R456.2 R460.2 R461.1 R464.2 R467.1 R470.2 R472.2 R474.2 R476.2 R478.2 R480.2 R493.2 R495.2 R497.2 R501.2 R503.2 R505.2 R509.2 R511.2 R513.2 R517.2 R519.2 R521.2 R525.2 R527.2 R529.2 R561.1 R565.1 R569.1 R573.1 R577.1 R581.1 R585.1 R589.1 R595.1 R601.1 R602_SPI_bridge_Main.2 R602_SPI_bridge_PCIe.2 R606_SPI_bridge_Main.2 R606_SPI_bridge_PCIe.2 R629.1 R645.1 R652.1 R668.1 R672.1 R674.1 R675.1 R681.1 R682.1 R683.1 R684.1 R685.1 R690.1 R693.2 R696.2 R698.2 R700.2 R702.2 R704.2 R706.2 R708.2 R714.1 R720.2 R739.2 R741.2 R743.2 R759.2 R761.2 R763.2 R764.1 R830.2 R832.2 R834.2 R837.2 R839.2 R840.2 R842.2 R844.2 R846.2 R890_SPI_bridge_Main.2 R890_SPI_bridge_PCIe.2 R894_SPI_bridge_Main.2 R894_SPI_bridge_PCIe.2 R898_SPI_bridge_Main.2 R898_SPI_bridge_PCIe.2 R920.2 R1003.1 R1052.2 R1053.2 S2.3 S2.4 S3.3 S3.4 S4.3 S4.4 S6.1 S6.2 T1.2 T7.1 T7.2 T7.3 T8.1 T8.2 T8.3 T11.1 T11.2 T11.3 T12.1 T12.2 T12.3 T14.1 T14.2 T14.3 T16.1 T16.2 T16.3 T18.1 T18.2 T18.3 T20.1 T20.2 T20.3 T24.2 T25.2 T26.2 T28.2 T29.2 T31.2 U1.A1 U1.A2 U1.A5 U1.A9 U1.A11 U1.A30 U1.AA9 U1.AA19 U1.AA29 U1.AB2 U1.AB7 U1.AB12 U1.AB17 U1.AB22 U1.AC5 U1.AC10 U1.AC20 U1.AD13 U1.AD18 U1.AD23 U1.AE6 U1.AE16 U1.AE21 U1.AF4 U1.AF9 U1.AF19 U1.AF24 U1.AF29 U1.AG2 U1.AG12 U1.AG22 U1.AH5 U1.AH15 U1.AH20 U1.AH25 U1.AJ3 U1.AJ8 U1.AJ13 U1.AJ18 U1.AJ23 U1.AJ28 U1.AK1 U1.AK30 U1.B3 U1.B4 U1.B7 U1.B11 U1.B13 U1.B17 U1.C1 U1.C2 U1.C5 U1.C9 U1.C11 U1.C15 U1.C20 U1.C25 U1.C30 U1.D3 U1.D4 U1.D7 U1.D11 U1.E1 U1.E2 U1.E5 U1.E9 U1.E11 U1.F3 U1.F4 U1.F7 U1.F11 U1.F14 U1.F24 U1.F25 U1.F26 U1.F27 U1.F28 U1.F29 U1.F30 U1.G1 U1.G2 U1.G5 U1.G9 U1.G11 U1.G17 U1.G22 U1.G23 U1.G24 U1.G27 U1.G28 U1.H3 U1.H4 U1.H7 U1.H11 U1.H20 U1.H22 U1.H26 U1.H29 U1.H30 U1.J1 U1.J2 U1.J5 U1.J9 U1.J10 U1.J11 U1.J13 U1.J22 U1.J24 U1.J27 U1.J28 U1.K3 U1.K4 U1.K9 U1.K22 U1.K26 U1.K29 U1.K30 U1.L1 U1.L2 U1.L5 U1.L9 U1.L12 U1.L16 U1.L18 U1.L22 U1.L24 U1.L28 U1.M3 U1.M4 U1.M7 U1.M9 U1.M11 U1.M13 U1.M15 U1.M17 U1.M22 U1.M26 U1.M29 U1.M30 U1.N1 U1.N2 U1.N5 U1.N9 U1.N12 U1.N14 U1.N16 U1.N23 U1.N24 U1.N25 U1.N26 U1.N27 U1.N28 U1.N29 U1.N30 U1.P3 U1.P4 U1.P7 U1.P9 U1.P11 U1.P13 U1.P15 U1.P17 U1.R1 U1.R2 U1.R5 U1.R9 U1.R12 U1.R16 U1.R21 U1.R26 U1.T3 U1.T4 U1.T7 U1.T8 U1.T11 U1.T13 U1.T17 U1.T19 U1.T24 U1.T29 U1.U1 U1.U2 U1.U5 U1.U7 U1.U12 U1.U16 U1.U22 U1.U27 U1.V3 U1.V4 U1.V7 U1.V9 U1.V11 U1.V13 U1.V20 U1.V25 U1.W1 U1.W2 U1.W5 U1.W6 U1.W12 U1.W14 U1.W16 U1.W18 U1.W23 U1.W28 U1.Y2 U1.Y3 U1.Y4 U1.Y5 U1.Y11 U1.Y13 U1.Y15 U1.Y21 U1.Y26 U3_I2C_Bridge_GPIO.9 U3_I2C_Bridge_GPIO.25 U3_I2C_Bridge_PCIE.9 U3_I2C_Bridge_PCIE.25 U3_I2C_Bridge_SFP.9 U3_I2C_Bridge_SFP.25 U4.3 U4.6 U4.12 U5.3 U5.6 U5.12 U6.A1 U6.B1 U6.B2 U6.B3 U6.B4 U6.C4 U7.A1 U7.B1 U7.B2 U7.B3 U7.B4 U7.C4 U8.A2 U8.A5 U8.B2 U8.C6 U8.D2 U8.D5 U8.E1 U8.E3 U8.E5 U8.E6 U8.F1 U8.G5 U8.H1 U8.H6 U8.K1 U8.K6 U8.M6 U8.N1 U8.T1 U9.A2 U9.A5 U9.B2 U9.C6 U9.D2 U9.D5 U9.E1 U9.E3 U9.E5 U9.E6 U9.F1 U9.G5 U9.H1 U9.H6 U9.K1 U9.K6 U9.M6 U9.N1 U9.T1 U10.A2 U10.A5 U10.B2 U10.C6 U10.D2 U10.D5 U10.E1 U10.E3 U10.E5 U10.E6 U10.F1 U10.G5 U10.H1 U10.H6 U10.K1 U10.K6 U10.M6 U10.N1 U10.T1 U11.A2 U11.A5 U11.B2 U11.C6 U11.D2 U11.D5 U11.E1 U11.E3 U11.E5 U11.E6 U11.F1 U11.G5 U11.H1 U11.H6 U11.K1 U11.K6 U11.M6 U11.N1 U11.T1 U15.2 U15.10 U17.A1 U17.A4 U17.B1 U17.B2 U17.B3 U17.B4 U17.C4 U18.A1 U18.A4 U18.B1 U18.B2 U18.B3 U18.B4 U18.C4 U19.10 U19.18 U19.27 U19.29 U20.A1 U20.A4 U20.B1 U20.B2 U20.B3 U20.B4 U20.C4 U21.A1 U21.A4 U21.B1 U21.B2 U21.B3 U21.B4 U21.C4 U22.A1 U22.A4 U22.B1 U22.B2 U22.B3 U22.B4 U22.C4 U23.A1 U23.A4 U23.B1 U23.B2 U23.B3 U23.B4 U23.C4 U24_SPI_bridge_Main.10 U24_SPI_bridge_PCIe.10 U25_SPI_bridge_Main.10 U25_SPI_bridge_PCIe.10 U26_SPI_bridge_Main.10 U26_SPI_bridge_PCIe.10 U27_SPI_bridge_Main.10 U27_SPI_bridge_PCIe.10 U28_SPI_bridge_Main.10 U28_SPI_bridge_PCIe.10 U34.19 U34.22 U35_I2C_Expander_00.6 U35_I2C_Expander_00.29 U35_I2C_Expander_01.6 U35_I2C_Expander_01.29 U35_I2C_Expander_02.6 U35_I2C_Expander_02.29 U35_I2C_Expander_10.6 U35_I2C_Expander_10.29 U35_I2C_Expander_11.6 U35_I2C_Expander_11.29 U35_I2C_Expander_12.6 U35_I2C_Expander_12.29 U35_I2C_Expander_16.6 U35_I2C_Expander_16.29 U35_I2C_Expander_17.6 U35_I2C_Expander_17.29 U35_I2C_Expander_18.6 U35_I2C_Expander_18.29 U35_I2C_Expander_Main_Rst.6 U35_I2C_Expander_Main_Rst.29 U35_I2C_Expander_PWR_CLK.6 U35_I2C_Expander_PWR_CLK.29 U35_I2C_Expander_PWR_Dist.6 U35_I2C_Expander_PWR_Dist.29 U35_I2C_Expander_SFP.6 U35_I2C_Expander_SFP.29 U36_U_Translator_I2C1.1 U36_U_Translator_I2C2.1 U36_U_Translator_I2C3.1 U36_U_Translator_I2C4.1 U37.19 U37.22 U38.19 U38.22 U39.49 U40.4 U40.9 U41.A6 U41.C4 U41.E7 U41.G5 U41.H10 U41.J5 U41.K8 U41.N2 U41.N5 U41.P4 U41.P6 U42.4 U42.9 U43.9 U43.10 U44.4 U44.5 U44.17 U45.23 U45.33 U46.A1 U46.A4 U46.B1 U46.B2 U46.B4 U47.C3 U48.12 U49.4 U49.9 U50.4 U50.9 U51.4 U51.9 U58.2 U58.3 U58.6 U58.7 U63.2 U63.8 U64_U_Pomiar_pradu_napiecia_1.7 U64_U_Pomiar_pradu_napiecia_2.7 U64_U_Pomiar_pradu_napiecia_3.7 U64_U_Pomiar_pradu_napiecia_4.7 U64_U_Pomiar_pradu_napiecia_5.7 U64_U_Pomiar_pradu_napiecia_6.7 U64_U_Pomiar_pradu_napiecia_7.7 U64_U_Pomiar_pradu_napiecia_8.7 U64_U_Pomiar_pradu_napiecia_9.7 U64_U_Pomiar_pradu_napiecia_10.7 U64_U_Pomiar_pradu_napiecia_11.7 U67.2 U68.2 U69.6 U69.17 U70.3 U70.8 U70.13 U70.18 U70.21 U72.7 U73.4 U73.9 U74.3 U75.3 U78.2 X4.2 X4.4 X6.2 X7.2 X7.4 | length 267.4
  L1 w0.116: v5(177.909,309.05) U1.U22@178.397,309.537 ; v5(179.909,310.052) U1.W23@180.397,310.539 ; 182.909,289.052 U1.AB2@183.397,289.539 ; v5(183.909,307.052) U1.AC20@184.397,307.539 ; v5(185.909,308.052) U1.AE21@186.397,308.539 ; v5(186.909,306.052) U1.AF19@187.397,306.539 ; v5(186.909,316.052) U1.AF29@187.397,316.539 ; v5(188.909,307.052) U1.AH20@189.397,307.539 ; U1.AH25@189.397,312.539 v5(189.884,313.027) ; v5(189.909,305.052) U1.AJ18@190.397,305.539 ; U1.AJ23@190.397,310.539 v5(190.884,311.027) ; U1.AJ28@190.397,315.539 v5(190.884,315.052) ; U1.AK30@191.397,317.539 v5@191.884,318.027 ; v3@206.343,327.774 v3(206.35,327.774) ; U8.E1@206.857,331.26 U8.E1@206.863,331.254
  L1 w0.2: C535.1@148.603,330.314 C536.1@149.543,330.314 ; U9.H6@166.076,333.66 v10(166.076,333.667) ; U9.E3@170.876,331.26 v10(170.876,331.268) ; U11.H6@177.536,333.66 v10(177.536,333.664) ; v10(183.134,330.46) U11.D2@183.136,330.46 ; v10(183.394,309.542) U1.AB22@183.397,309.539 ; v10(183.934,333.663) U11.H1@183.936,333.66 ; U10.A5@189.797,328.06 v10(189.797,328.063) ; v10(200.449,333.66) U8.H6@200.457,333.66 ; v10(205.251,331.26) U8.E3@205.257,331.26 ; v3(205.684,330.088) U8.D2@206.057,330.46 ; U8.F1@206.857,332.06 v3(207.428,332.06) ; U8.H1@206.857,333.66 v3(207.261,334.064) ; U8.K1@206.857,335.26 v3(207.261,335.664) ; U8.N1@206.857,337.66 v3(207.261,338.064) ; U8.T1@206.857,340.06 v3(207.261,340.464) ; U8.E1@206.863,331.254 v3(207.645,331.254)
  L1 w0.25: v1(161.216,338.184) R56.2@162.46,338.184 ; v3(171.272,327.657) U9.A2@171.676,328.06 ; v3(171.272,328.457) U9.B2@171.676,328.86 ; U9.D2@171.676,330.46 v3(172.079,330.864) ; v3(177.133,329.257) U11.C6@177.536,329.66 ; v3(177.133,330.857) U11.E6@177.536,331.26 ; v3(177.933,330.857) U11.E5@178.336,331.26 ; U11.A5@178.336,328.06 178.74,327.657 ; v1(181.909,317.027) U1.AA29@182.397,316.539 ; v3(182.733,327.657) U11.A2@183.136,328.06 ; v3(182.733,328.457) U11.B2@183.136,328.86 ; U11.E1@183.936,331.26 v3(184.507,331.26) ; U11.F1@183.936,332.06 v3(184.507,332.06) ; U11.N1@183.936,337.66 v3(184.34,338.064) ; v3(188.593,330.064) U10.C6@188.997,329.66 ; v3(188.593,331.664) U10.E6@188.997,331.26 ; v3(188.593,334.064) U10.H6@188.997,333.66 ; v3(188.593,337.264) U10.M6@188.997,336.86 ; v3(189.393,330.864) U10.D5@189.797,330.46 ; v3(189.393,331.664) U10.E5@189.797,331.26 ; U10.G5@189.797,332.86 v3(190.2,332.457) ; U8.A2@206.057,328.06 v3@206.343,327.774
  L1 w0.254: U64_U_Pomiar_pradu_napiecia_3.7@116.278,183.659 v6(117.754,183.659) ; U1.AF24@187.397,311.539 v10(187.401,311.535) ; v10(188.394,309.539) U1.AG22@188.397,309.539 ; v1@198.406,331.26 v1(198.495,331.26) U8.E6@200.457,331.26 ; v1(198.653,333.858) v1@198.761,333.858
  L1 w0.3: U1.AD23@185.397,310.539 v10(185.397,310.548) ; U10.E3@193.797,331.26 v1(194.195,331.659) ; U10.D2@194.597,330.46 v10(194.599,330.463) ; U10.E1@195.397,331.26 v10(195.397,331.268) ; U8.B2@206.057,328.86 v10(206.057,328.878)
  L1 w0.5: v1(35.023,183.811) C12.2@36.11,183.811 ; v1(35.023,184.916) C12.2@36.11,184.916 ; v1(35.023,186.012) C12.2@36.11,186.012 ; v1(35.023,187.256) C15.2@36.11,187.256 ; v1(35.023,188.361) C15.2@36.11,188.361 ; v1(35.023,189.458) C15.2@36.11,189.457 ; v1(35.023,190.701) C13.2@36.11,190.701 ; v1(35.023,191.806) C13.2@36.11,191.806 ; v1(35.023,192.903) C13.2@36.11,192.903 ; v1(35.023,194.146) C14.2@36.11,194.146 ; v1(35.023,195.251) C14.2@36.11,195.251 ; v1(35.023,196.348) C14.2@36.11,196.348 ; v1(35.104,169.788) C4.2@36.191,169.788 ; v1(35.104,170.893) C4.2@36.191,170.893 ; v1(35.104,171.99) C4.2@36.191,171.99 ; v1(35.104,173.243) C5.2@36.191,173.243 ; v1(35.104,174.348) C5.2@36.191,174.348 ; v1(35.104,175.445) C5.2@36.191,175.445 ; v1(35.104,176.697) C7.2@36.191,176.697 ; v1(35.104,177.802) C7.2@36.191,177.802 ; v1(35.104,178.899) C7.2@36.191,178.899 ; v1(35.104,180.152) C6.2@36.191,180.152 ; v1(35.104,181.257) C6.2@36.191,181.257 ; v1(35.104,182.353) C6.2@36.191,182.353 ; C12.2@36.11,184.359 v1(37.197,184.359) ; C12.2@36.11,185.464 v1(37.197,185.464) ; C15.2@36.11,187.804 v1(37.197,187.804) ; C15.2@36.11,188.909 v1(37.197,188.909) ; C13.2@36.11,191.249 v1(37.197,191.249) ; C13.2@36.11,192.354 v1(37.197,192.354) ; C14.2@36.11,194.694 v1(37.197,194.694) ; C14.2@36.11,195.799 v1(37.197,195.799) ; C4.2@36.191,170.337 v1(37.278,170.337) ; C4.2@36.191,171.442 v1(37.278,171.442) ; C5.2@36.191,173.791 v1(37.278,173.791) ; C5.2@36.191,174.896 v1(37.278,174.896) ; C7.2@36.191,177.246 v1(37.278,177.246) ; C7.2@36.191,178.351 v1(37.278,178.351) ; C6.2@36.191,180.7 v1(37.278,180.7) ; C6.2@36.191,181.805 v1(37.278,181.805) ; v6(42.6,191.22) R683.1@42.6,192.033 ; R685.1@42.6,195.933 v6(42.6,196.747) ; R684.1@44.716,195.933 v6(44.716,196.747) ; v6(45.775,191.22) R682.1@45.775,192.033 ; v6(46.946,174.081) 47.391,174.081 U5.6@47.56,174.25 ; v6(46.946,175.918) 47.391,175.918 U5.3@47.56,175.75 ; v6(46.946,183.403) 47.391,183.403 U4.6@47.56,183.571 ; v6(46.946,185.24) 47.391,185.24 U4.3@47.56,185.071 ; v1(49.579,210.588) C780.1@50.666,210.588 ; v1(49.579,211.312) C780.1@50.665,211.312 ; v1(49.579,212.483) C779.1@50.666,212.483 ; v1(49.579,213.207) C779.1@50.666,213.207 ; v1(49.579,214.293) C778.1@50.666,214.293 ; v1(49.579,215.016) C778.1@50.666,215.016 ; v1(49.579,216.83) C777.1@50.666,216.83 ; v1(49.579,217.851) C776.1@50.666,217.851 ; v1(49.579,218.575) C776.1@50.666,218.575 ; v1(49.579,219.674) C775.1@50.666,219.674 ; v1(49.579,220.398) C775.1@50.666,220.398 ; v1(49.579,221.488) C774.1@50.666,221.488 ; v1(49.579,222.211) C774.1@50.666,222.211 ; v1(49.579,216.106) C777.1@50.666,216.106 ; U48.12@49.827,194.733 49.996,194.902 v6(50.442,194.902) ; U5.12@49.86,175.75 50.029,175.918 v6(50.475,175.918) ; U4.12@49.86,185.071 50.029,185.24 v6(50.475,185.24) ; R18.1@52.01,184.471 v6(52.01,185.285) ; R681.1@52.018,194.019 v6(52.018,194.833) ; C20.1@56.419,164.502 v1(57.506,164.502) ; C20.1@56.419,163.778 v1(57.506,163.778) ; C27.1@56.447,165.786 v1(57.534,165.786) ; C27.1@56.446,166.51 v1(57.533,166.51) ; C22.1@56.447,167.684 v1(57.534,167.684) ; C22.1@56.446,168.408 v1(57.533,168.408) ; C21.1@56.447,169.581 v1(57.534,169.581) ; C21.1@56.446,170.305 v1(57.533,170.305) ; C24.1@56.447,171.479 v1(57.534,171.479) ; C24.1@56.446,172.203 v1(57.533,172.203) ; C25.1@56.447,173.377 v1(57.534,173.377) ; C25.1@56.446,174.101 v1(57.533,174.101) ; C23.1@56.447,175.275 v1(57.534,175.275) ; C23.1@56.446,175.999 v1(57.533,175.999) ; C31.1@56.458,179.934 v1(57.545,179.934) ; C30.1@56.458,181.831 v1(57.545,181.831) ; C32.1@56.458,183.729 v1(57.545,183.729) ; C29.1@56.458,185.627 v1(57.545,185.627) ; C28.1@56.458,187.525 v1(57.545,187.525) ; C33.1@56.458,189.423 v1(57.545,189.423) ; C34.1@56.458,191.321 v1(57.545,191.321) ; C31.1@56.459,179.21 v1(57.546,179.21) ; C30.1@56.459,181.108 v1(57.546,181.108) ; C32.1@56.459,183.005 v1(57.546,183.005) ; C29.1@56.459,184.903 v1(57.546,184.903) ; C28.1@56.459,186.801 v1(57.546,186.801) ; C33.1@56.459,188.699 v1(57.546,188.699) ; C34.1@56.459,190.597 v1(57.546,190.597) ; C26.1@56.477,177.173 v1(57.564,177.173) ; C26.1@56.476,177.897 v1(57.563,177.897) ; C35.1@56.484,193.263 v1(57.571,193.263) ; C35.1@56.484,192.539 v1(57.571,192.539) ; v1(58.138,222.101) C392.1@58.138,223.188 ; C397.2@58.206,217.883 v1(58.206,218.97) ; v1(58.776,222.101) C392.1@58.776,223.188 ; C397.2@58.852,217.883 v1(58.852,218.97) ; v1(59.421,222.101) C392.1@59.421,223.188 ; C397.2@59.489,217.883 v1(59.489,218.97) ; v1(59.638,165.636) C433.1@59.638,166.723 ; C438.2@59.645,190.731 v1(59.645,191.818) ; v1(59.653,193.043) C353.1@59.653,194.13 ; v1(60.276,165.636) C433.1@60.276,166.723 ; C438.2@60.29,190.731 v1(60.29,191.818) ; v1(60.29,193.043) C353.1@60.29,194.13 ; v1(60.62,222.101) C391.2@60.62,223.188 ; C396.1@60.688,217.883 v1(60.688,218.97) ; v1(60.921,165.636) C433.1@60.921,166.723 ; C438.2@60.927,190.731 v1(60.927,191.818) ; v1(60.936,193.043) C353.1@60.936,194.13 ; v1(61.258,222.101) C391.2@61.258,223.188 ; C396.1@61.334,217.883 v1(61.334,218.97) ; v1(61.903,222.101) C391.2@61.903,223.188 ; C396.1@61.971,217.883 v1(61.971,218.97) ; v1(62.12,165.636) C432.2@62.12,166.723 ; C437.1@62.127,190.731 v1(62.127,191.818) ; v1(62.135,193.043) C352.1@62.135,194.13 ; C769.2@62.575,157.849 v1(62.575,158.936) ; v1(62.758,165.636) C432.2@62.758,166.723 ; C437.1@62.772,190.731 v1(62.772,191.818) ; v1(62.772,193.043) C352.1@62.772,194.13 ; v1(63.102,222.1) C405.1@63.102,223.187 ; v1(63.124,156.762) C769.2@63.124,157.849 ; C402.1@63.17,217.883 v1(63.17,218.97) ; v1(63.403,165.636) C432.2@63.403,166.723 ; C437.1@63.409,190.731 v1(63.409,191.818) ; v1(63.418,193.043) C352.1@63.418,194.13 ; C769.2@63.68,157.849 v1(63.68,158.936) ; v1(63.74,222.1) C405.1@63.74,223.187 ; C402.1@63.816,217.883 v1(63.816,218.97) ; v1(64.229,156.762) C769.2@64.229,157.849 ; v1(64.385,222.1) C405.1@64.385,223.187 ; C402.1@64.453,217.883 v1(64.453,218.97) ; v1(64.602,165.636) C446.1@64.602,166.723 ; C443.1@64.609,190.731 v1(64.609,191.818) ; v1(64.617,193.043) C374.1@64.617,194.13 ; C769.2@64.777,157.849 v1(64.777,158.936) ; v1(65.24,165.636) C446.1@65.24,166.723 ; C443.1@65.254,190.731 v1(65.254,191.818) ; v1(65.254,193.043) C374.1@65.254,194.13 ; v1(65.584,222.1) C404.1@65.584,223.187 ; C401.1@65.652,217.883 v1(65.652,218.97) ; v1(65.885,165.636) C446.1@65.885,166.723 ; C443.1@65.891,190.731 v1(65.891,191.818) ; v1(65.9,193.043) C374.1@65.9,194.13 ; C768.2@65.979,157.65 v1(65.979,158.737) ; v1(66.222,222.1) C404.1@66.222,223.187 ; C401.1@66.298,217.883 v1(66.298,218.97) ; v1(66.528,156.563) C768.2@66.528,157.65 ; v1(66.867,222.1) C404.1@66.867,223.187 ; C401.1@66.935,217.883 v1(66.935,218.97) ; C768.2@67.084,157.65 v1(67.084,158.737) ; v1(67.085,165.636) C445.1@67.085,166.723 ; C442.1@67.091,190.731 v1(67.091,191.818) ; v1(67.099,193.043) C371.1@67.099,194.13 ; v1(67.632,156.563) C768.2@67.632,157.65 ; v1(67.722,165.636) C445.1@67.722,166.723 ; C442.1@67.736,190.731 v1(67.736,191.818) ; v1(67.736,193.043) C371.1@67.736,194.13 ; v1(68.066,222.07) C403.1@68.066,223.157 ; C400.1@68.134,217.853 v1(68.134,218.94) ; C768.2@68.181,157.65 v1(68.181,158.737) ; v1(68.367,165.636) C445.1@68.367,166.723 ; C442.1@68.373,190.731 v1(68.373,191.818) ; v1(68.382,193.043) C371.1@68.382,194.13 ; v1(68.704,222.07) C403.1@68.704,223.157 ; C400.1@68.78,217.853 v1(68.78,218.94) ; v1(69.349,222.07) C403.1@69.349,223.157 ; C400.1@69.417,217.853 v1(69.417,218.94) ; C767.2@69.419,157.85 v1(69.419,158.937) ; v1(69.567,165.605) C444.1@69.567,166.692 ; C441.1@69.573,190.7 v1(69.573,191.787) ; v1(69.581,193.012) C376.1@69.581,194.099 ; v1(69.967,156.763) C767.2@69.967,157.85 ; v1(70.204,165.605) C444.1@70.204,166.692 ; C441.1@70.218,190.7 v1(70.218,191.787) ; v1(70.218,193.012) C376.1@70.218,194.099 ; C767.2@70.524,157.85 v1(70.524,158.937) ; v1(70.849,165.605) C444.1@70.849,166.692 ; C441.1@70.855,190.7 v1(70.855,191.787) ; v1(70.864,193.012) C376.1@70.864,194.099 ; v1(71.072,156.763) C767.2@71.072,157.85 ; C767.2@71.621,157.85 v1(71.621,158.937) ; C766.2@72.887,157.849 v1(72.887,158.936) ; v1(72.923,170.65) T16.3@74.01,170.65 ; v1(72.923,171.92) T16.2@74.01,171.92 ; v1(72.923,173.19) T16.1@74.01,173.19 ; v1(73.127,185.42) T14.3@74.214,185.42 ; v1(73.127,186.69) T14.2@74.214,186.69 ; v1(73.127,187.96) T14.1@74.214,187.96 ; v1(73.435,156.762) C766.2@73.435,157.849 ; v1(73.987,201.422) T20.3@75.074,201.422 ; v1(73.987,202.692) T20.2@75.074,202.692 ; v1(73.987,203.962) T20.1@75.074,203.962 ; C766.2@73.992,157.849 v1(73.992,158.936) ; v1(74.086,209.067) T18.3@75.173,209.067 ; v1(74.086,210.337) T18.2@75.173,210.337 ; v1(74.086,211.607) T18.1@75.173,211.607 ; v1(74.54,156.762) C766.2@74.54,157.849 ; C348.1@74.983,256.276 v1(74.983,257.362) ; C766.2@75.088,157.849 v1(75.088,158.936) ; C348.1@75.629,256.276 v1(75.629,257.362) ; C348.1@76.266,256.276 v1(76.266,257.362) ; C347.1@77.465,256.276 v1(77.465,257.363) ; C347.1@78.111,256.275 v1(78.111,257.363) ; C347.1@78.748,256.276 v1(78.748,257.363) ; C372.1@79.947,256.275 v1(79.947,257.362) ; C372.1@80.593,256.275 v1(80.593,257.362) ; C372.1@81.23,256.275 v1(81.23,257.362) ; C375.1@82.429,256.275 v1(82.429,257.362) ; C375.1@83.075,256.275 v1(83.075,257.362) ; C375.1@83.712,256.275 v1(83.712,257.362) ; C373.1@84.911,256.245 v1(84.911,257.332) ; C373.1@85.557,256.245 v1(85.557,257.332) ; C373.1@86.194,256.245 v1(86.194,257.332)
  L16 w0.254: v1(198.653,333.858) v1@198.704,333.858
  other v1: 75.092,233.907 76.352,233.907 77.612,233.907 78.872,233.907 82.032,233.914 83.292,233.914 84.552,233.914 85.812,233.914 87.072,234.379 88.332,234.379 89.591,234.379 90.851,234.379 92.111,234.379 93.371,234.379 94.631,234.379 95.891,234.379 97.151,234.379 98.4,234.848 99.089,234.848 99.779,234.848 100.469,234.848 101.159,234.848 101.848,234.848 102.538,234.848 103.228,234.848 103.918,234.848 104.607,234.848 105.297,234.848 105.987,234.848 106.677,234.848 107.366,234.848 108.056,234.848 108.746,234.848 109.436,234.848 110.125,234.848 110.815,234.848 111.505,234.848 112.195,234.848 75.092,235.632 76.352,235.632 77.612,235.632 78.872,235.632 80.488,235.639 82.032,235.639 83.292,235.639 84.552,235.639 85.812,235.639 87.072,235.639 88.332,235.639 89.591,235.639 90.851,235.639 92.111,235.639 93.371,235.639 94.631,235.639 95.891,235.639 97.151,235.639 98.411,235.639 99.101,235.639 99.79,235.639 100.48,235.639 101.17,235.639 101.86,235.639 102.55,235.639 103.239,235.639 103.929,235.639 104.619,235.639 105.309,235.639 105.998,235.639 106.688,235.639 107.378,235.639 108.068,235.639 108.757,235.639 109.447,235.639 110.137,235.639 110.827,235.639 111.516,235.639 112.206,235.639 98.411,236.461 99.101,236.461 99.79,236.461 100.48,236.461 101.17,236.461 101.86,236.461 102.55,236.461 103.239,236.461 103.929,236.461 104.619,236.461 105.309,236.461 105.998,236.461 106.688,236.461 107.378,236.461 108.068,236.461 108.757,236.461 109.447,236.461 110.137,236.461 110.827,236.461 111.516,236.461 112.206,236.461 87.072,236.899 88.332,236.899 89.591,236.899 90.851,236.899 92.111,236.899 93.371,236.899 94.631,236.899 95.891,236.899 97.151,236.899 75.129,237.339 76.389,237.339 77.649,237.339 78.909,237.339 82.069,237.346 83.328,237.346 84.588,237.346 85.848,237.346 179.397,312.539 181.397,313.539 202.619,326.479 199.72,329.552
  other v2: 449.881,54.043 450.981,54.043 449.881,55.143 450.981,55.143 449.881,56.243 450.981,56.243 378.182,64.701 379.282,64.701 378.182,65.801 379.282,65.801 47.443,157.653 48.543,157.653 49.643,157.653 50.743,157.653 47.443,158.753 48.543,158.753 49.643,158.753 50.743,158.753 47.443,159.853 48.543,159.853 49.643,159.853 50.743,159.853 47.443,160.953 48.543,160.953 49.643,160.953 50.743,160.953 136.208,172.721 137.308,172.721 138.408,172.721 139.508,172.721 136.208,173.821 137.308,173.821 138.408,173.821 139.508,173.821 136.208,174.921 137.308,174.921 138.408,174.921 139.508,174.921 136.208,176.021 137.308,176.021 138.408,176.021 139.508,176.021 197.289,244.76 198.389,244.76 199.489,244.76 200.589,244.76 197.289,245.86 198.389,245.86 199.489,245.86 200.589,245.86 197.289,246.96 198.389,246.96 199.489,246.96 200.589,246.96 197.289,248.06 198.389,248.06 199.489,248.06 200.589,248.06 92.069,250.563 93.069,250.563 92.069,251.563 93.069,251.563 103.995,251.848 104.995,251.848 98.601,251.871 99.601,251.871 103.995,252.848 104.995,252.848 98.601,252.871 99.601,252.871 107.614,276.725 108.984,276.725 106.499,277.84 107.614,277.84 108.984,277.84 110.099,277.84 106.499,279.21 107.614,279.21 108.984,279.21 110.099,279.21 588.377,280.206 589.477,280.206 590.577,280.206 591.677,280.206 107.614,280.325 108.984,280.325 150.014,281.103 150.914,281.103 151.814,281.103 588.377,281.306 589.477,281.306 590.577,281.306 591.677,281.306 150.014,282.003 150.914,282.003 151.814,282.003 588.377,282.406 589.477,282.406 590.577,282.406 591.677,282.406 150.014,282.904 150.914,282.904 151.814,282.904 588.377,283.506 589.477,283.506 590.577,283.506 591.677,283.506 36.894,310.999 37.994,310.999 39.094,310.999 40.194,310.999 36.894,312.099 37.994,312.099 39.094,312.099 40.194,312.099 36.894,313.199 37.994,313.199 39.094,313.199 40.194,313.199 36.894,314.299 37.994,314.299 39.094,314.299 40.194,314.299 105.152,318.613 106.252,318.613 107.352,318.613 108.452,318.613 105.152,319.713 106.252,319.713 107.352,319.713 108.452,319.713 105.152,320.813 106.252,320.813 107.352,320.813 108.452,320.813 105.152,321.913 106.252,321.913 107.352,321.913 108.452,321.913 133.476,329.935 134.476,329.935 133.476,330.935 134.476,330.935 107.712,332.246 108.712,332.246 107.712,333.246 108.712,333.246 81.719,340.747 82.819,340.747 83.919,340.747 85.019,340.747 81.719,341.847 82.819,341.847 83.919,341.847 85.019,341.847 317.685,342.322 318.785,342.322 319.885,342.322 320.985,342.322 81.719,342.947 82.819,342.947 83.919,342.947 85.019,342.947 317.685,343.422 318.785,343.422 319.885,343.422 320.985,343.422 81.719,344.047 82.819,344.047 83.919,344.047 85.019,344.047 317.685,344.522 318.785,344.522 319.885,344.522 320.985,344.522 317.685,345.622 318.785,345.622 319.885,345.622 320.985,345.622 149.744,348.735 150.744,348.735 149.744,349.735 150.744,349.735 206.78,367.29 207.88,367.29 208.98,367.29 210.08,367.29 206.78,368.39 207.88,368.39 208.98,368.39 210.08,368.39 206.78,369.49 207.88,369.49 208.98,369.49 210.08,369.49 206.78,370.59 207.88,370.59 208.98,370.59 210.08,370.59 113.78,377.007 114.88,377.007 115.98,377.007 117.08,377.007 113.78,378.107 114.88,378.107 115.98,378.107 117.08,378.107 113.78,379.207 114.88,379.207 115.98,379.207 117.08,379.207 113.78,380.307 114.88,380.307 115.98,380.307 117.08,380.307 62.87,446.303 63.97,446.303 62.87,447.403 63.97,447.403 71.498,754.453 72.598,754.453 73.698,754.453 74.798,754.453 71.498,755.553 72.598,755.553 73.698,755.553 74.798,755.553 71.498,756.653 72.598,756.653 73.698,756.653 74.798,756.653 71.498,757.753 72.598,757.753 73.698,757.753 74.798,757.753 103.316,762.954 104.415,762.954 105.516,762.954 106.615,762.954 103.316,764.053 104.415,764.053 105.516,764.053 106.615,764.053 103.316,765.154 104.415,765.154 105.516,765.154 106.615,765.154 103.316,766.253 104.415,766.253 105.516,766.253 106.615,766.253 71.498,766.798 72.598,766.798 73.698,766.798 74.798,766.798 71.498,767.898 72.598,767.898 73.698,767.898 74.798,767.898 71.498,768.998 72.598,768.998 73.698,768.998 74.798,768.998 71.498,770.098 72.598,770.098 73.698,770.098 74.798,770.098
  other v3: 162.397,288.539 164.397,288.539 166.397,288.539 168.397,288.539 170.397,288.539 172.397,288.539 174.397,288.539 176.397,288.539 178.397,288.539 162.397,289.539 164.397,289.539 166.397,289.539 168.397,289.539 170.397,289.539 172.397,289.539 174.397,289.539 176.397,289.539 178.397,289.539 163.397,290.539 165.397,290.539 167.397,290.539 169.397,290.539 171.397,290.539 173.397,290.539 175.397,290.539 177.397,290.539 179.397,290.539 163.397,291.539 165.397,291.539 167.397,291.539 169.397,291.539 171.397,291.539 173.397,291.539 175.397,291.539 177.397,291.539 179.397,291.539 162.397,292.539 164.397,292.539 166.397,292.539 168.397,292.539 170.397,292.539 172.397,292.539 174.397,292.539 176.397,292.539 178.397,292.539 163.397,294.539 165.397,294.539 167.397,294.539 169.397,294.539 173.397,294.539 175.397,294.539 177.397,294.539 178.397,294.539 179.397,294.539 177.397,295.539 162.397,296.539 164.397,296.539 166.397,296.539 168.397,296.539 170.397,296.539 171.397,296.539 172.397,296.539 173.397,296.539 174.397,296.539 175.397,296.539 176.397,296.539 179.397,296.539 170.397,297.539 162.397,298.539 163.397,298.539 164.397,298.539 165.397,298.539 166.397,298.539 167.397,298.539 168.397,298.539 169.397,298.539 170.397,298.539 173.397,298.539 175.397,298.539 177.397,298.539 179.397,298.539
  other v5: 180.397,288.539 180.397,289.539 181.397,289.539 181.397,290.539 181.397,291.539 180.397,292.539 181.397,292.539 180.397,293.539 182.397,296.539 181.397,298.539 172.397,299.539 174.397,299.539 176.397,299.539 178.397,299.539 180.397,299.539 163.397,300.539 170.397,300.539 173.397,300.539 175.397,300.539 177.397,300.539 179.397,300.539 181.397,300.539 167.397,301.539 174.397,301.539 180.397,301.539 164.397,302.539 173.397,302.539 175.397,302.539 181.397,302.539 189.397,302.539 172.397,303.539 174.397,303.539 176.397,303.539 178.397,303.539 180.397,303.539 186.397,303.539 173.397,304.539 175.397,304.539 177.397,304.539 183.397,304.539 180.397,305.539 185.397,305.539 177.397,306.539 182.397,306.539 179.397,307.539 176.397,308.539 181.397,308.539 173.397,309.539 174.397,310.539 174.397,311.539 177.397,311.539 174.397,312.539 173.397,313.539 174.397,313.539 176.397,313.539 174.397,314.539 178.397,314.539 174.397,315.539 180.397,315.539 173.397,316.539 174.397,316.539 177.397,316.539 173.397,317.539 174.397,317.539 191.789,317.932
  other v6: 52.5,175.939
  other v10: 194.597,328.06 201.257,328.06 194.597,328.86 200.457,329.66 201.257,330.46 172.476,331.26 182.336,331.26 201.257,331.26 172.476,332.06 195.397,332.06 178.336,332.86 201.257,332.86 172.476,333.66 195.392,333.667 166.076,335.26 177.536,335.26 195.392,335.267 200.457,335.26 177.536,336.86 200.457,336.86 195.392,340.067
  other v14: 52.801,349.155 53.821,349.155 54.841,349.155 55.861,349.155 52.801,350.175 53.821,350.175 54.841,350.175 55.861,350.175 52.801,351.195 53.821,351.195 54.841,351.195 55.861,351.195 52.801,352.215 53.821,352.215 54.841,352.215 55.861,352.215
  other v15: 87.351,288.666 86.506,289.514 87.351,289.514 88.176,289.514 518.223,289.525 87.351,290.364 517.379,290.373 518.223,290.373 519.048,290.373 518.223,291.223 102.07,385.766 101.225,386.613 102.07,386.613 102.895,386.613 102.07,387.463
  other v16: 66.65,205.714 66.599,207.218
  other v34: 149.073,330.314
  other v35: 149.073,330.314
Bank223_MGTREF0_C_N: C276.1 U1.R7 | length 17.9
  L14 (Sign) w0.076: v3(176.397,294.539) 176.397,294.73 cw(c176.568,294.73) 176.568,294.902 184.828,294.902 cw(c184.828,294.424) 185.306,294.424 185.306,287.539 ccw(c185.306,287.487) 185.254,287.487
  L14 (Sign) w0.08: v9(185.144,286.969) ccw(c185.144,287.079) 185.254,287.079 185.254,287.487
  L16 w0.08: v9(185.144,286.969) v9@185.151,286.969
  L16 w0.081: C276.1@185.091,286.131 185.091,286.322 ccw(c185.091,286.374) 185.144,286.374 v9(185.144,286.969) ; v9@185.151,286.957 v9@185.151,286.969
Bank223_MGTREF0_C_P: C273.1 U1.R8 | length 18.4
  L14 (Sign) w0.076: v3(176.397,295.539) 176.397,295.348 ccw(c176.568,295.348) 176.568,295.177 184.828,295.177 cw(c184.828,294.424) 185.581,294.424 185.581,287.539 cw(c185.581,287.487) 185.633,287.487
  L14 (Sign) w0.08: 185.633,287.487 185.633,287.079 ccw(c185.744,287.079) v9(185.744,286.969)
  L16 w0.08: v9@185.736,286.969 v9(185.744,286.969)
  L16 w0.081: v9@185.736,286.957 v9@185.736,286.969 ; v9(185.744,286.969) 185.744,286.322 cw(c185.744,286.226) 185.839,286.226 C273.1@185.839,286.131
Bank223_MGTREF0_N: C276.2 J1_PCIE0.39 | length 172.9
  L14 (Sign) w0.08: v9(150.837,360.528) ccw(c150.837,360.638) 150.947,360.638 150.947,361.036 ccw(c150.554,361.036) 150.554,361.429 149.225,361.429 ccw(c149.225,360.921) 148.717,360.921 148.717,352.45 ccw(c149.594,352.45) 149.594,351.573 157.023,351.573 cw(c157.023,350.227) 158.369,350.227 158.369,349.529 ccw(c159.323,349.529) 159.323,348.576 210.769,348.576 cw(c210.769,346.989) 212.356,346.989 212.356,284.493 cw(c211.252,284.493) 211.252,283.389 185.979,283.389 cw(c185.979,284.093) 185.275,284.093 185.275,284.675 ccw(c185.165,284.675) v9(185.165,284.785)
  L16 w0.081: J1_PCIE0.39@150.737,358.792 150.737,359.725 cw(c150.844,359.725) 150.844,359.832 150.844,360.528 v9(150.837,360.528) ; C276.2@185.091,285.611 185.091,285.502 ccw(c185.172,285.502) 185.172,285.42 185.172,284.785 v9(185.165,284.785)
Bank223_MGTREF0_P: C273.2 J1_PCIE0.37 | length 172.9
  L14 (Sign) w0.08: v9(151.437,360.528) cw(c151.437,360.638) 151.327,360.638 151.327,361.036 ccw(c150.554,361.036) 150.554,361.809 149.225,361.809 ccw(c149.225,360.921) 148.337,360.921 148.337,352.45 ccw(c149.594,352.45) 149.594,351.193 157.023,351.193 cw(c157.023,350.227) 157.989,350.227 157.989,349.529 ccw(c159.323,349.529) 159.323,348.196 210.769,348.196 cw(c210.769,346.989) 211.976,346.989 211.976,284.493 cw(c211.252,284.493) 211.252,283.769 185.979,283.769 cw(c185.979,284.093) 185.655,284.093 185.655,284.675 cw(c185.765,284.675) v9(185.765,284.785)
  L16 w0.081: v9(151.437,360.528) 151.43,360.528 151.43,359.832 cw(c151.43,359.725) 151.537,359.725 J1_PCIE0.37@151.537,358.792 ; v9(185.765,284.785) 185.758,284.785 185.758,285.42 ccw(c185.758,285.502) 185.839,285.502 C273.2@185.839,285.611
Bank223_MGTREF1_C_N: C278.1 U1.N7 | length 9.7
  L14 (Sign) w0.076: 174.085,287.487 ccw(c174.033,287.487) 174.033,287.539 174.033,294.728 cw(c174.206,294.728) 174.206,294.902 cw(c174.206,294.711) 174.397,294.711 v3(174.397,294.539)
  L14 (Sign) w0.08: 174.085,287.487 174.085,286.544 ccw(c174.182,286.544) v9(174.182,286.447)
  L16 w0.081: v9(174.182,286.447) 174.182,286.098 ccw(c174.231,286.098) 174.231,286.049 C278.1@174.231,285.915
Bank223_MGTREF1_C_P: C277.1 U1.N8 | length 10.1
  L14 (Sign) w0.076: 173.705,287.487 cw(c173.757,287.487) 173.757,287.539 173.757,294.728 cw(c174.206,294.728) 174.206,295.177 ccw(c174.206,295.368) 174.397,295.368 v3(174.397,295.539)
  L14 (Sign) w0.08: v9(173.582,286.447) ccw(c173.582,286.569) 173.705,286.569 173.705,287.487
  L16 w0.081: C277.1@173.533,285.915 173.533,286.049 ccw(c173.533,286.098) 173.582,286.098 v9(173.582,286.447)
Bank223_MGTREF1_N: C278.2 J1_PCIE1.39 | length 122.4
  L14 (Sign) w0.08: 174.072,256.616 174.072,284.408 cw(c174.182,284.408) v9(174.182,284.518) ; 174.475,256.324 ccw(c175.464,256.324) 175.464,255.335 245.656,255.335 ccw(c245.656,256.134) 246.455,256.134 246.455,272.823 ccw(c246.455,272.847) 246.48,272.847 246.48,274.121 cw(c246.59,274.121) v9(246.59,274.231)
  L16 w0.081: v9(174.182,284.518) 174.175,284.518 174.175,285.204 ccw(c174.175,285.261) 174.231,285.261 C278.2@174.231,285.395 ; v9(246.59,274.231) 246.582,274.231 246.582,273.034 cw(c246.582,272.927) 246.69,272.927 J1_PCIE1.39@246.69,271.994
Bank223_MGTREF1_P: C277.2 J1_PCIE1.37 | length 121.2
  L14 (Sign) w0.08: v9(173.582,284.518) cw(c173.582,284.408) 173.692,284.408 173.692,256.616 ; 174.855,256.324 ccw(c175.464,256.324) 175.464,255.714 245.656,255.714 ccw(c245.656,256.134) 246.075,256.134 246.075,273.178 cw(c246.1,273.178) 246.1,273.202 246.1,274.121 ccw(c245.99,274.121) v9(245.99,274.231)
  L16 w0.081: C277.2@173.533,285.395 173.533,285.261 ccw(c173.589,285.261) 173.589,285.204 173.589,284.518 v9(173.582,284.518) ; J1_PCIE1.37@245.89,271.994 245.89,272.927 cw(c245.997,272.927) 245.997,273.034 245.997,274.231 v9(245.99,274.231)
Bank224_MGTREF0_C_N: C288.1 U1.L7 | length 9.7
  L14 (Sign) w0.076: 172.087,287.487 ccw(c172.035,287.487) 172.035,287.539 172.035,294.776 cw(c172.161,294.776) 172.161,294.902 cw(c172.161,294.666) 172.397,294.666 v3(172.397,294.539)
  L14 (Sign) w0.08: 172.087,287.487 172.087,286.578 ccw(c172.194,286.578) v9(172.194,286.47)
  L16 w0.081: v9@172.187,286.47 172.187,286.077 cw(c172.187,286.001) 172.263,286.001 C288.1@172.263,285.886
Bank224_MGTREF0_C_P: C285.1 U1.L8 | length 10.2
  L14 (Sign) w0.076: 171.708,287.487 cw(c171.76,287.487) 171.76,287.539 171.76,294.776 cw(c172.161,294.776) 172.161,295.177 ccw(c172.161,295.413) 172.397,295.413 v3(172.397,295.539)
  L14 (Sign) w0.08: v9(171.594,286.47) ccw(c171.594,286.583) 171.708,286.583 171.708,287.487
  L16 w0.081: C285.1@171.526,285.872 171.526,285.987 cw(c171.602,285.987) 171.602,286.062 v9@171.602,286.47
Bank224_MGTREF0_N: C288.2 J1_PCIE2.39 | length 143.3
  L12 (Sign) w0.073: v12(172.187,284.632) ccw(c172.187,284.44) 171.994,284.44 171.994,281.053 ccw(c172.695,281.053) 172.695,280.352 216.7,280.352 ccw(c216.7,280.937) 217.284,280.937 217.284,351.286 cw(c220.024,351.286) 220.024,354.025 233.007,354.025 ccw(c233.007,354.408) 233.39,354.408 233.39,354.658 ccw(c233.197,354.658) v12(233.197,354.851)
  L16 w0.081: v12(172.187,284.632) 172.187,285.176 ccw(c172.187,285.251) 172.263,285.251 C288.2@172.263,285.366 ; J1_PCIE2.39@233.09,358.792 233.09,357.859 ccw(c233.197,357.859) 233.197,357.751 v12(233.197,354.851)
Bank224_MGTREF0_P: C285.2 J1_PCIE2.37 | length 143.9
  L12 (Sign) w0.073: v12(171.602,284.632) cw(c171.602,284.44) 171.795,284.44 171.795,281.053 ccw(c172.695,281.053) 172.695,280.153 216.7,280.153 ccw(c216.7,280.937) 217.484,280.937 217.484,351.286 cw(c220.024,351.286) 220.024,353.826 233.007,353.826 ccw(c233.007,354.408) 233.589,354.408 233.589,354.658 cw(c233.782,354.658) v12(233.782,354.851)
  L16 w0.081: C285.2@171.526,285.352 171.526,285.237 ccw(c171.602,285.237) 171.602,285.161 v12(171.602,284.632) ; v12(233.782,354.851) 233.782,357.751 ccw(c233.782,357.859) 233.89,357.859 J1_PCIE2.37@233.89,358.792
Bank224_MGTREF1_C_N: C290.1 U1.J7 | length 10.6
  L14 (Sign) w0.076: 169.075,287.539 cw(c169.075,287.591) 169.022,287.591 169.022,294.689 cw(c169.215,294.689) 169.215,294.881 170.055,294.881 cw(c170.055,294.539) v3(170.397,294.539)
  L14 (Sign) w0.08: 169.075,287.539 169.075,286.571 ccw(c169.185,286.571) v9(169.185,286.461)
  L16 w0.081: v9(169.185,286.461) 169.177,286.461 169.177,286.08 cw(c169.177,285.979) 169.278,285.979 C290.1@169.278,285.89
Bank224_MGTREF1_C_P: C289.1 U1.J8 | length 11.1
  L14 (Sign) w0.076: 168.695,287.539 ccw(c168.695,287.591) 168.747,287.591 168.747,294.689 cw(c169.215,294.689) 169.215,295.157 170.014,295.157 ccw(c170.014,295.539) v3(170.397,295.539)
  L14 (Sign) w0.08: v9(168.585,286.461) ccw(c168.585,286.571) 168.695,286.571 168.695,287.539
  L16 w0.081: C289.1@168.491,285.89 168.491,285.979 cw(c168.592,285.979) 168.592,286.08 168.592,286.461 v9(168.585,286.461)
Bank224_MGTREF1_N: C290.2 J1_PCIE3.39 | length 173.7
  L5 (Sign) w0.073: v1(152.476,301.213) cw(c152.676,301.213) 152.676,301.413 152.942,301.413 cw(c152.942,300.863) 153.492,300.863 153.492,287.426 ccw(c154.276,287.426) 154.276,286.643 162.633,286.643 cw(c162.633,285.89) 163.386,285.89 163.386,284.344 ccw(c164.033,284.344) 164.033,283.696 168.277,283.696 cw(c168.277,283.571) v12(168.402,283.571)
  L12 (Sign) w0.073: v1(68.485,356.425) cw(c68.485,356.225) 68.685,356.225 68.685,349.365 ccw(c70.142,349.365) 70.142,347.907 137.118,347.907 cw(c137.118,346.774) 138.252,346.774 138.252,325.34 ccw(c139.548,325.34) 139.548,324.044 147.823,324.044 cw(c147.823,323.278) 148.59,323.278 148.59,303.14 ccw(c150.317,303.14) 150.317,301.413 152.349,301.413 cw(c152.349,301.286) 152.476,301.286 v1(152.476,301.213)
  L16 w0.081: J1_PCIE3.39@68.385,358.792 68.385,357.859 ccw(c68.492,357.859) 68.492,357.751 68.492,356.425 v1(68.485,356.425) ; v12(168.402,283.571) ccw(c168.402,284.346) 169.177,284.346 169.177,285.179 ccw(c169.177,285.28) 169.278,285.28 C290.2@169.278,285.37
Bank224_MGTREF1_P: C289.2 J1_PCIE3.37 | length 172.6
  L5 (Sign) w0.073: v1(152.476,301.813) ccw(c152.676,301.813) 152.676,301.612 152.942,301.612 cw(c152.942,300.863) 153.692,300.863 153.692,287.426 ccw(c154.276,287.426) 154.276,286.842 162.633,286.842 cw(c162.633,285.89) 163.585,285.89 163.585,284.344 ccw(c164.033,284.344) 164.033,283.896 168.277,283.896 ccw(c168.277,284.021) v12(168.402,284.021)
  L12 (Sign) w0.073: v1(69.085,356.425) ccw(c69.085,356.225) 68.884,356.225 68.884,349.365 ccw(c70.142,349.365) 70.142,348.107 137.118,348.107 cw(c137.118,346.774) 138.452,346.774 138.452,325.34 ccw(c139.548,325.34) 139.548,324.244 147.823,324.244 cw(c147.823,323.278) 148.79,323.278 148.79,303.14 ccw(c150.317,303.14) 150.317,301.612 152.349,301.612 ccw(c152.349,301.739) 152.476,301.739 v1(152.476,301.813)
  L16 w0.081: v1(69.085,356.425) 69.077,356.425 69.077,357.751 ccw(c69.077,357.859) 69.185,357.859 J1_PCIE3.37@69.185,358.792 ; v12(168.402,284.021) ccw(c168.402,284.211) 168.592,284.211 168.592,285.179 cw(c168.592,285.28) 168.491,285.28 C289.2@168.491,285.37
Bank225_MGTREF0_C_N: C300.1 U1.H9 | length 13.7
  L14 (Sign) w0.076: 167.108,287.487 ccw(c167.056,287.487) 167.056,287.539 167.056,296.659 cw(c167.298,296.659) 167.298,296.902 169.227,296.902 cw(c169.227,296.732) 169.397,296.732 v3(169.397,296.539)
  L14 (Sign) w0.08: 167.108,287.487 167.108,286.851 ccw(c167.218,286.851) v9(167.218,286.741)
  L16 w0.081: v9(167.218,286.741) 167.218,286.08 cw(c167.218,286.001) 167.297,286.001 C300.1@167.297,285.89
Bank225_MGTREF0_C_P: C297.1 U1.H10 | length 14.1
  L14 (Sign) w0.076: 166.728,287.487 cw(c166.78,287.487) 166.78,287.539 166.78,296.659 cw(c167.298,296.659) 167.298,297.177 169.227,297.177 ccw(c169.227,297.347) 169.397,297.347 v3(169.397,297.539)
  L14 (Sign) w0.08: v9(166.618,286.741) ccw(c166.618,286.851) 166.728,286.851 166.728,287.487
  L16 w0.081: C297.1@166.472,285.89 166.472,285.934 cw(c166.618,285.934) 166.618,286.08 v9(166.618,286.741)
Bank225_MGTREF0_N: C300.2 J1_PCIE4.39 | length 15.9
  L12 (Sign) w0.073: v1(167.181,276.314) 167.158,276.314 cw(c167.158,276.492) 166.98,276.492 166.98,284.381 cw(c167.181,284.381) v1(167.181,284.582)
  L16 w0.073: v1@167.173,276.314 v1(167.181,276.314)
  L16 w0.081: J1_PCIE4.39@164.337,271.994 164.337,272.927 ccw(c164.23,272.927) 164.23,273.034 164.23,273.744 cw(c165.275,273.744) 165.275,274.789 166.258,274.789 ccw(c166.258,275.704) 167.173,275.704 v1@167.173,276.314 ; v1@167.177,284.493 v1@167.177,284.582 ; v1(167.181,284.582) v1@167.177,284.582 ; C300.2@167.297,285.37 167.297,285.299 cw(c167.177,285.299) 167.177,285.179 v1@167.177,284.582
Bank225_MGTREF0_P: C297.2 J1_PCIE4.37 | length 16
  L12 (Sign) w0.073: v1(166.581,276.314) 166.603,276.314 ccw(c166.603,276.492) 166.781,276.492 166.781,284.381 ccw(c166.581,284.381) v1(166.581,284.582)
  L16 w0.073: v1(166.581,276.314) v1@166.588,276.314
  L16 w0.081: J1_PCIE4.37@163.537,271.994 163.537,272.927 cw(c163.644,272.927) 163.644,273.034 163.644,273.744 cw(c165.275,273.744) 165.275,275.374 166.258,275.374 ccw(c166.258,275.704) 166.588,275.704 v1@166.588,276.314 ; C297.2@166.472,285.37 166.472,285.299 ccw(c166.592,285.299) 166.592,285.179 166.592,284.493 166.584,284.493 166.584,284.582 v1(166.581,284.582)
Bank225_MGTREF1_C_N: C302.1 U1.F9
  other v3: 167.397,296.539
Bank225_MGTREF1_C_P: C301.1 U1.F10
  other v3: 167.397,297.539
Bank225_MGTREF1_N: C302.2
Bank225_MGTREF1_P: C301.2
Bank505_MGTRREF0_C_N: C526.2 R69.2 U1.M24 | length 0.7
  L1 w0.116: 172.909,311.052 U1.M24@173.397,311.539
Bank505_MGTRREF0_C_P: C525.2 R69.1 U1.M23 | length 0.7
  L1 w0.116: 172.909,310.052 U1.M23@173.397,310.539
Bank505_MGTRREF2_C_N: C528.2 R126.2 U1.K24
Bank505_MGTRREF2_C_P: C527.2 R126.1 U1.K23
Bank505_MGTRREF3_C_N: C530.2 R70.2 U1.H24
Bank505_MGTRREF3_C_P: C529.2 R70.1 U1.H23
Battery_PWR: P11.1 R679.2 R680.2 U48.2 | length 1.6
  L1 w0.5: R680.2@43.658,195.933 v6(43.658,196.747) ; R679.2@45.775,195.933 v6(45.775,196.747)
  other v6: 46.906,196.145 48.155,196.145 47.566,196.91 46.907,197.647
  other v13: 48.327,194.383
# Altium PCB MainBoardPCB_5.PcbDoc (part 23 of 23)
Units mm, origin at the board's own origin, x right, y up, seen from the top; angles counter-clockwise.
Board outline 258.95 x 308.86 mm, 16 copper layers (L1, L2 (GND), L3 (Sign), L4 (GND), L5 (Sign), L6 (PWR/GND), L7(PWR/GND), L8 (Plane_GND), L9 (PWR/GND), L10 (PWR/GND), L11 (PWR/GND), L12 (Sign), L13 (GND), L14 (Sign), L15 (GND), L16), stack 2.502 mm thick; 2361 components, 1769 nets, 8410 pads, 3285 vias.
Unrouted connection lines stored in the file: 4635.

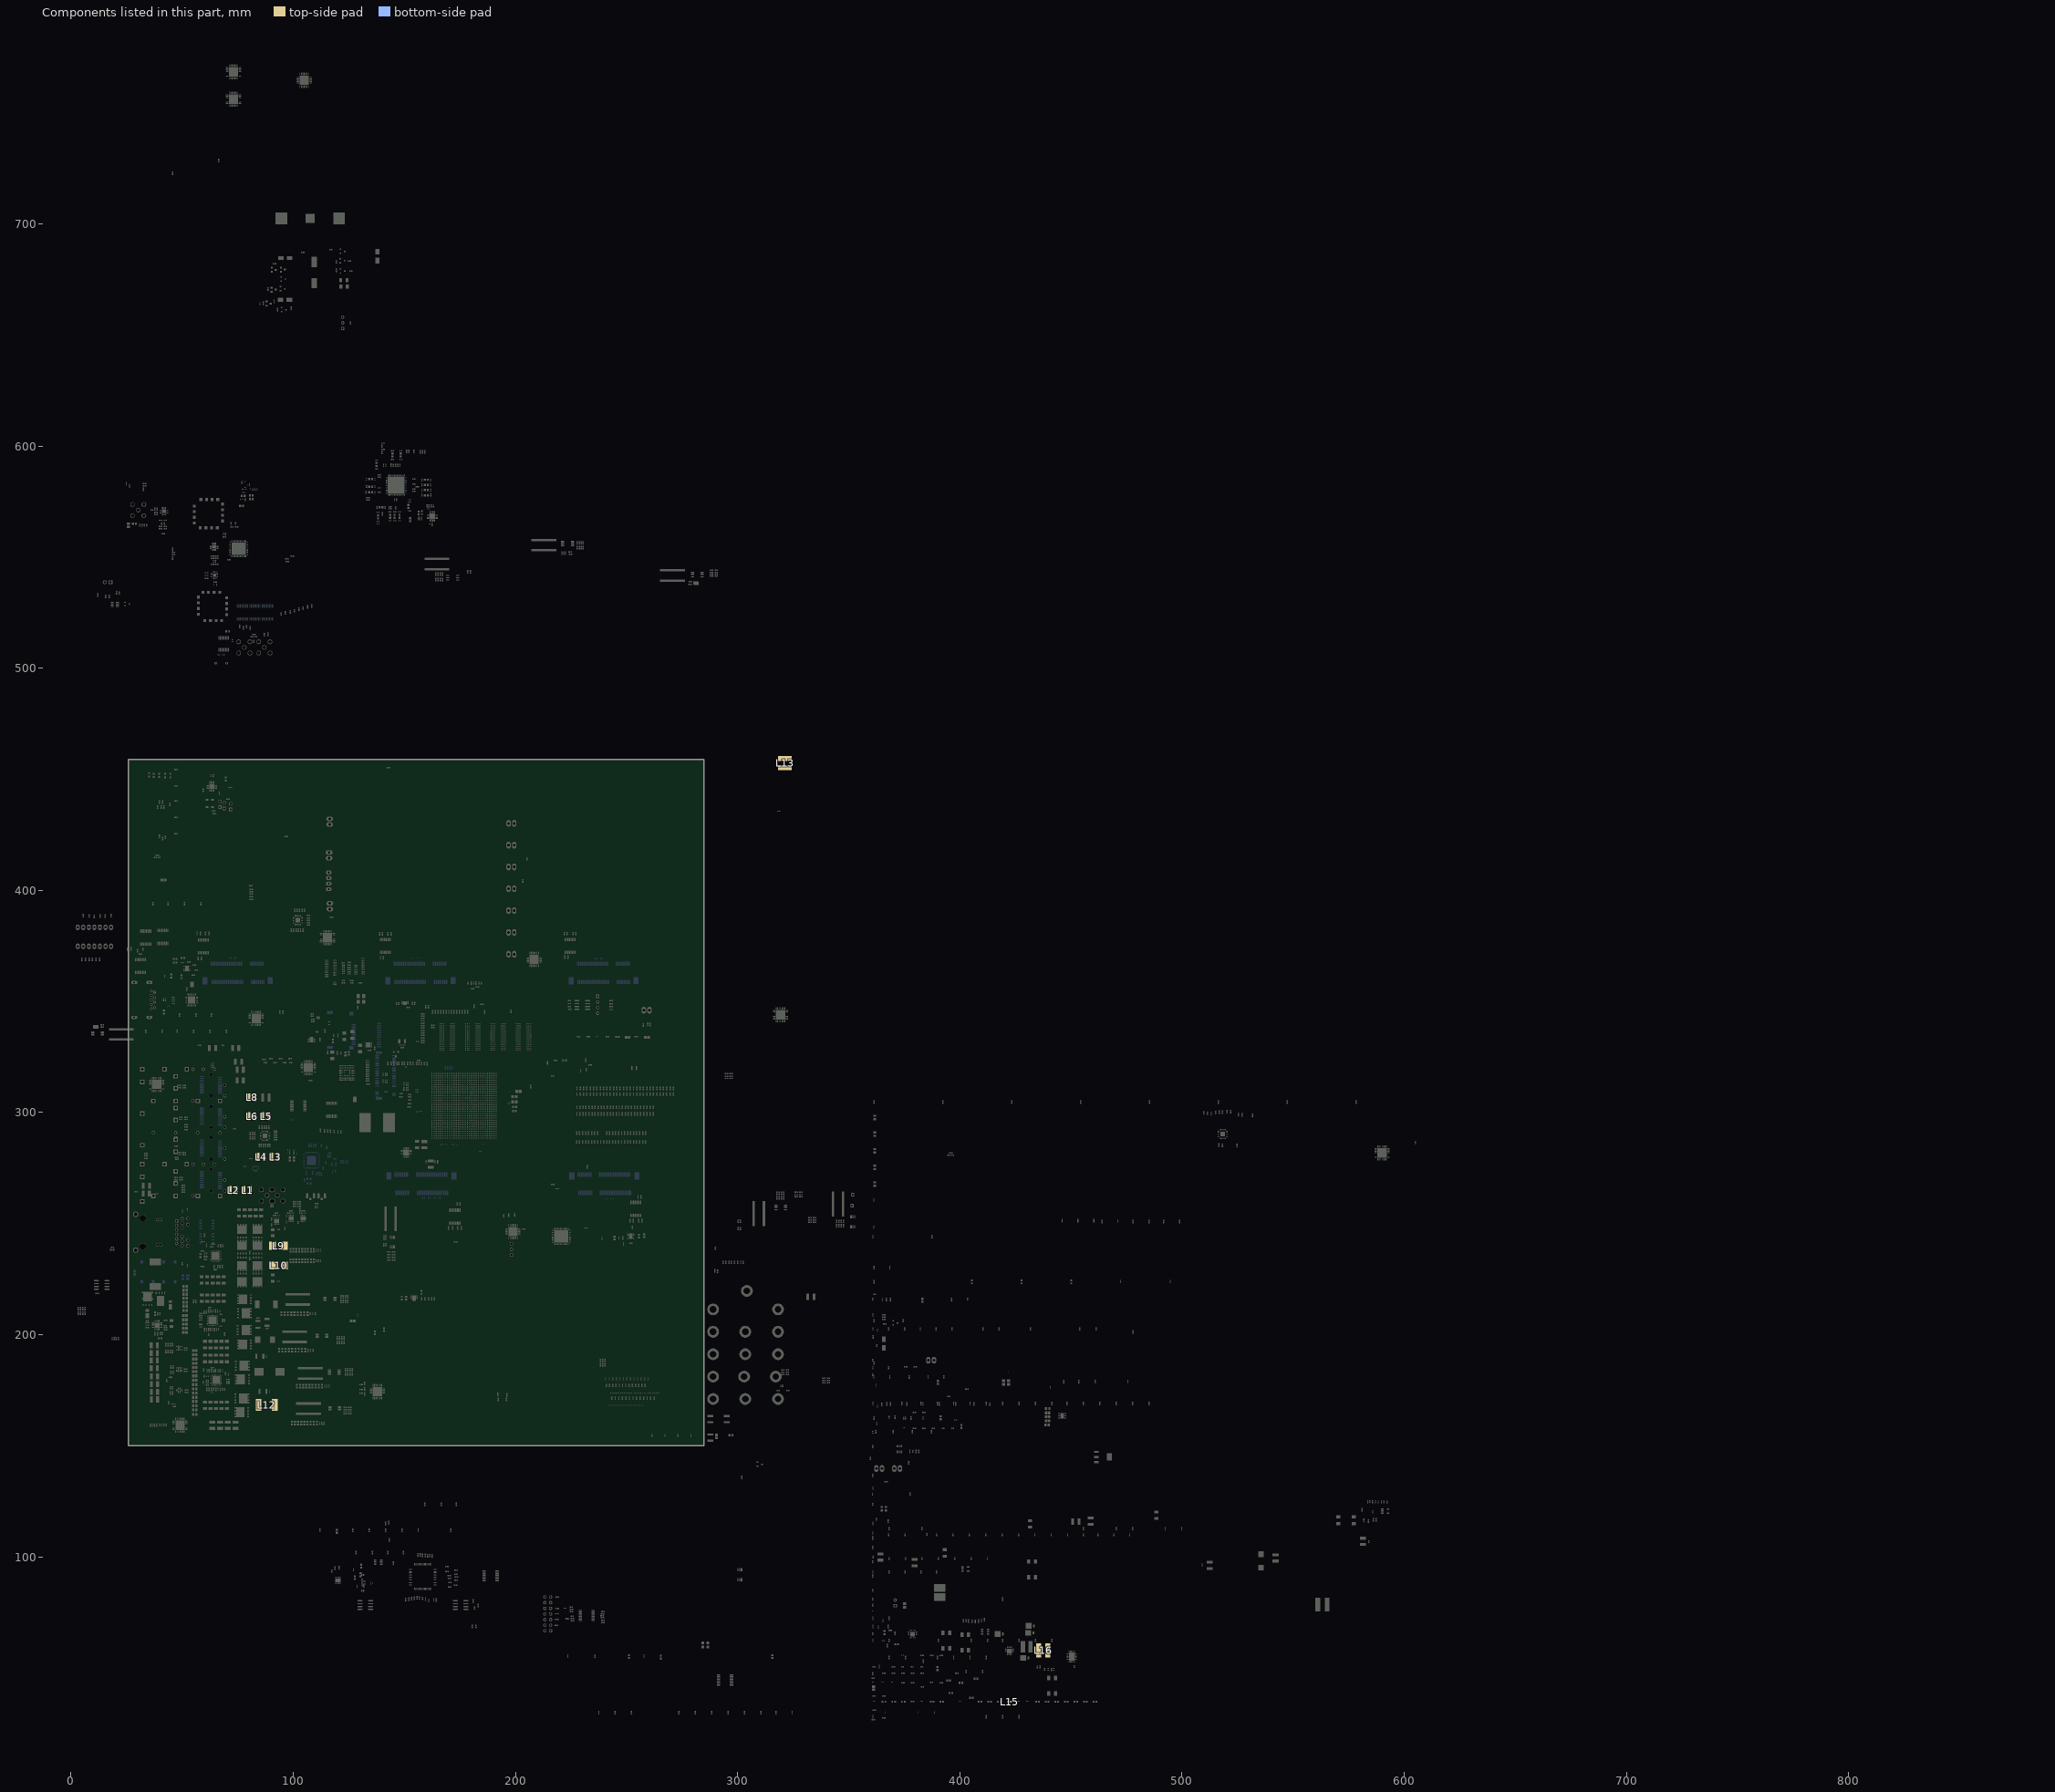
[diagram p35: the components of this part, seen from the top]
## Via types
v1: diameter 0.5, hole 0.2, L1 to L16, tented both sides, 1212 vias
v2: diameter 0.5, hole 0.2, L1 to L16, 494 vias
v3: diameter 0.5/0.35/0.35/0.35/0.35/0.35/0.35/0.35/0.35/0.35/0.35/0.35/0.35/0.35/0.35/0.5 (per signal layer), hole 0.15, L1 to L16, tented both sides, 463 vias
v4: diameter 0.35/0/0.35 (per signal layer), hole 0.127, L1 to L3 (Sign), tented both sides, 283 vias
v5: diameter 0.5/0.35/0.35/0.35/0.35/0.35/0.35/0.35/0.35/0.35/0.35/0.35/0.35/0.35/0.35/0.5 (per signal layer), hole 0.2, L1 to L16, tented both sides, 222 vias
v6: diameter 0.8, hole 0.4, L1 to L16, tented both sides, 168 vias
v7: diameter 2.54, hole 1.02, L1 to L16, 113 vias
v8: diameter 1.4, hole 0.5, L1 to L16, tented both sides, 80 vias
v9: diameter 0.5/0/0.5 (per signal layer), hole 0.2, L14 (Sign) to L16, tented both sides, 52 vias
v10: diameter 0.35, hole 0.127, L1 to L2 (GND), tented both sides, 36 vias
v11: diameter 0.35/0/0.35 (per signal layer), hole 0.127, L1 to L3 (Sign), 19 vias
v12: diameter 0.35, hole 0.127, L1 to L16, tented both sides, 16 vias
v13: diameter 0.4, hole 0.2, L1 to L16, 16 vias
v14: diameter 0.25, hole 0.2, L1 to L16, 16 vias
v15: diameter 0.3, hole 0.2, L1 to L16, 15 vias
v16: diameter 0.45, hole 0.15, L1 to L16, 12 vias
v17: diameter 0.5/0.35/0.35/0.35/0.35/0.35/0.35/0.35/0.35/0.35/0.35/0.35/0.35/0.35/0.35/0.45 (per signal layer), hole 0.15, L1 to L16, tented both sides, 10 vias
v18: diameter 0.2/0/0.2 (per signal layer), hole 0.1, L1 to L3 (Sign), tented both sides, 9 vias
v19: diameter 0.4, hole 0.1, L1 to L16, 7 vias
v20: diameter 1.15, hole 1.15, L1 to L16, 6 vias
v21: diameter 1.65, hole 1.65, L1 to L16, 6 vias
v22: diameter 0.5, hole 0.2, L3 (Sign) to L6 (PWR/GND), tented both sides, 6 vias
v23: diameter 0.35/0/0.35 (per signal layer), hole 0.127, L14 (Sign) to L16, tented both sides, 5 vias
v24: diameter 0.2, hole 0.1, L1 to L16, 4 vias
v25: diameter 0.4, hole 0.2, L1 to L16, tented both sides, 2 vias
v26: diameter 0.4, hole 0.15, L1 to L16, 2 vias
v27: diameter 0.5/0.35/0.35/0.35/0.35/0.35/0.35/0.35/0.35/0.35/0.35/0.35/0.35/0.35/0.35/0.5 (per signal layer), hole 0.15, L1 to L16, 2 vias
v28: diameter 0.35, hole 0.127, L3 (Sign) to L6 (PWR/GND), tented both sides, 2 vias
v29: diameter 5.5, hole 3.5, L1 to L16, 1 vias
v30: diameter 0.5/0.35/0.35/0.35/0.35/0.35/0.35/0.35/0.35/0.35/0.35/0.35/0.35/0.35/0.35/0.5 (per signal layer), hole 0.2, L1 to L16, 1 vias
v31: diameter 0.35/0.35/0.35 (per signal layer), hole 0.127, L1 to L3 (Sign), tented both sides, 1 vias
v32: diameter 0.45/0/0.45 (per signal layer), hole 0.15, L1 to L3 (Sign), tented both sides, 1 vias
v33: diameter 0.45/0/0.45 (per signal layer), hole 0.2, L14 (Sign) to L16, tented both sides, 1 vias
v34: diameter 0.35, hole 0.127, L2 (GND) to L3 (Sign), 1 vias
v35: diameter 0.35, hole 0.127, L1 to L2 (GND), 1 vias

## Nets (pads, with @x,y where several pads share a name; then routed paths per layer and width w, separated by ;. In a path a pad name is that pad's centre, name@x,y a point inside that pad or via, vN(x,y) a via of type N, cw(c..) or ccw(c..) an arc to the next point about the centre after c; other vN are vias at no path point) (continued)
pads on no net: C558.4 D28.1 J1_PCIE0.48 J1_PCIE0.50 J1_PCIE1.48 J1_PCIE1.50 J1_PCIE2.48 J1_PCIE2.50 J1_PCIE3.48 J1_PCIE3.50 J1_PCIE4.48 J1_PCIE4.50 J14.3 J27. J27.5 J27.6 J27.7 J27.8 J27.11 J27.13 J27.17 J27.19 J27.20 J27.22 J27.23 J27.24 J27.25 J27.26 J27.28 J27.30 J27.32 J27.34 J27.36 J27.40 J27.42 J27.44 J27.46 J27.48 J27.56 J27.58 J27.59 J28.MH1 J28.MH2 J32. J33. J33.17 J34. J34.17 J35. J35.17 MP1_PCIE0.1 MP1_PCIE1.1 MP1_PCIE2.1 MP1_PCIE3.1 MP1_PCIE4.1 MP2_PCIE0.1 MP2_PCIE1.1 MP2_PCIE2.1 MP2_PCIE3.1 MP2_PCIE4.1 MP3_PCIE0.1 MP3_PCIE1.1 MP3_PCIE2.1 MP3_PCIE3.1 MP3_PCIE4.1 P12.11 R100.1 R100.2 R867.2 R868.2 R869.2 R870.2 R883.2 R884.2 R885.2 R886.2 R913.2 R914.2 R915.2 R916.2 R917.2 R980.2 R981.2 R982.2 R983.2 R984.2 R985.2 R986.2 R987.2 R988.2 R989.2 R990.2 R991.2 R992.2 R993.2 R994.2 R995.2 R996.2 R997.2 R998.2 R999.2 R1000.2 R1004.2 R1005.2 R1006.2 R1007.2 R1008.2 R1009.2 R1010.2 R1011.2 R1012.2 R1013.2 R1014.2 R1015.2 R1016.2 R1017.2 R1018.2 R1019.2 R1020.2 R1021.2 R1022.2 R1023.2 R1024.2 R1025.2 R1035.2 T5. T6. T7. T8. T9. T10. T11. T12. T13. T14. T15. T16. T17. T18. T19. T20. T21.MH1 T21.MH2 T35. U1.A15 U1.AA8 U1.AA17 U1.AA26 U1.AA30 U1.AB5 U1.AB6 U1.AB8 U1.AB18 U1.AB19 U1.AB20 U1.AB21 U1.AB29 U1.AC7 U1.AC8 U1.AC13 U1.AC19 U1.AD7 U1.AD17 U1.AE3 U1.AE7 U1.AE10 U1.AE12 U1.AE17 U1.AF1 U1.AF2 U1.AF5 U1.AF6 U1.AF11 U1.AF12 U1.AF13 U1.AF15 U1.AF16 U1.AF17 U1.AG5 U1.AG6 U1.AG8 U1.AG9 U1.AG11 U1.AG14 U1.AG15 U1.AG19 U1.AH1 U1.AH4 U1.AH6 U1.AH7 U1.AH8 U1.AH11 U1.AH12 U1.AH14 U1.AJ6 U1.AJ7 U1.AJ12 U1.AJ27 U1.AK2 U1.AK3 U1.B15 U1.C13 U1.D14 U1.D15 U1.D17 U1.E12 U1.E13 U1.E14 U1.E15 U1.E17 U1.F12 U1.F13 U1.F15 U1.F16 U1.G13 U1.G15 U1.G16 U1.L25 U1.L26 U1.W9 U1.W10 U1.W26 U1.W27 U1.Y1 U1.Y9 U1.Y27 U1.Y29 U1.Y30 U8.T4 U9.T4 U10.T4 U11.T4 U13.42 U16.5 U16.6 U16.10 U16.11 U16.18 U30.6 U30.7 U30.8 U31.3 U31.4 U31.8 U31.13 U31.14 U31.15 U31.16 U32.8 U32.13 U32.14 U32.15 U32.16 U33.7 U35_I2C_Expander_00.7 U35_I2C_Expander_00.10 U35_I2C_Expander_01.7 U35_I2C_Expander_01.10 U35_I2C_Expander_02.7 U35_I2C_Expander_02.10 U35_I2C_Expander_10.7 U35_I2C_Expander_10.10 U35_I2C_Expander_11.7 U35_I2C_Expander_11.10 U35_I2C_Expander_12.7 U35_I2C_Expander_12.10 U35_I2C_Expander_16.7 U35_I2C_Expander_16.10 U35_I2C_Expander_17.7 U35_I2C_Expander_17.10 U35_I2C_Expander_18.7 U35_I2C_Expander_18.10 U35_I2C_Expander_Main_Rst.7 U35_I2C_Expander_Main_Rst.10 U35_I2C_Expander_PWR_CLK.7 U35_I2C_Expander_PWR_CLK.10 U35_I2C_Expander_PWR_Dist.7 U35_I2C_Expander_PWR_Dist.10 U35_I2C_Expander_SFP.7 U35_I2C_Expander_SFP.10 U39.18 U39.25 U39.26 U39.29 U39.32 U39.37 U39.38 U39.40 U40.6 U41.A1 U41.A2 U41.A7 U41.A8 U41.A9 U41.A10 U41.A11 U41.A12 U41.A13 U41.A14 U41.B1 U41.B7 U41.B8 U41.B9 U41.B10 U41.B11 U41.B12 U41.B13 U41.B14 U41.C1 U41.C3 U41.C5 U41.C7 U41.C8 U41.C9 U41.C10 U41.C11 U41.C12 U41.C13 U41.C14 U41.D1 U41.D2 U41.D3 U41.D4 U41.D12 U41.D13 U41.D14 U41.E1 U41.E2 U41.E3 U41.E5 U41.E8 U41.E9 U41.E10 U41.E12 U41.E13 U41.E14 U41.F1 U41.F2 U41.F3 U41.F10 U41.F12 U41.F13 U41.F14 U41.G1 U41.G2 U41.G3 U41.G10 U41.G12 U41.G13 U41.G14 U41.H1 U41.H2 U41.H3 U41.H5 U41.H12 U41.H13 U41.H14 U41.J1 U41.J2 U41.J3 U41.J12 U41.J13 U41.J14 U41.K1 U41.K2 U41.K3 U41.K6 U41.K7 U41.K10 U41.K12 U41.K13 U41.K14 U41.L1 U41.L2 U41.L3 U41.L12 U41.L13 U41.L14 U41.M1 U41.M2 U41.M3 U41.M7 U41.M8 U41.M9 U41.M10 U41.M11 U41.M12 U41.M13 U41.M14 U41.N1 U41.N3 U41.N6 U41.N7 U41.N8 U41.N9 U41.N10 U41.N11 U41.N12 U41.N13 U41.N14 U41.P1 U41.P2 U41.P7 U41.P8 U41.P9 U41.P10 U41.P11 U41.P12 U41.P13 U41.P14 U42.6 U44.8 U44.9 U45.12 U45.15 U45.16 U46.B3 U46.C4 U47.E2 U47.E4 U55.36 U55.60 U58.10 U58.11 U59_5V_to_3V3_for_FTDI.6 U59_U_5V_to_3V31.6 U59_U_5V_to_3V32.6 U59_U_5V_to_3V33.6 U60.8 U63.5 U65.1 U69.8 U73.3 U78.3 U78.4
copper on no net: | length 97.9
  L1 w0.116: 182.909,292.052 183.397,292.539 ; 182.909,293.052 183.397,293.539 ; 186.909,300.052 187.397,300.539 ; 206.324,342.392 v3(206.728,342.796) ; 211.541,342.801 211.938,342.405 v4(211.938,342.402) ; 370.718,242.339 v4(371.408,242.339) ; 374.352,239.977 v5(374.839,240.464) ; 374.809,249.091 v2(375.296,249.579) ; 376.803,243.901 v4(377.29,244.389)
  L1 w0.254: 27.941,762.827 28.583,762.827 29.733,761.677 31.157,761.677 31.454,761.974 31.454,762.396 31.51,762.452 ; 27.941,763.477 27.947,763.483 v2(29.391,763.483) ; 27.941,764.127 28.316,764.127 29.516,765.327 31.1,765.327 31.513,764.913 31.513,764.533 ; 28.982,732.274 29.884,732.274 30.949,731.209 32.199,731.209 32.493,731.503 32.493,731.903 34.525,731.903 ; 28.982,732.924 v2(30.518,732.924) ; 28.982,733.574 29.749,733.574 30.949,734.774 32.237,734.774 32.493,734.518 32.493,733.968 34.525,733.968 ; 31.482,762.424 33.286,762.424 33.322,762.459 ; 31.513,763.489 31.514,763.49 v2(32.479,763.49) ; 31.513,764.541 33.325,764.541 ; 32.101,763.496 33.326,763.496 ; 32.493,732.924 v2(33.531,732.924) 34.525,732.924 ; 44.949,775.047 45.853,775.047 46.695,774.205 47.985,774.205 48.177,774.396 48.177,774.732 49.99,774.732 ; 44.949,775.697 v2(46.145,775.697) ; 44.949,776.347 45.724,776.347 46.606,777.229 48.028,777.229 48.177,777.08 48.177,776.682 49.99,776.682 ; 45.26,753.123 46.551,753.123 47.851,751.823 49.388,751.823 49.738,752.173 49.738,752.623 51.554,752.623 ; 45.26,753.773 45.281,753.752 v2(47.327,753.752) ; 45.26,754.423 46.715,754.423 47.851,755.558 49.388,755.558 49.713,755.234 49.713,754.781 49.738,754.756 51.554,754.756 ; 48.177,775.697 v2(49.078,775.697) 49.99,775.697 ; 49.738,753.731 49.758,753.752 v2(50.687,753.752) 50.698,753.741 51.544,753.741 51.554,753.731
  L1 w0.5: v1(42.597,17.328) 42.597,18.415 ; v1(42.597,20.128) 42.597,21.215 ; 43.145,18.415 v1(43.145,19.502) ; 43.145,21.215 v1(43.145,22.302) ; v1(43.694,17.328) 43.694,18.415 ; v1(43.694,20.128) 43.694,21.215 ; 44.25,18.415 v1(44.25,19.502) ; 44.25,21.215 v1(44.25,22.302) ; v1(44.799,17.328) 44.799,18.415 ; v1(44.799,20.128) 44.799,21.215
  L5 (Sign) w0.116: v28(371.685,243.799) v28(372.706,242.779)
  L3 (Sign) w0.092: 212.405,343.017 v22(212.801,342.621)
  L14 (Sign) w0.254: v2(29.391,763.483) 32.472,763.483 v2(32.479,763.49) ; v2(30.518,732.924) v2(33.531,732.924) ; v2(46.145,775.697) v2(49.078,775.697) ; v2(47.327,753.752) v2(50.687,753.752)
  other v3: 195.377,344.081
  other v5: 181.397,288.539
  other v7: 413.931,156.87 426.974,156.896 420.484,157.213 407.099,157.328 413.804,162.052 419.329,162.115 431.406,162.113 425.386,162.141 407.797,162.611 363.601,171.336 370.967,171.336 377.901,171.336 385.267,171.336 392.633,171.336 399.986,171.336 407.352,171.336 414.719,171.336 422.084,171.336 429.45,171.336 436.816,171.336 443.738,171.336 451.104,171.336 458.47,171.336 465.836,171.336 473.202,171.336 480.555,171.336 487.921,171.336 495.287,171.336 502.653,171.336 510.019,171.336 517.385,171.336 363.106,180.556 393.827,180.556 424.548,180.556 455.282,180.556 486.004,180.556 516.725,180.556 546.189,180.556 576.91,180.556 607.631,180.556 638.111,180.556 668.833,180.556 698.284,180.556 727.748,180.556 757.199,180.556 786.651,180.556 816.115,180.556 845.566,180.556 875.03,180.556 363.106,190.792 393.827,190.792 424.548,190.792 455.282,190.792 486.004,190.792 516.725,190.792 546.189,190.792 576.91,190.792 607.631,190.792 638.111,190.792 668.833,190.792 698.284,190.792 727.748,190.792 757.199,190.792 786.651,190.792 816.115,190.792 845.566,190.792 875.03,190.792 363.106,201.028 392.557,201.028 422.008,201.028 451.472,201.028 480.924,201.028 510.375,201.028 538.569,201.028 568.02,201.028 597.484,201.028 626.682,201.028 656.133,201.028 684.327,201.028 712.508,201.028 740.689,201.028 768.883,201.028 797.065,201.028 825.259,201.028 853.44,201.028 363.106,211.264 394.081,211.264 425.056,211.264 456.044,211.264 487.02,211.264 517.995,211.264 548.983,211.264 579.958,211.264 610.933,211.264 641.668,211.264 363.106,221.501 396.875,221.501 291.516,475.577 286.55,477.545 292.138,481.889 310.299,484.721 298.615,484.772 282.943,484.886 304.775,485.33 291.122,487.426 282.651,489.623 306.067,490.69 299.022,490.918 282.88,494.703 290.271,494.982 313.512,496.341 301.447,496.564 307.416,496.786
  other v20: 170.237,267.894 252.59,267.894 62.485,362.892 144.837,362.892 227.19,362.892
  other v21: 145.237,267.894 227.59,267.894 87.485,362.892 169.837,362.892 252.19,362.892
  other v31: 375.296,249.579

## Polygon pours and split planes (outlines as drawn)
US+_Vcc_PS_IntFp on L1 "US+_VCC_PS_INTFP_L01_P099" (solid, pour order 99): 145.706,304.356 148.104,301.958 148.104,289.481 146.012,287.388 138.648,287.388 138.102,287.934 138.112,287.945 138.112,303.81 138.659,304.356
CSP on L1 "L1-CSP" (solid, pour order 279): 35.344,235.28 43.258,235.28 45.949,232.589 45.949,230.226 44.005,228.282 36.106,228.282 34.023,230.365 34.023,234.036 35.242,235.255
no net on L1 "L1-No Net" (solid, pour order 269): 91.618,222.154
12V_LT3042 on L1 "L1-3V3_RAIL" (solid, pour order 267): 101.724,216.814 108.378,216.814 108.938,217.374 108.938,219.836 107.743,221.031 96.275,221.031 94.866,219.621 94.866,217.233 95.272,216.827 101.787,216.827
5V_RAIL on L1 "L1-3V3_RAIL" (solid, pour order 263): 100.266,199.987 106.921,199.987 107.481,200.546 107.481,203.009 106.286,204.203 94.818,204.203 93.408,202.794 93.408,200.406 93.815,200 100.33,200
RAM_Vcc1V2 on L1 "L1-3V3_RAIL" (solid, pour order 261): 106.536,167.665 113.19,167.665 113.75,168.225 113.75,170.687 112.555,171.882 101.087,171.882 99.678,170.472 99.678,168.084 100.084,167.678 106.599,167.678
3V3_RAIL on L1 "L1-3V3_RAIL" (solid, pour order 251): 107.391,183.528 114.046,183.528 114.605,184.087 114.605,186.55 113.411,187.744 101.943,187.744 100.533,186.334 100.533,183.947 100.94,183.54 107.455,183.54
Vout_5V@10A_INA on L1 "L1-Vout_5V@10A_INA" (solid, pour order 249): 92.405,200.584 94.297,198.691 107.455,198.691 110.045,196.101 110.045,193.205 109.828,192.987 89.918,192.987 87.816,195.089 87.816,199.136 89.264,200.584
Vout2_1 on L1 "L1-Vout2_1" (solid, pour order 247): 91.63,172.441 93.398,172.441 100.103,165.735 113.817,165.735 115.595,163.957 115.595,160.909 114.91,160.223 114.91,160.147 114.14,160.147 93.738,160.146 89.599,164.285 89.599,171.501 90.538,172.441
Vout1_1 on L1 "L1-Vout1_1" (solid, pour order 243): 96.208,186.85 101.498,181.559 113.602,181.559 114.579,180.581 114.579,179.317 116.187,179.317 117.615,177.889 117.615,176.949 117.516,176.851 93.685,176.851 90.081,180.454 90.081,185.039 91.892,186.85
Vout1_2 on L1 "L1-Vout1_2" (solid, pour order 239): 92.926,217.589 95.618,214.897 108.372,214.897 111.443,211.826 111.443,210.338 110.605,209.5 92.239,209.5 88.816,212.924 88.816,216.209 90.195,217.589
PWR_OUT_20V on L1 "L1-PWR_OUT_20V" (solid, pour order 235): 48.822,193.927 48.683,193.788 48.683,190.731 49.716,189.698 50.563,189.698 50.931,190.066 50.931,192.373 49.378,193.926 48.835,193.926
PWR_OUT_20V on L1 "L1-PWR_OUT_20V 1" (solid, pour order 233): 48.822,194.039 48.683,194.179 48.683,197.235 49.716,198.269 50.563,198.269 50.931,197.901 50.931,195.593 49.378,194.041 48.835,194.041
Vout_2_Selector on L1 "L1-Vout_2_Selector" (solid, pour order 231): 48.532,193.927 48.671,193.788 48.671,190.731 47.638,189.698 46.792,189.698 46.424,190.066 46.424,192.373 47.976,193.926 48.519,193.926
Battery_PWR on L1 "L1-Battery_PWR" (solid, pour order 229): 48.532,194.039 48.671,194.179 48.671,197.235 47.638,198.269 46.792,198.269 46.424,197.901 46.424,195.593 47.976,194.041 48.519,194.041
Power2_In_CM on L1 "L1-Power2_In_CM" (solid, pour order 227): 45.733,178.917 45.472,179.178 45.202,179.178 45.075,179.051 45.075,177.137 45.288,176.924 45.288,176.32 45.473,176.136 46.943,176.136 47.123,175.943 48.009,175.057 48.552,175.057 48.565,175.056 48.704,175.195 48.704,178.252 47.671,179.285 46.825,179.285 46.456,178.917
Power1_In_CM on L1 "L1-Power1_In_CM" (solid, pour order 225): 46.038,172.167 45.337,172.868 45.337,173.437 45.739,173.839 46.878,173.839 46.892,173.825 48.009,174.942 48.552,174.942 48.565,174.943 48.704,174.804 48.704,171.747 48.636,171.679 48.636,170.464 47.561,169.389 45.822,169.389 45.809,169.402 45.809,169.788 46.038,170.017
Vout_1_Selector on L1 "L1-Vout_1_Selector" (solid, pour order 223): 48.855,175.056 48.716,175.195 48.716,178.252 49.749,179.285 50.595,179.285 50.964,178.917 50.964,176.61 49.411,175.057 48.868,175.057
Vout_1_Selector on L1 "L1-Vout_1_Selector 1" (solid, pour order 221): 48.855,174.943 48.716,174.804 48.716,171.747 49.749,170.714 50.595,170.714 50.964,171.082 50.964,173.389 49.411,174.942 48.868,174.942
Vout_2_Selector on L1 "L1-Vout_2_Selector 1" (solid, pour order 219): 48.855,184.265 48.716,184.126 48.716,181.069 49.749,180.036 50.595,180.036 50.964,180.404 50.964,182.711 49.411,184.264 48.868,184.264
Vout_2_Selector on L1 "L1-Vout_2_Selector 2" (solid, pour order 217): 48.855,184.378 48.716,184.517 48.716,187.574 49.749,188.607 50.595,188.607 50.964,188.239 50.964,185.932 49.411,184.379 48.868,184.379
Vout_1_Selector on L1 "L1-Vout_1_Selector 2" (solid, pour order 215): 48.565,184.265 48.704,184.126 48.704,181.069 47.671,180.036 46.825,180.036 46.456,180.404 46.456,182.711 48.009,184.264 48.552,184.264
CSN on L1 "L1-CSN" (solid, pour order 213): 48.565,184.378 48.704,184.517 48.704,187.574 47.671,188.607 46.825,188.607 46.456,188.239 46.456,185.932 48.009,184.379 48.552,184.379
NetC693_1 on L1 "L1-NetC693_1" (solid, pour order 203): 35.331,225.234 31.229,221.132 31.229,215.252 32.029,214.452 37.211,214.452 38.544,215.786 38.544,217.276 38.909,217.64 42.862,217.64 42.862,223.444 41.072,225.234
SW2_1 on L1 "L1-SW2_1" (solid, pour order 199): 81.298,174.135 83.515,176.352 85.649,176.352 86.39,175.611 86.39,173.63 88.405,171.615 88.405,163.639 85.458,160.693 80.519,160.693 80.519,160.705 78.842,162.382 78.842,167.589 78.308,168.123 75.806,168.123 74.924,169.005 74.924,173.647 75.412,174.135
SW1_1 on L1 "L1-SW1_1" (solid, pour order 195): 78.661,189.37 81.455,192.164 84.112,192.164 85.052,191.224 85.052,188.316 88.405,184.963 88.405,178.905 86.398,176.898 83.145,176.898 79.629,176.898 78.943,177.584 78.943,182.601 78.715,182.829 76.057,182.829 75.311,183.576 75.311,188.341 76.34,189.37
SW2_2 on L1 "L1-SW2_2" (solid, pour order 193): 76.53,204.802 84.863,204.802 86.716,202.949 86.716,194.412 85.407,193.103 80.099,193.103 79.642,193.561 79.642,198.171 79.21,198.603 77.127,198.603 76.086,199.644 76.086,204.357
SW1_2 on L1 "L1-SW1_2" (solid, pour order 191): 81.128,218.415 79.616,216.903 79.616,213.618 79.237,213.239 77.361,213.239 76.276,212.153 76.276,206.375 76.556,206.096 81.946,206.096 82.628,206.778 82.628,208.421 83.041,208.833 84.861,208.833 86.271,207.424 86.271,206.605 86.915,205.962 90.794,205.962 91.421,206.589 91.421,209.055 89.935,210.541 89.027,210.541 87.516,212.052 87.516,217.018 86.119,218.415
SW2 on L1 "SW2_L01_P165" (solid, pour order 165): 88.786,226.099 75.077,226.099 73.698,227.457 73.698,233.323 93.442,233.323 93.442,226.099
SW1 on L1 "SW1_L01_P163" (solid, remove dead copper, pour order 163): 88.328,245.2 74.78,245.2 73.662,244.056 73.662,237.96 93.442,237.96 93.442,245.2
no net on L1 "L1-No Net" (solid, pour order 159): 92.507,97.142
0.85V@40A_INA on L1 "0.85V@40A_INA_L01_P150" (solid, pour order 150): 93.832,226.109 93.832,233.306 97.534,233.306 97.862,232.978 113.243,232.978 113.243,238.214 97.767,238.214 97.5,237.947 93.832,237.947 93.832,245.2 117.137,245.2 117.137,226.109
B503_Ground on L1 "L1-eMMC_GND" (solid, pour order 147): 112.801,233.236 112.8,233.237 98.128,233.237 97.698,233.667 97.684,233.654 73.698,233.654 73.698,237.566 73.711,237.579 97.621,237.579 98.031,237.989 98.032,237.989 112.877,237.989 112.878,237.989 112.878,233.234
0.85V@40A_INA on L1 "0.85V@40A_INA_L01_P113" (solid, pour order 113): 130.202,304.332 127.457,301.587 127.457,290.055 130.149,287.363 137.2,287.363 137.746,287.91 137.735,287.92 137.735,303.785 137.189,304.332
AGND_2 on L1 "AGND_2_L01_P134" (solid, remove dead copper, pour order 134): 58.433,213.225 68.437,213.225 68.437,199.489 59.212,199.489 56.667,202.034 56.667,211.46
B503_Ground on L7(PWR/GND) "B503_GROUND_L07_P259" (solid, pour order 259): 25.865,150.02 359.494,150.02 359.494,499.397 25.865,499.397
3V3_RAIL on L7(PWR/GND) "L7(PWR/GND)-3V3_RAIL" (solid, pour order 255): 112.573,190.82 111.872,190.119 102.243,190.119 99.2,187.076 99.2,183.629 100.419,182.41 114.783,182.41 115.557,181.635 115.557,163.36 119.215,159.702 127.203,159.702 139.268,171.767 139.268,196.139 164.376,221.247 222.872,221.247 272.682,271.056 290.906,271.056 306.794,286.944 306.794,350.291 314.642,358.14 314.642,390.233 302.438,402.438 169.887,402.438 160.692,411.632 53.708,411.632 30.81,388.734 30.81,368.173 63.41,335.573 134.278,335.573 154.508,355.803 205.664,355.803 224.879,336.588 224.879,298.629 207.669,281.419 186.436,281.419 124.422,219.405 117.399,219.354 96.353,219.354 84.569,231.138 84.569,244.284 90.322,250.038 112.674,250.038 114.579,251.943 114.529,251.993 114.529,311.302 105.156,320.675 87.287,320.675 81.534,326.428 38.5,326.428 32.118,320.046 32.118,199.146 38.91,192.354 38.91,168.532 42.951,164.49 71.285,164.49 73.33,166.535 73.33,180.226 87.744,194.64 111.364,194.64 112.573,193.432
US+_Vcc_PS_IntFp on L7(PWR/GND) "US+_VCC_PS_INTFP_L07_P100" (solid, pour order 100): 183.397,310.539 184.397,309.539 184.397,295.539 176.309,287.452 153.022,287.452 138.532,287.452 138.102,287.881 138.102,305.501 143.141,310.539
Vout_1_Selector on L7(PWR/GND) "VOUT_1_SELECTOR_L07_P114" (solid, pour order 114): 48.71,171.566 49.56,170.714 50.782,170.714 51.219,171.151 51.219,179.279 48.872,181.626 48.872,183.189 48.133,183.928 48.369,184.163 48.797,184.163 48.581,184.379 47.911,184.379 45.775,182.242 45.775,180.368 48.71,177.432
SW2 on L7(PWR/GND) "SW2_L07_P135" (solid, pour order 135): 88.786,226.099 75.077,226.099 73.698,227.457 73.698,233.323 93.442,233.323 93.442,226.099
SW1 on L7(PWR/GND) "SW1_L07_P139" (solid, remove dead copper, pour order 139): 88.328,245.2 74.78,245.2 73.662,244.056 73.662,237.96 93.442,237.96 93.442,245.2
0.85V@40A_INA on L7(PWR/GND) "0.85V@40A_INA_L07_P148" (solid, pour order 148): 98.514,243.599 121.488,243.599 125.463,247.574 125.463,300.596 129.984,305.118 136.742,305.118 137.719,304.141 137.719,287.35 142.303,282.765 142.303,232.004 137.132,226.832 98.615,226.832 97.942,227.506 97.942,243.027
B503_Ground on L8 (Plane_GND) "B503_GROUND_L08_P273" (solid, pour order 273): 25.87,150.012 359.499,150.012 359.499,499.389 25.87,499.389
US+_Vcc_PS_IntFp on L8 (Plane_GND) "US+_VCC_PS_INTFP_L08_P098" (solid, pour order 98): 184.397,309.539 184.397,295.539 176.309,287.452 153.022,287.452 138.532,287.452 138.102,287.881 138.102,305.501 142.141,309.539
5V_RAIL on L8 (Plane_GND) "L8 (Plane_GND)-No Net" (solid, pour order 265): 106.762,206.926 93.345,206.926 91.326,204.907 91.326,200.932 93.421,198.836 118.986,198.836 145.39,172.433 210.274,172.433 236.918,199.078 236.918,225.405 234.721,225.405 216.332,243.794 160.071,243.794 131.305,215.029 114.859,215.029 106.769,206.939
0V9@1A_REG3 on L8 (Plane_GND) "L8 (Plane_GND)-0V9@1A_REG3" (solid, pour order 97): 150.203,285.681 152.641,283.243 152.641,280.772 153.492,279.921 154.788,279.921 155.613,280.746 155.613,285.064 153.282,287.395 150.54,287.395 150.203,287.058
0.85V@40A_INA on L8 (Plane_GND) "0.85V@40A_INA_L08_P104" (solid, pour order 104): 98.514,243.599 121.488,243.599 125.463,247.574 125.463,300.596 129.984,305.118 136.742,305.118 137.719,304.141 137.719,287.35 142.303,282.765 142.303,232.004 137.132,226.832 98.615,226.832 97.942,227.506 97.942,243.027
B503_Ground on L6 (PWR/GND) "B503_GROUND_L06_P277" (solid, remove dead copper, pour order 277): 25.87,150.012 359.499,150.012 359.499,499.389 25.87,499.389
US+_Vcc_PS_DDR_504 on L6 (PWR/GND) "US+_VCC_PS_DDR_504_L06_P106" (solid, pour order 106): 181.397,311.539 181.397,314.539 182.909,316.052 185.433,316.052 185.737,315.845 190.59,315.845 192.492,313.944 193.822,313.944 195.929,311.837 195.929,310.267 195.184,309.522 193.352,309.522 191.076,311.798 185.229,311.798 184.459,311.027 181.884,311.027 181.884,311.052
CSP on L6 (PWR/GND) "L6 (PWR/GND)-CSP" (solid, pour order 275): 36.83,235.496 43.193,235.496 49.835,228.854 49.835,202.349 49.136,201.651 44.228,201.651 42.634,203.245 42.634,224.104 35.573,231.166 35.573,234.239
RAM_Vcc1V2 on L9 (PWR/GND) "L9 (PWR/GND)-RAM_Vcc1V2" (solid, pour order 281): 168.383,287.344 168.383,290.919 169.004,291.539 176.973,291.539 179.214,293.781 179.214,303.068 177.965,304.317 177.965,308.994 177.905,309.054 176.912,309.054 175.397,307.539 175.397,295.539 174.397,294.539 167.397,294.539 165.95,295.986 161.915,295.986 161.468,295.539 161.62,295.387 161.662,288.579 160.426,287.344 160.426,228.549 122.517,190.64 122.517,178.689 119.875,176.048 102.984,176.048 97.701,170.764 97.701,167.411 99.936,165.176 131.623,165.176 180.442,213.995 180.442,245.478 202.594,267.631 202.594,278.057 216.421,291.884 216.421,340.462 210.642,346.24 160.845,346.24 153.314,338.709 153.314,328.981 160.426,321.869 188.337,321.869 193.314,316.892 193.256,316.834 193.256,284.607 178.613,269.964 168.432,269.964 167.246,271.488 167.246,277.553 168.453,278.76 168.453,287.274
US+_MGTVccAux on L9 (PWR/GND) "US+_MGTVCCAUX_L09_P103" (solid, pour order 103): 172.397,315.539 173.397,314.539 173.397,313.539 172.397,312.539 172.397,311.539 170.397,311.539 169.397,310.539 169.397,304.539 170.397,303.539 170.397,297.539 169.911,297.053 164.883,297.053 163.397,298.539 159.207,298.539 158.919,298.828 158.919,302.717 159.741,303.539 164.397,303.539 166.397,305.539 166.397,312.539 169.397,315.539
Vout_2_Selector on L9 (PWR/GND) "L9 (PWR/GND)-Vout_2_Selector" (solid, pour order 237): 48.73,184.339 48.729,180.589 49.654,179.663 50.529,179.663 51.194,180.328 51.194,188.436 48.98,190.649 48.98,193.68 48.677,193.983 47.99,193.983 46.284,192.277 46.284,189.77 48.73,187.325
PWR_OUT_20V on L9 (PWR/GND) "PWR_OUT_20V_L09_P167" (solid, pour order 167): 79.121,258.534 86.487,258.534 88.341,256.68 88.341,156.502 55.689,156.502 55.689,240.974 74.155,258.534
no net on L9 (PWR/GND) "NONET_L09_P145" (solid, pour order 145): 60.856,45.86
B503_Ground on L10 (PWR/GND) "B503_GROUND_L10_P109" (solid, remove dead copper, pour order 109): 25.87,150.012 359.499,150.012 359.499,499.389 25.87,499.389
US+_MGTVccAux on L10 (PWR/GND) "US+_MGTVCCAUX_L10_P108" (solid, pour order 108): 186.023,304.851 188.62,304.851 189.154,304.317 189.154,298.782 189.686,298.25 189.686,295.829 188.747,294.89 188.747,293.357 185.572,290.182 182.27,290.182 182.067,290.385 182.067,291.808 184.01,293.751 184.01,302.838
0V9@1A_REG3 on L10 (PWR/GND) "L10 (PWR/GND)-No Net" (solid, pour order 107): 158.064,296.05 156.223,294.208 156.223,289.56 152.133,285.471 151.257,285.471 150.431,286.296 150.431,287.376 153.302,290.246 153.302,294.754 156.718,298.171 158.077,298.171 167.653,298.171 169.901,295.923 171.839,295.923 172.093,296.177 175.76,296.177 176.397,295.539 176.397,294.539 165.397,294.539 163.887,296.05
ETH_VDDIO on L10 (PWR/GND) "ETH_VDDIO_L10_P102" (solid, pour order 102): 165.557,315.862 166.637,314.782 166.637,309.004 167.615,308.026 174.91,308.026 175.793,307.143 175.793,305.13 165.037,305.13 162.826,307.341 156.743,307.341 156.743,312.423 160.391,312.423 163.83,315.862
1V8@0.5A_ADC_filtered on L10 (PWR/GND) "1V8@0.5A_ADC_FILTERED_L10_P101" (solid, pour order 101): 170.129,298.272 170.129,297.437 171.027,296.539 175.855,296.539 176.847,295.546 176.847,288.442 174.282,285.877 154.432,285.877 152.514,283.959 152.514,282.283 152.921,281.876 169.202,281.876 193.18,281.876 203.429,292.125 203.429,311.147 202.308,312.268 199.887,312.268 198.73,311.11 198.73,294.792 191.071,287.134 181.576,287.134 179.921,288.789 179.921,296.215 182.397,298.691 182.397,300.539 182.397,307.048 179.393,310.052 177.324,310.052 176.987,309.715 176.987,309.172 180.397,305.763 180.397,301.644 177.749,298.996 170.854,298.996
no net on L2 (GND) "NONET_L02_P115" (solid, remove dead copper, pour order 115): 174.608,280.136 174.555,280.189 174.555,291.295 189.304,291.295 189.307,291.298 189.307,280.136
no net on L2 (GND) "NONET_L02_P136" (solid, remove dead copper, pour order 136): 216.165,276.488 216.165,286.209 231.974,286.209 231.974,276.984 230.962,275.972 216.681,275.972
B503_Ground on L16 "L16-No Net" (solid, pour order 149): 112.814,233.236 112.813,233.237 98.141,233.237 97.71,233.667 97.696,233.654 73.71,233.654 73.71,237.566 73.723,237.579 97.634,237.579 98.044,237.989 112.89,237.989 112.89,233.234
V_PoE+ on L14 (Sign) "L14 (Sign)-V_PoE+" (solid, pour order 207): 49.6,234.95 55.334,229.216 55.334,219.532 47.324,211.522 31.861,211.522 26.619,216.764 26.619,233.705 27.864,234.95
CSN on L12 (Sign) "L12 (Sign)-CSN" (solid, pour order 211): 41.567,193.065 47.899,186.734 51.083,186.734 51.349,187 51.349,190.07 46.736,194.683 46.736,207.893 46.336,208.293 44.302,208.293 41.567,205.557
RAM_DDR4_VTT on L5 (Sign) "L5 (Sign)-RAM_DDR4_VTT" (solid, pour order 283): 150.244,350.898 150.425,351.079 157.856,351.079 159.956,348.979 179.167,348.979 180.048,348.098 180.048,346.265 179.199,345.417 159.258,345.417 158.737,344.896 158.737,333.997 157.204,332.464 155.766,332.464 154.407,333.823 154.407,345.503 152.552,347.358 150.832,347.358 150.244,347.945
B503_Ground on L13 (GND) "B503_GROUND_L13_P110" (solid, pour order 110): 25.87,150.012 359.499,150.012 359.499,499.389 25.87,499.389
B503_Ground on L4 (GND) "B503_GROUND_L04_P111" (solid, pour order 111): 25.87,150.012 359.499,150.012 359.499,499.389 25.87,499.389
B503_Ground on L15 (GND) "B503_GROUND_L15_P112" (solid, pour order 112): 25.87,150.012 359.499,150.012 359.499,499.389 25.87,499.389

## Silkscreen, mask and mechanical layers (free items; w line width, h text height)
Top Overlay:
  text "0.85V 40A" at 102.387,243.332 h2
  text "12V 8A" at 106.648,211.722 h2
  text "5V 10A" at 104.902,195.707 h2

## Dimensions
26.129,458.617 to 26.129,150.271 on L1
26.129,458.617 to 284.564,458.617 on L1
